VERSION 5.8 ;
BUSBITCHARS "[]" ;
DIVIDERCHAR "/" ;
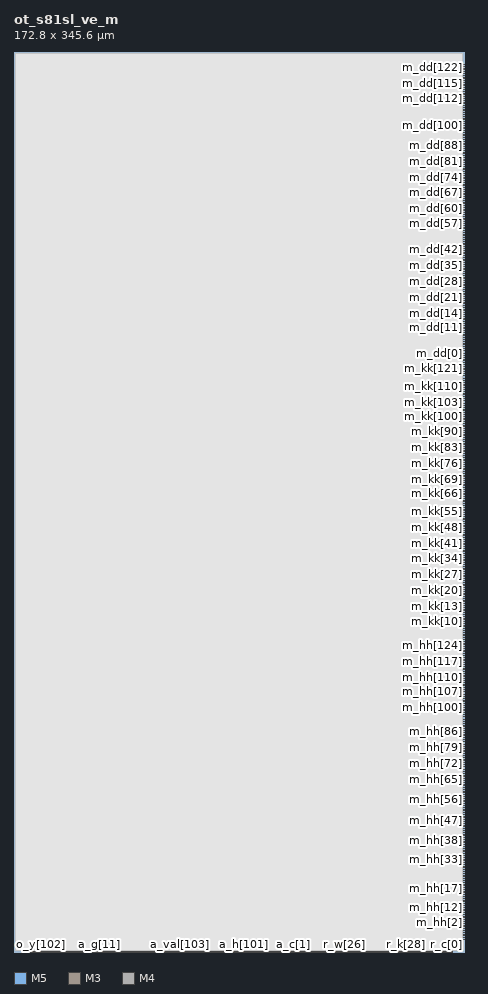
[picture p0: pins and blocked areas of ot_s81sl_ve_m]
MACRO ot_s81sl_ve_m
  CLASS BLOCK ;
  ORIGIN 0 0 ;
  FOREIGN ot_s81sl_ve_m 0 0 ;
  SIZE 172.800 BY 345.600 ;
  SYMMETRY X Y ;
  PIN a_c[0]
    DIRECTION INPUT ;
    USE SIGNAL ;
    PORT
      LAYER M5 ;
        RECT 107.6160 0.0000 107.6400 0.0840 ;
    END
  END a_c[0]
  PIN a_c[1]
    DIRECTION INPUT ;
    USE SIGNAL ;
    PORT
      LAYER M3 ;
        RECT 107.4960 0.0000 107.5140 0.0380 ;
    END
  END a_c[1]
  PIN a_g[0]
    DIRECTION INPUT ;
    USE SIGNAL ;
    PORT
      LAYER M5 ;
        RECT 34.9440 0.0000 34.9680 0.0840 ;
    END
  END a_g[0]
  PIN a_g[10]
    DIRECTION INPUT ;
    USE SIGNAL ;
    PORT
      LAYER M5 ;
        RECT 33.1200 0.0000 33.1440 0.0840 ;
    END
  END a_g[10]
  PIN a_g[11]
    DIRECTION INPUT ;
    USE SIGNAL ;
    PORT
      LAYER M3 ;
        RECT 32.9040 0.0000 32.9220 0.0380 ;
    END
  END a_g[11]
  PIN a_g[12]
    DIRECTION INPUT ;
    USE SIGNAL ;
    PORT
      LAYER M5 ;
        RECT 32.7360 0.0000 32.7600 0.0840 ;
    END
  END a_g[12]
  PIN a_g[13]
    DIRECTION INPUT ;
    USE SIGNAL ;
    PORT
      LAYER M3 ;
        RECT 32.5440 0.0000 32.5620 0.0380 ;
    END
  END a_g[13]
  PIN a_g[14]
    DIRECTION INPUT ;
    USE SIGNAL ;
    PORT
      LAYER M5 ;
        RECT 32.3520 0.0000 32.3760 0.0840 ;
    END
  END a_g[14]
  PIN a_g[15]
    DIRECTION INPUT ;
    USE SIGNAL ;
    PORT
      LAYER M3 ;
        RECT 32.1120 0.0000 32.1300 0.0380 ;
    END
  END a_g[15]
  PIN a_g[16]
    DIRECTION INPUT ;
    USE SIGNAL ;
    PORT
      LAYER M5 ;
        RECT 31.9680 0.0000 31.9920 0.0840 ;
    END
  END a_g[16]
  PIN a_g[17]
    DIRECTION INPUT ;
    USE SIGNAL ;
    PORT
      LAYER M3 ;
        RECT 31.7520 0.0000 31.7700 0.0380 ;
    END
  END a_g[17]
  PIN a_g[18]
    DIRECTION INPUT ;
    USE SIGNAL ;
    PORT
      LAYER M5 ;
        RECT 31.5840 0.0000 31.6080 0.0840 ;
    END
  END a_g[18]
  PIN a_g[19]
    DIRECTION INPUT ;
    USE SIGNAL ;
    PORT
      LAYER M3 ;
        RECT 31.3920 0.0000 31.4100 0.0380 ;
    END
  END a_g[19]
  PIN a_g[1]
    DIRECTION INPUT ;
    USE SIGNAL ;
    PORT
      LAYER M3 ;
        RECT 34.7760 0.0000 34.7940 0.0380 ;
    END
  END a_g[1]
  PIN a_g[20]
    DIRECTION INPUT ;
    USE SIGNAL ;
    PORT
      LAYER M5 ;
        RECT 31.2000 0.0000 31.2240 0.0840 ;
    END
  END a_g[20]
  PIN a_g[21]
    DIRECTION INPUT ;
    USE SIGNAL ;
    PORT
      LAYER M3 ;
        RECT 31.0320 0.0000 31.0500 0.0380 ;
    END
  END a_g[21]
  PIN a_g[22]
    DIRECTION INPUT ;
    USE SIGNAL ;
    PORT
      LAYER M5 ;
        RECT 30.8160 0.0000 30.8400 0.0840 ;
    END
  END a_g[22]
  PIN a_g[23]
    DIRECTION INPUT ;
    USE SIGNAL ;
    PORT
      LAYER M3 ;
        RECT 30.6720 0.0000 30.6900 0.0380 ;
    END
  END a_g[23]
  PIN a_g[24]
    DIRECTION INPUT ;
    USE SIGNAL ;
    PORT
      LAYER M5 ;
        RECT 30.4320 0.0000 30.4560 0.0840 ;
    END
  END a_g[24]
  PIN a_g[25]
    DIRECTION INPUT ;
    USE SIGNAL ;
    PORT
      LAYER M3 ;
        RECT 30.2400 0.0000 30.2580 0.0380 ;
    END
  END a_g[25]
  PIN a_g[26]
    DIRECTION INPUT ;
    USE SIGNAL ;
    PORT
      LAYER M5 ;
        RECT 30.0480 0.0000 30.0720 0.0840 ;
    END
  END a_g[26]
  PIN a_g[27]
    DIRECTION INPUT ;
    USE SIGNAL ;
    PORT
      LAYER M3 ;
        RECT 29.8800 0.0000 29.8980 0.0380 ;
    END
  END a_g[27]
  PIN a_g[28]
    DIRECTION INPUT ;
    USE SIGNAL ;
    PORT
      LAYER M5 ;
        RECT 29.6640 0.0000 29.6880 0.0840 ;
    END
  END a_g[28]
  PIN a_g[29]
    DIRECTION INPUT ;
    USE SIGNAL ;
    PORT
      LAYER M3 ;
        RECT 29.5200 0.0000 29.5380 0.0380 ;
    END
  END a_g[29]
  PIN a_g[2]
    DIRECTION INPUT ;
    USE SIGNAL ;
    PORT
      LAYER M5 ;
        RECT 34.5600 0.0000 34.5840 0.0840 ;
    END
  END a_g[2]
  PIN a_g[30]
    DIRECTION INPUT ;
    USE SIGNAL ;
    PORT
      LAYER M5 ;
        RECT 29.2800 0.0000 29.3040 0.0840 ;
    END
  END a_g[30]
  PIN a_g[31]
    DIRECTION INPUT ;
    USE SIGNAL ;
    PORT
      LAYER M3 ;
        RECT 29.1600 0.0000 29.1780 0.0380 ;
    END
  END a_g[31]
  PIN a_g[3]
    DIRECTION INPUT ;
    USE SIGNAL ;
    PORT
      LAYER M3 ;
        RECT 34.4160 0.0000 34.4340 0.0380 ;
    END
  END a_g[3]
  PIN a_g[4]
    DIRECTION INPUT ;
    USE SIGNAL ;
    PORT
      LAYER M5 ;
        RECT 34.1760 0.0000 34.2000 0.0840 ;
    END
  END a_g[4]
  PIN a_g[5]
    DIRECTION INPUT ;
    USE SIGNAL ;
    PORT
      LAYER M3 ;
        RECT 33.9840 0.0000 34.0020 0.0380 ;
    END
  END a_g[5]
  PIN a_g[6]
    DIRECTION INPUT ;
    USE SIGNAL ;
    PORT
      LAYER M5 ;
        RECT 33.7920 0.0000 33.8160 0.0840 ;
    END
  END a_g[6]
  PIN a_g[7]
    DIRECTION INPUT ;
    USE SIGNAL ;
    PORT
      LAYER M3 ;
        RECT 33.6240 0.0000 33.6420 0.0380 ;
    END
  END a_g[7]
  PIN a_g[8]
    DIRECTION INPUT ;
    USE SIGNAL ;
    PORT
      LAYER M5 ;
        RECT 33.4080 0.0000 33.4320 0.0840 ;
    END
  END a_g[8]
  PIN a_g[9]
    DIRECTION INPUT ;
    USE SIGNAL ;
    PORT
      LAYER M3 ;
        RECT 33.2640 0.0000 33.2820 0.0380 ;
    END
  END a_g[9]
  PIN a_h[0]
    DIRECTION INPUT ;
    USE SIGNAL ;
    PORT
      LAYER M5 ;
        RECT 107.3280 0.0000 107.3520 0.0840 ;
    END
  END a_h[0]
  PIN a_h[100]
    DIRECTION INPUT ;
    USE SIGNAL ;
    PORT
      LAYER M5 ;
        RECT 88.5120 0.0000 88.5360 0.0840 ;
    END
  END a_h[100]
  PIN a_h[101]
    DIRECTION INPUT ;
    USE SIGNAL ;
    PORT
      LAYER M3 ;
        RECT 88.3440 0.0000 88.3620 0.0380 ;
    END
  END a_h[101]
  PIN a_h[102]
    DIRECTION INPUT ;
    USE SIGNAL ;
    PORT
      LAYER M5 ;
        RECT 88.1280 0.0000 88.1520 0.0840 ;
    END
  END a_h[102]
  PIN a_h[103]
    DIRECTION INPUT ;
    USE SIGNAL ;
    PORT
      LAYER M3 ;
        RECT 87.9840 0.0000 88.0020 0.0380 ;
    END
  END a_h[103]
  PIN a_h[104]
    DIRECTION INPUT ;
    USE SIGNAL ;
    PORT
      LAYER M5 ;
        RECT 87.8400 0.0000 87.8640 0.0840 ;
    END
  END a_h[104]
  PIN a_h[105]
    DIRECTION INPUT ;
    USE SIGNAL ;
    PORT
      LAYER M3 ;
        RECT 87.6240 0.0000 87.6420 0.0380 ;
    END
  END a_h[105]
  PIN a_h[106]
    DIRECTION INPUT ;
    USE SIGNAL ;
    PORT
      LAYER M5 ;
        RECT 87.4560 0.0000 87.4800 0.0840 ;
    END
  END a_h[106]
  PIN a_h[107]
    DIRECTION INPUT ;
    USE SIGNAL ;
    PORT
      LAYER M3 ;
        RECT 87.2640 0.0000 87.2820 0.0380 ;
    END
  END a_h[107]
  PIN a_h[108]
    DIRECTION INPUT ;
    USE SIGNAL ;
    PORT
      LAYER M5 ;
        RECT 87.0720 0.0000 87.0960 0.0840 ;
    END
  END a_h[108]
  PIN a_h[109]
    DIRECTION INPUT ;
    USE SIGNAL ;
    PORT
      LAYER M3 ;
        RECT 86.8320 0.0000 86.8500 0.0380 ;
    END
  END a_h[109]
  PIN a_h[10]
    DIRECTION INPUT ;
    USE SIGNAL ;
    PORT
      LAYER M5 ;
        RECT 105.4080 0.0000 105.4320 0.0840 ;
    END
  END a_h[10]
  PIN a_h[110]
    DIRECTION INPUT ;
    USE SIGNAL ;
    PORT
      LAYER M5 ;
        RECT 86.6880 0.0000 86.7120 0.0840 ;
    END
  END a_h[110]
  PIN a_h[111]
    DIRECTION INPUT ;
    USE SIGNAL ;
    PORT
      LAYER M3 ;
        RECT 86.1120 0.0000 86.1300 0.0380 ;
    END
  END a_h[111]
  PIN a_h[112]
    DIRECTION INPUT ;
    USE SIGNAL ;
    PORT
      LAYER M5 ;
        RECT 85.9200 0.0000 85.9440 0.0840 ;
    END
  END a_h[112]
  PIN a_h[113]
    DIRECTION INPUT ;
    USE SIGNAL ;
    PORT
      LAYER M3 ;
        RECT 85.7520 0.0000 85.7700 0.0380 ;
    END
  END a_h[113]
  PIN a_h[114]
    DIRECTION INPUT ;
    USE SIGNAL ;
    PORT
      LAYER M5 ;
        RECT 85.5360 0.0000 85.5600 0.0840 ;
    END
  END a_h[114]
  PIN a_h[115]
    DIRECTION INPUT ;
    USE SIGNAL ;
    PORT
      LAYER M3 ;
        RECT 85.3920 0.0000 85.4100 0.0380 ;
    END
  END a_h[115]
  PIN a_h[116]
    DIRECTION INPUT ;
    USE SIGNAL ;
    PORT
      LAYER M5 ;
        RECT 85.1520 0.0000 85.1760 0.0840 ;
    END
  END a_h[116]
  PIN a_h[117]
    DIRECTION INPUT ;
    USE SIGNAL ;
    PORT
      LAYER M3 ;
        RECT 84.9600 0.0000 84.9780 0.0380 ;
    END
  END a_h[117]
  PIN a_h[118]
    DIRECTION INPUT ;
    USE SIGNAL ;
    PORT
      LAYER M5 ;
        RECT 84.7680 0.0000 84.7920 0.0840 ;
    END
  END a_h[118]
  PIN a_h[119]
    DIRECTION INPUT ;
    USE SIGNAL ;
    PORT
      LAYER M3 ;
        RECT 84.6000 0.0000 84.6180 0.0380 ;
    END
  END a_h[119]
  PIN a_h[11]
    DIRECTION INPUT ;
    USE SIGNAL ;
    PORT
      LAYER M3 ;
        RECT 105.1920 0.0000 105.2100 0.0380 ;
    END
  END a_h[11]
  PIN a_h[120]
    DIRECTION INPUT ;
    USE SIGNAL ;
    PORT
      LAYER M5 ;
        RECT 84.3840 0.0000 84.4080 0.0840 ;
    END
  END a_h[120]
  PIN a_h[121]
    DIRECTION INPUT ;
    USE SIGNAL ;
    PORT
      LAYER M3 ;
        RECT 84.2400 0.0000 84.2580 0.0380 ;
    END
  END a_h[121]
  PIN a_h[122]
    DIRECTION INPUT ;
    USE SIGNAL ;
    PORT
      LAYER M5 ;
        RECT 84.0000 0.0000 84.0240 0.0840 ;
    END
  END a_h[122]
  PIN a_h[123]
    DIRECTION INPUT ;
    USE SIGNAL ;
    PORT
      LAYER M3 ;
        RECT 83.8800 0.0000 83.8980 0.0380 ;
    END
  END a_h[123]
  PIN a_h[124]
    DIRECTION INPUT ;
    USE SIGNAL ;
    PORT
      LAYER M5 ;
        RECT 83.7120 0.0000 83.7360 0.0840 ;
    END
  END a_h[124]
  PIN a_h[125]
    DIRECTION INPUT ;
    USE SIGNAL ;
    PORT
      LAYER M3 ;
        RECT 83.5200 0.0000 83.5380 0.0380 ;
    END
  END a_h[125]
  PIN a_h[126]
    DIRECTION INPUT ;
    USE SIGNAL ;
    PORT
      LAYER M5 ;
        RECT 83.3280 0.0000 83.3520 0.0840 ;
    END
  END a_h[126]
  PIN a_h[127]
    DIRECTION INPUT ;
    USE SIGNAL ;
    PORT
      LAYER M3 ;
        RECT 83.0880 0.0000 83.1060 0.0380 ;
    END
  END a_h[127]
  PIN a_h[12]
    DIRECTION INPUT ;
    USE SIGNAL ;
    PORT
      LAYER M5 ;
        RECT 105.0240 0.0000 105.0480 0.0840 ;
    END
  END a_h[12]
  PIN a_h[13]
    DIRECTION INPUT ;
    USE SIGNAL ;
    PORT
      LAYER M3 ;
        RECT 104.8320 0.0000 104.8500 0.0380 ;
    END
  END a_h[13]
  PIN a_h[14]
    DIRECTION INPUT ;
    USE SIGNAL ;
    PORT
      LAYER M5 ;
        RECT 104.6400 0.0000 104.6640 0.0840 ;
    END
  END a_h[14]
  PIN a_h[15]
    DIRECTION INPUT ;
    USE SIGNAL ;
    PORT
      LAYER M3 ;
        RECT 104.4720 0.0000 104.4900 0.0380 ;
    END
  END a_h[15]
  PIN a_h[16]
    DIRECTION INPUT ;
    USE SIGNAL ;
    PORT
      LAYER M5 ;
        RECT 104.2560 0.0000 104.2800 0.0840 ;
    END
  END a_h[16]
  PIN a_h[17]
    DIRECTION INPUT ;
    USE SIGNAL ;
    PORT
      LAYER M3 ;
        RECT 104.1120 0.0000 104.1300 0.0380 ;
    END
  END a_h[17]
  PIN a_h[18]
    DIRECTION INPUT ;
    USE SIGNAL ;
    PORT
      LAYER M5 ;
        RECT 103.8720 0.0000 103.8960 0.0840 ;
    END
  END a_h[18]
  PIN a_h[19]
    DIRECTION INPUT ;
    USE SIGNAL ;
    PORT
      LAYER M3 ;
        RECT 103.7520 0.0000 103.7700 0.0380 ;
    END
  END a_h[19]
  PIN a_h[1]
    DIRECTION INPUT ;
    USE SIGNAL ;
    PORT
      LAYER M3 ;
        RECT 107.0640 0.0000 107.0820 0.0380 ;
    END
  END a_h[1]
  PIN a_h[20]
    DIRECTION INPUT ;
    USE SIGNAL ;
    PORT
      LAYER M5 ;
        RECT 103.4880 0.0000 103.5120 0.0840 ;
    END
  END a_h[20]
  PIN a_h[21]
    DIRECTION INPUT ;
    USE SIGNAL ;
    PORT
      LAYER M3 ;
        RECT 103.3200 0.0000 103.3380 0.0380 ;
    END
  END a_h[21]
  PIN a_h[22]
    DIRECTION INPUT ;
    USE SIGNAL ;
    PORT
      LAYER M5 ;
        RECT 103.2000 0.0000 103.2240 0.0840 ;
    END
  END a_h[22]
  PIN a_h[23]
    DIRECTION INPUT ;
    USE SIGNAL ;
    PORT
      LAYER M3 ;
        RECT 102.9600 0.0000 102.9780 0.0380 ;
    END
  END a_h[23]
  PIN a_h[24]
    DIRECTION INPUT ;
    USE SIGNAL ;
    PORT
      LAYER M5 ;
        RECT 102.8160 0.0000 102.8400 0.0840 ;
    END
  END a_h[24]
  PIN a_h[25]
    DIRECTION INPUT ;
    USE SIGNAL ;
    PORT
      LAYER M3 ;
        RECT 102.6000 0.0000 102.6180 0.0380 ;
    END
  END a_h[25]
  PIN a_h[26]
    DIRECTION INPUT ;
    USE SIGNAL ;
    PORT
      LAYER M5 ;
        RECT 102.4320 0.0000 102.4560 0.0840 ;
    END
  END a_h[26]
  PIN a_h[27]
    DIRECTION INPUT ;
    USE SIGNAL ;
    PORT
      LAYER M3 ;
        RECT 102.2400 0.0000 102.2580 0.0380 ;
    END
  END a_h[27]
  PIN a_h[28]
    DIRECTION INPUT ;
    USE SIGNAL ;
    PORT
      LAYER M5 ;
        RECT 102.0480 0.0000 102.0720 0.0840 ;
    END
  END a_h[28]
  PIN a_h[29]
    DIRECTION INPUT ;
    USE SIGNAL ;
    PORT
      LAYER M3 ;
        RECT 101.8800 0.0000 101.8980 0.0380 ;
    END
  END a_h[29]
  PIN a_h[2]
    DIRECTION INPUT ;
    USE SIGNAL ;
    PORT
      LAYER M5 ;
        RECT 106.9440 0.0000 106.9680 0.0840 ;
    END
  END a_h[2]
  PIN a_h[30]
    DIRECTION INPUT ;
    USE SIGNAL ;
    PORT
      LAYER M5 ;
        RECT 101.6640 0.0000 101.6880 0.0840 ;
    END
  END a_h[30]
  PIN a_h[31]
    DIRECTION INPUT ;
    USE SIGNAL ;
    PORT
      LAYER M3 ;
        RECT 101.4480 0.0000 101.4660 0.0380 ;
    END
  END a_h[31]
  PIN a_h[32]
    DIRECTION INPUT ;
    USE SIGNAL ;
    PORT
      LAYER M5 ;
        RECT 101.2800 0.0000 101.3040 0.0840 ;
    END
  END a_h[32]
  PIN a_h[33]
    DIRECTION INPUT ;
    USE SIGNAL ;
    PORT
      LAYER M3 ;
        RECT 101.0880 0.0000 101.1060 0.0380 ;
    END
  END a_h[33]
  PIN a_h[34]
    DIRECTION INPUT ;
    USE SIGNAL ;
    PORT
      LAYER M5 ;
        RECT 100.8960 0.0000 100.9200 0.0840 ;
    END
  END a_h[34]
  PIN a_h[35]
    DIRECTION INPUT ;
    USE SIGNAL ;
    PORT
      LAYER M3 ;
        RECT 100.7280 0.0000 100.7460 0.0380 ;
    END
  END a_h[35]
  PIN a_h[36]
    DIRECTION INPUT ;
    USE SIGNAL ;
    PORT
      LAYER M5 ;
        RECT 100.5120 0.0000 100.5360 0.0840 ;
    END
  END a_h[36]
  PIN a_h[37]
    DIRECTION INPUT ;
    USE SIGNAL ;
    PORT
      LAYER M3 ;
        RECT 100.3680 0.0000 100.3860 0.0380 ;
    END
  END a_h[37]
  PIN a_h[38]
    DIRECTION INPUT ;
    USE SIGNAL ;
    PORT
      LAYER M5 ;
        RECT 100.1280 0.0000 100.1520 0.0840 ;
    END
  END a_h[38]
  PIN a_h[39]
    DIRECTION INPUT ;
    USE SIGNAL ;
    PORT
      LAYER M3 ;
        RECT 100.0080 0.0000 100.0260 0.0380 ;
    END
  END a_h[39]
  PIN a_h[3]
    DIRECTION INPUT ;
    USE SIGNAL ;
    PORT
      LAYER M3 ;
        RECT 106.7040 0.0000 106.7220 0.0380 ;
    END
  END a_h[3]
  PIN a_h[40]
    DIRECTION INPUT ;
    USE SIGNAL ;
    PORT
      LAYER M5 ;
        RECT 99.7440 0.0000 99.7680 0.0840 ;
    END
  END a_h[40]
  PIN a_h[41]
    DIRECTION INPUT ;
    USE SIGNAL ;
    PORT
      LAYER M3 ;
        RECT 99.5760 0.0000 99.5940 0.0380 ;
    END
  END a_h[41]
  PIN a_h[42]
    DIRECTION INPUT ;
    USE SIGNAL ;
    PORT
      LAYER M5 ;
        RECT 99.4560 0.0000 99.4800 0.0840 ;
    END
  END a_h[42]
  PIN a_h[43]
    DIRECTION INPUT ;
    USE SIGNAL ;
    PORT
      LAYER M3 ;
        RECT 99.2160 0.0000 99.2340 0.0380 ;
    END
  END a_h[43]
  PIN a_h[44]
    DIRECTION INPUT ;
    USE SIGNAL ;
    PORT
      LAYER M5 ;
        RECT 99.0720 0.0000 99.0960 0.0840 ;
    END
  END a_h[44]
  PIN a_h[45]
    DIRECTION INPUT ;
    USE SIGNAL ;
    PORT
      LAYER M3 ;
        RECT 98.8560 0.0000 98.8740 0.0380 ;
    END
  END a_h[45]
  PIN a_h[46]
    DIRECTION INPUT ;
    USE SIGNAL ;
    PORT
      LAYER M5 ;
        RECT 98.6880 0.0000 98.7120 0.0840 ;
    END
  END a_h[46]
  PIN a_h[47]
    DIRECTION INPUT ;
    USE SIGNAL ;
    PORT
      LAYER M3 ;
        RECT 98.4960 0.0000 98.5140 0.0380 ;
    END
  END a_h[47]
  PIN a_h[48]
    DIRECTION INPUT ;
    USE SIGNAL ;
    PORT
      LAYER M5 ;
        RECT 98.3040 0.0000 98.3280 0.0840 ;
    END
  END a_h[48]
  PIN a_h[49]
    DIRECTION INPUT ;
    USE SIGNAL ;
    PORT
      LAYER M3 ;
        RECT 98.1360 0.0000 98.1540 0.0380 ;
    END
  END a_h[49]
  PIN a_h[4]
    DIRECTION INPUT ;
    USE SIGNAL ;
    PORT
      LAYER M5 ;
        RECT 106.5600 0.0000 106.5840 0.0840 ;
    END
  END a_h[4]
  PIN a_h[50]
    DIRECTION INPUT ;
    USE SIGNAL ;
    PORT
      LAYER M5 ;
        RECT 97.9200 0.0000 97.9440 0.0840 ;
    END
  END a_h[50]
  PIN a_h[51]
    DIRECTION INPUT ;
    USE SIGNAL ;
    PORT
      LAYER M3 ;
        RECT 97.7040 0.0000 97.7220 0.0380 ;
    END
  END a_h[51]
  PIN a_h[52]
    DIRECTION INPUT ;
    USE SIGNAL ;
    PORT
      LAYER M5 ;
        RECT 97.5360 0.0000 97.5600 0.0840 ;
    END
  END a_h[52]
  PIN a_h[53]
    DIRECTION INPUT ;
    USE SIGNAL ;
    PORT
      LAYER M3 ;
        RECT 97.3440 0.0000 97.3620 0.0380 ;
    END
  END a_h[53]
  PIN a_h[54]
    DIRECTION INPUT ;
    USE SIGNAL ;
    PORT
      LAYER M5 ;
        RECT 97.1520 0.0000 97.1760 0.0840 ;
    END
  END a_h[54]
  PIN a_h[55]
    DIRECTION INPUT ;
    USE SIGNAL ;
    PORT
      LAYER M3 ;
        RECT 96.9840 0.0000 97.0020 0.0380 ;
    END
  END a_h[55]
  PIN a_h[56]
    DIRECTION INPUT ;
    USE SIGNAL ;
    PORT
      LAYER M5 ;
        RECT 96.7680 0.0000 96.7920 0.0840 ;
    END
  END a_h[56]
  PIN a_h[57]
    DIRECTION INPUT ;
    USE SIGNAL ;
    PORT
      LAYER M3 ;
        RECT 96.6240 0.0000 96.6420 0.0380 ;
    END
  END a_h[57]
  PIN a_h[58]
    DIRECTION INPUT ;
    USE SIGNAL ;
    PORT
      LAYER M5 ;
        RECT 96.3840 0.0000 96.4080 0.0840 ;
    END
  END a_h[58]
  PIN a_h[59]
    DIRECTION INPUT ;
    USE SIGNAL ;
    PORT
      LAYER M3 ;
        RECT 96.2640 0.0000 96.2820 0.0380 ;
    END
  END a_h[59]
  PIN a_h[5]
    DIRECTION INPUT ;
    USE SIGNAL ;
    PORT
      LAYER M3 ;
        RECT 106.3440 0.0000 106.3620 0.0380 ;
    END
  END a_h[5]
  PIN a_h[60]
    DIRECTION INPUT ;
    USE SIGNAL ;
    PORT
      LAYER M5 ;
        RECT 96.0000 0.0000 96.0240 0.0840 ;
    END
  END a_h[60]
  PIN a_h[61]
    DIRECTION INPUT ;
    USE SIGNAL ;
    PORT
      LAYER M3 ;
        RECT 95.8320 0.0000 95.8500 0.0380 ;
    END
  END a_h[61]
  PIN a_h[62]
    DIRECTION INPUT ;
    USE SIGNAL ;
    PORT
      LAYER M5 ;
        RECT 95.7120 0.0000 95.7360 0.0840 ;
    END
  END a_h[62]
  PIN a_h[63]
    DIRECTION INPUT ;
    USE SIGNAL ;
    PORT
      LAYER M3 ;
        RECT 95.4720 0.0000 95.4900 0.0380 ;
    END
  END a_h[63]
  PIN a_h[64]
    DIRECTION INPUT ;
    USE SIGNAL ;
    PORT
      LAYER M5 ;
        RECT 95.3280 0.0000 95.3520 0.0840 ;
    END
  END a_h[64]
  PIN a_h[65]
    DIRECTION INPUT ;
    USE SIGNAL ;
    PORT
      LAYER M3 ;
        RECT 95.1120 0.0000 95.1300 0.0380 ;
    END
  END a_h[65]
  PIN a_h[66]
    DIRECTION INPUT ;
    USE SIGNAL ;
    PORT
      LAYER M5 ;
        RECT 94.9440 0.0000 94.9680 0.0840 ;
    END
  END a_h[66]
  PIN a_h[67]
    DIRECTION INPUT ;
    USE SIGNAL ;
    PORT
      LAYER M3 ;
        RECT 94.7520 0.0000 94.7700 0.0380 ;
    END
  END a_h[67]
  PIN a_h[68]
    DIRECTION INPUT ;
    USE SIGNAL ;
    PORT
      LAYER M5 ;
        RECT 94.5600 0.0000 94.5840 0.0840 ;
    END
  END a_h[68]
  PIN a_h[69]
    DIRECTION INPUT ;
    USE SIGNAL ;
    PORT
      LAYER M3 ;
        RECT 94.3200 0.0000 94.3380 0.0380 ;
    END
  END a_h[69]
  PIN a_h[6]
    DIRECTION INPUT ;
    USE SIGNAL ;
    PORT
      LAYER M5 ;
        RECT 106.1760 0.0000 106.2000 0.0840 ;
    END
  END a_h[6]
  PIN a_h[70]
    DIRECTION INPUT ;
    USE SIGNAL ;
    PORT
      LAYER M5 ;
        RECT 94.1760 0.0000 94.2000 0.0840 ;
    END
  END a_h[70]
  PIN a_h[71]
    DIRECTION INPUT ;
    USE SIGNAL ;
    PORT
      LAYER M3 ;
        RECT 93.9600 0.0000 93.9780 0.0380 ;
    END
  END a_h[71]
  PIN a_h[72]
    DIRECTION INPUT ;
    USE SIGNAL ;
    PORT
      LAYER M5 ;
        RECT 93.7920 0.0000 93.8160 0.0840 ;
    END
  END a_h[72]
  PIN a_h[73]
    DIRECTION INPUT ;
    USE SIGNAL ;
    PORT
      LAYER M3 ;
        RECT 93.6000 0.0000 93.6180 0.0380 ;
    END
  END a_h[73]
  PIN a_h[74]
    DIRECTION INPUT ;
    USE SIGNAL ;
    PORT
      LAYER M5 ;
        RECT 93.4080 0.0000 93.4320 0.0840 ;
    END
  END a_h[74]
  PIN a_h[75]
    DIRECTION INPUT ;
    USE SIGNAL ;
    PORT
      LAYER M3 ;
        RECT 93.2400 0.0000 93.2580 0.0380 ;
    END
  END a_h[75]
  PIN a_h[76]
    DIRECTION INPUT ;
    USE SIGNAL ;
    PORT
      LAYER M5 ;
        RECT 93.0240 0.0000 93.0480 0.0840 ;
    END
  END a_h[76]
  PIN a_h[77]
    DIRECTION INPUT ;
    USE SIGNAL ;
    PORT
      LAYER M3 ;
        RECT 92.8800 0.0000 92.8980 0.0380 ;
    END
  END a_h[77]
  PIN a_h[78]
    DIRECTION INPUT ;
    USE SIGNAL ;
    PORT
      LAYER M5 ;
        RECT 92.6400 0.0000 92.6640 0.0840 ;
    END
  END a_h[78]
  PIN a_h[79]
    DIRECTION INPUT ;
    USE SIGNAL ;
    PORT
      LAYER M3 ;
        RECT 92.4480 0.0000 92.4660 0.0380 ;
    END
  END a_h[79]
  PIN a_h[7]
    DIRECTION INPUT ;
    USE SIGNAL ;
    PORT
      LAYER M3 ;
        RECT 105.9840 0.0000 106.0020 0.0380 ;
    END
  END a_h[7]
  PIN a_h[80]
    DIRECTION INPUT ;
    USE SIGNAL ;
    PORT
      LAYER M5 ;
        RECT 92.2560 0.0000 92.2800 0.0840 ;
    END
  END a_h[80]
  PIN a_h[81]
    DIRECTION INPUT ;
    USE SIGNAL ;
    PORT
      LAYER M3 ;
        RECT 92.0880 0.0000 92.1060 0.0380 ;
    END
  END a_h[81]
  PIN a_h[82]
    DIRECTION INPUT ;
    USE SIGNAL ;
    PORT
      LAYER M5 ;
        RECT 91.8720 0.0000 91.8960 0.0840 ;
    END
  END a_h[82]
  PIN a_h[83]
    DIRECTION INPUT ;
    USE SIGNAL ;
    PORT
      LAYER M3 ;
        RECT 91.7280 0.0000 91.7460 0.0380 ;
    END
  END a_h[83]
  PIN a_h[84]
    DIRECTION INPUT ;
    USE SIGNAL ;
    PORT
      LAYER M5 ;
        RECT 91.5840 0.0000 91.6080 0.0840 ;
    END
  END a_h[84]
  PIN a_h[85]
    DIRECTION INPUT ;
    USE SIGNAL ;
    PORT
      LAYER M3 ;
        RECT 91.3680 0.0000 91.3860 0.0380 ;
    END
  END a_h[85]
  PIN a_h[86]
    DIRECTION INPUT ;
    USE SIGNAL ;
    PORT
      LAYER M5 ;
        RECT 91.2000 0.0000 91.2240 0.0840 ;
    END
  END a_h[86]
  PIN a_h[87]
    DIRECTION INPUT ;
    USE SIGNAL ;
    PORT
      LAYER M3 ;
        RECT 91.0080 0.0000 91.0260 0.0380 ;
    END
  END a_h[87]
  PIN a_h[88]
    DIRECTION INPUT ;
    USE SIGNAL ;
    PORT
      LAYER M5 ;
        RECT 90.8160 0.0000 90.8400 0.0840 ;
    END
  END a_h[88]
  PIN a_h[89]
    DIRECTION INPUT ;
    USE SIGNAL ;
    PORT
      LAYER M3 ;
        RECT 90.5760 0.0000 90.5940 0.0380 ;
    END
  END a_h[89]
  PIN a_h[8]
    DIRECTION INPUT ;
    USE SIGNAL ;
    PORT
      LAYER M5 ;
        RECT 105.7920 0.0000 105.8160 0.0840 ;
    END
  END a_h[8]
  PIN a_h[90]
    DIRECTION INPUT ;
    USE SIGNAL ;
    PORT
      LAYER M5 ;
        RECT 90.4320 0.0000 90.4560 0.0840 ;
    END
  END a_h[90]
  PIN a_h[91]
    DIRECTION INPUT ;
    USE SIGNAL ;
    PORT
      LAYER M3 ;
        RECT 90.2160 0.0000 90.2340 0.0380 ;
    END
  END a_h[91]
  PIN a_h[92]
    DIRECTION INPUT ;
    USE SIGNAL ;
    PORT
      LAYER M5 ;
        RECT 90.0480 0.0000 90.0720 0.0840 ;
    END
  END a_h[92]
  PIN a_h[93]
    DIRECTION INPUT ;
    USE SIGNAL ;
    PORT
      LAYER M3 ;
        RECT 89.8560 0.0000 89.8740 0.0380 ;
    END
  END a_h[93]
  PIN a_h[94]
    DIRECTION INPUT ;
    USE SIGNAL ;
    PORT
      LAYER M5 ;
        RECT 89.6640 0.0000 89.6880 0.0840 ;
    END
  END a_h[94]
  PIN a_h[95]
    DIRECTION INPUT ;
    USE SIGNAL ;
    PORT
      LAYER M3 ;
        RECT 89.4960 0.0000 89.5140 0.0380 ;
    END
  END a_h[95]
  PIN a_h[96]
    DIRECTION INPUT ;
    USE SIGNAL ;
    PORT
      LAYER M5 ;
        RECT 89.2800 0.0000 89.3040 0.0840 ;
    END
  END a_h[96]
  PIN a_h[97]
    DIRECTION INPUT ;
    USE SIGNAL ;
    PORT
      LAYER M3 ;
        RECT 89.1360 0.0000 89.1540 0.0380 ;
    END
  END a_h[97]
  PIN a_h[98]
    DIRECTION INPUT ;
    USE SIGNAL ;
    PORT
      LAYER M5 ;
        RECT 88.8960 0.0000 88.9200 0.0840 ;
    END
  END a_h[98]
  PIN a_h[99]
    DIRECTION INPUT ;
    USE SIGNAL ;
    PORT
      LAYER M3 ;
        RECT 88.7040 0.0000 88.7220 0.0380 ;
    END
  END a_h[99]
  PIN a_h[9]
    DIRECTION INPUT ;
    USE SIGNAL ;
    PORT
      LAYER M3 ;
        RECT 105.6240 0.0000 105.6420 0.0380 ;
    END
  END a_h[9]
  PIN a_v
    DIRECTION INPUT ;
    USE SIGNAL ;
    PORT
      LAYER M3 ;
        RECT 107.8560 0.0000 107.8740 0.0380 ;
    END
  END a_v
  PIN a_val[0]
    DIRECTION INPUT ;
    USE SIGNAL ;
    PORT
      LAYER M5 ;
        RECT 82.9440 0.0000 82.9680 0.0840 ;
    END
  END a_val[0]
  PIN a_val[100]
    DIRECTION INPUT ;
    USE SIGNAL ;
    PORT
      LAYER M5 ;
        RECT 64.2240 0.0000 64.2480 0.0840 ;
    END
  END a_val[100]
  PIN a_val[101]
    DIRECTION INPUT ;
    USE SIGNAL ;
    PORT
      LAYER M3 ;
        RECT 64.0080 0.0000 64.0260 0.0380 ;
    END
  END a_val[101]
  PIN a_val[102]
    DIRECTION INPUT ;
    USE SIGNAL ;
    PORT
      LAYER M5 ;
        RECT 63.8400 0.0000 63.8640 0.0840 ;
    END
  END a_val[102]
  PIN a_val[103]
    DIRECTION INPUT ;
    USE SIGNAL ;
    PORT
      LAYER M3 ;
        RECT 63.6480 0.0000 63.6660 0.0380 ;
    END
  END a_val[103]
  PIN a_val[104]
    DIRECTION INPUT ;
    USE SIGNAL ;
    PORT
      LAYER M5 ;
        RECT 63.4560 0.0000 63.4800 0.0840 ;
    END
  END a_val[104]
  PIN a_val[105]
    DIRECTION INPUT ;
    USE SIGNAL ;
    PORT
      LAYER M3 ;
        RECT 63.2160 0.0000 63.2340 0.0380 ;
    END
  END a_val[105]
  PIN a_val[106]
    DIRECTION INPUT ;
    USE SIGNAL ;
    PORT
      LAYER M5 ;
        RECT 63.0720 0.0000 63.0960 0.0840 ;
    END
  END a_val[106]
  PIN a_val[107]
    DIRECTION INPUT ;
    USE SIGNAL ;
    PORT
      LAYER M3 ;
        RECT 62.8560 0.0000 62.8740 0.0380 ;
    END
  END a_val[107]
  PIN a_val[108]
    DIRECTION INPUT ;
    USE SIGNAL ;
    PORT
      LAYER M5 ;
        RECT 62.6880 0.0000 62.7120 0.0840 ;
    END
  END a_val[108]
  PIN a_val[109]
    DIRECTION INPUT ;
    USE SIGNAL ;
    PORT
      LAYER M3 ;
        RECT 62.4960 0.0000 62.5140 0.0380 ;
    END
  END a_val[109]
  PIN a_val[10]
    DIRECTION INPUT ;
    USE SIGNAL ;
    PORT
      LAYER M5 ;
        RECT 81.0240 0.0000 81.0480 0.0840 ;
    END
  END a_val[10]
  PIN a_val[110]
    DIRECTION INPUT ;
    USE SIGNAL ;
    PORT
      LAYER M5 ;
        RECT 62.3040 0.0000 62.3280 0.0840 ;
    END
  END a_val[110]
  PIN a_val[111]
    DIRECTION INPUT ;
    USE SIGNAL ;
    PORT
      LAYER M3 ;
        RECT 62.1360 0.0000 62.1540 0.0380 ;
    END
  END a_val[111]
  PIN a_val[112]
    DIRECTION INPUT ;
    USE SIGNAL ;
    PORT
      LAYER M5 ;
        RECT 61.9200 0.0000 61.9440 0.0840 ;
    END
  END a_val[112]
  PIN a_val[113]
    DIRECTION INPUT ;
    USE SIGNAL ;
    PORT
      LAYER M3 ;
        RECT 61.7760 0.0000 61.7940 0.0380 ;
    END
  END a_val[113]
  PIN a_val[114]
    DIRECTION INPUT ;
    USE SIGNAL ;
    PORT
      LAYER M5 ;
        RECT 61.5360 0.0000 61.5600 0.0840 ;
    END
  END a_val[114]
  PIN a_val[115]
    DIRECTION INPUT ;
    USE SIGNAL ;
    PORT
      LAYER M3 ;
        RECT 61.3440 0.0000 61.3620 0.0380 ;
    END
  END a_val[115]
  PIN a_val[116]
    DIRECTION INPUT ;
    USE SIGNAL ;
    PORT
      LAYER M5 ;
        RECT 61.1520 0.0000 61.1760 0.0840 ;
    END
  END a_val[116]
  PIN a_val[117]
    DIRECTION INPUT ;
    USE SIGNAL ;
    PORT
      LAYER M3 ;
        RECT 60.9840 0.0000 61.0020 0.0380 ;
    END
  END a_val[117]
  PIN a_val[118]
    DIRECTION INPUT ;
    USE SIGNAL ;
    PORT
      LAYER M5 ;
        RECT 60.7680 0.0000 60.7920 0.0840 ;
    END
  END a_val[118]
  PIN a_val[119]
    DIRECTION INPUT ;
    USE SIGNAL ;
    PORT
      LAYER M3 ;
        RECT 60.6240 0.0000 60.6420 0.0380 ;
    END
  END a_val[119]
  PIN a_val[11]
    DIRECTION INPUT ;
    USE SIGNAL ;
    PORT
      LAYER M3 ;
        RECT 80.8560 0.0000 80.8740 0.0380 ;
    END
  END a_val[11]
  PIN a_val[120]
    DIRECTION INPUT ;
    USE SIGNAL ;
    PORT
      LAYER M5 ;
        RECT 60.4800 0.0000 60.5040 0.0840 ;
    END
  END a_val[120]
  PIN a_val[121]
    DIRECTION INPUT ;
    USE SIGNAL ;
    PORT
      LAYER M3 ;
        RECT 60.2640 0.0000 60.2820 0.0380 ;
    END
  END a_val[121]
  PIN a_val[122]
    DIRECTION INPUT ;
    USE SIGNAL ;
    PORT
      LAYER M5 ;
        RECT 60.0960 0.0000 60.1200 0.0840 ;
    END
  END a_val[122]
  PIN a_val[123]
    DIRECTION INPUT ;
    USE SIGNAL ;
    PORT
      LAYER M3 ;
        RECT 59.9040 0.0000 59.9220 0.0380 ;
    END
  END a_val[123]
  PIN a_val[124]
    DIRECTION INPUT ;
    USE SIGNAL ;
    PORT
      LAYER M5 ;
        RECT 59.7120 0.0000 59.7360 0.0840 ;
    END
  END a_val[124]
  PIN a_val[125]
    DIRECTION INPUT ;
    USE SIGNAL ;
    PORT
      LAYER M3 ;
        RECT 59.4720 0.0000 59.4900 0.0380 ;
    END
  END a_val[125]
  PIN a_val[126]
    DIRECTION INPUT ;
    USE SIGNAL ;
    PORT
      LAYER M5 ;
        RECT 59.3280 0.0000 59.3520 0.0840 ;
    END
  END a_val[126]
  PIN a_val[127]
    DIRECTION INPUT ;
    USE SIGNAL ;
    PORT
      LAYER M3 ;
        RECT 59.1120 0.0000 59.1300 0.0380 ;
    END
  END a_val[127]
  PIN a_val[128]
    DIRECTION INPUT ;
    USE SIGNAL ;
    PORT
      LAYER M5 ;
        RECT 58.9440 0.0000 58.9680 0.0840 ;
    END
  END a_val[128]
  PIN a_val[129]
    DIRECTION INPUT ;
    USE SIGNAL ;
    PORT
      LAYER M3 ;
        RECT 58.7520 0.0000 58.7700 0.0380 ;
    END
  END a_val[129]
  PIN a_val[12]
    DIRECTION INPUT ;
    USE SIGNAL ;
    PORT
      LAYER M5 ;
        RECT 80.6400 0.0000 80.6640 0.0840 ;
    END
  END a_val[12]
  PIN a_val[130]
    DIRECTION INPUT ;
    USE SIGNAL ;
    PORT
      LAYER M5 ;
        RECT 58.5600 0.0000 58.5840 0.0840 ;
    END
  END a_val[130]
  PIN a_val[131]
    DIRECTION INPUT ;
    USE SIGNAL ;
    PORT
      LAYER M3 ;
        RECT 58.3920 0.0000 58.4100 0.0380 ;
    END
  END a_val[131]
  PIN a_val[132]
    DIRECTION INPUT ;
    USE SIGNAL ;
    PORT
      LAYER M5 ;
        RECT 58.1760 0.0000 58.2000 0.0840 ;
    END
  END a_val[132]
  PIN a_val[133]
    DIRECTION INPUT ;
    USE SIGNAL ;
    PORT
      LAYER M3 ;
        RECT 58.0320 0.0000 58.0500 0.0380 ;
    END
  END a_val[133]
  PIN a_val[134]
    DIRECTION INPUT ;
    USE SIGNAL ;
    PORT
      LAYER M5 ;
        RECT 57.7920 0.0000 57.8160 0.0840 ;
    END
  END a_val[134]
  PIN a_val[135]
    DIRECTION INPUT ;
    USE SIGNAL ;
    PORT
      LAYER M3 ;
        RECT 57.6000 0.0000 57.6180 0.0380 ;
    END
  END a_val[135]
  PIN a_val[136]
    DIRECTION INPUT ;
    USE SIGNAL ;
    PORT
      LAYER M5 ;
        RECT 57.4080 0.0000 57.4320 0.0840 ;
    END
  END a_val[136]
  PIN a_val[137]
    DIRECTION INPUT ;
    USE SIGNAL ;
    PORT
      LAYER M3 ;
        RECT 57.2400 0.0000 57.2580 0.0380 ;
    END
  END a_val[137]
  PIN a_val[138]
    DIRECTION INPUT ;
    USE SIGNAL ;
    PORT
      LAYER M5 ;
        RECT 57.0240 0.0000 57.0480 0.0840 ;
    END
  END a_val[138]
  PIN a_val[139]
    DIRECTION INPUT ;
    USE SIGNAL ;
    PORT
      LAYER M3 ;
        RECT 56.8800 0.0000 56.8980 0.0380 ;
    END
  END a_val[139]
  PIN a_val[13]
    DIRECTION INPUT ;
    USE SIGNAL ;
    PORT
      LAYER M3 ;
        RECT 80.4960 0.0000 80.5140 0.0380 ;
    END
  END a_val[13]
  PIN a_val[140]
    DIRECTION INPUT ;
    USE SIGNAL ;
    PORT
      LAYER M5 ;
        RECT 56.6400 0.0000 56.6640 0.0840 ;
    END
  END a_val[140]
  PIN a_val[141]
    DIRECTION INPUT ;
    USE SIGNAL ;
    PORT
      LAYER M3 ;
        RECT 56.5200 0.0000 56.5380 0.0380 ;
    END
  END a_val[141]
  PIN a_val[142]
    DIRECTION INPUT ;
    USE SIGNAL ;
    PORT
      LAYER M5 ;
        RECT 56.3520 0.0000 56.3760 0.0840 ;
    END
  END a_val[142]
  PIN a_val[143]
    DIRECTION INPUT ;
    USE SIGNAL ;
    PORT
      LAYER M3 ;
        RECT 56.1600 0.0000 56.1780 0.0380 ;
    END
  END a_val[143]
  PIN a_val[144]
    DIRECTION INPUT ;
    USE SIGNAL ;
    PORT
      LAYER M5 ;
        RECT 55.9680 0.0000 55.9920 0.0840 ;
    END
  END a_val[144]
  PIN a_val[145]
    DIRECTION INPUT ;
    USE SIGNAL ;
    PORT
      LAYER M3 ;
        RECT 55.7280 0.0000 55.7460 0.0380 ;
    END
  END a_val[145]
  PIN a_val[146]
    DIRECTION INPUT ;
    USE SIGNAL ;
    PORT
      LAYER M5 ;
        RECT 55.5840 0.0000 55.6080 0.0840 ;
    END
  END a_val[146]
  PIN a_val[147]
    DIRECTION INPUT ;
    USE SIGNAL ;
    PORT
      LAYER M3 ;
        RECT 55.3680 0.0000 55.3860 0.0380 ;
    END
  END a_val[147]
  PIN a_val[148]
    DIRECTION INPUT ;
    USE SIGNAL ;
    PORT
      LAYER M5 ;
        RECT 55.2000 0.0000 55.2240 0.0840 ;
    END
  END a_val[148]
  PIN a_val[149]
    DIRECTION INPUT ;
    USE SIGNAL ;
    PORT
      LAYER M3 ;
        RECT 55.0080 0.0000 55.0260 0.0380 ;
    END
  END a_val[149]
  PIN a_val[14]
    DIRECTION INPUT ;
    USE SIGNAL ;
    PORT
      LAYER M5 ;
        RECT 80.2560 0.0000 80.2800 0.0840 ;
    END
  END a_val[14]
  PIN a_val[150]
    DIRECTION INPUT ;
    USE SIGNAL ;
    PORT
      LAYER M5 ;
        RECT 54.8160 0.0000 54.8400 0.0840 ;
    END
  END a_val[150]
  PIN a_val[151]
    DIRECTION INPUT ;
    USE SIGNAL ;
    PORT
      LAYER M3 ;
        RECT 54.6480 0.0000 54.6660 0.0380 ;
    END
  END a_val[151]
  PIN a_val[152]
    DIRECTION INPUT ;
    USE SIGNAL ;
    PORT
      LAYER M5 ;
        RECT 54.4320 0.0000 54.4560 0.0840 ;
    END
  END a_val[152]
  PIN a_val[153]
    DIRECTION INPUT ;
    USE SIGNAL ;
    PORT
      LAYER M3 ;
        RECT 54.2880 0.0000 54.3060 0.0380 ;
    END
  END a_val[153]
  PIN a_val[154]
    DIRECTION INPUT ;
    USE SIGNAL ;
    PORT
      LAYER M5 ;
        RECT 54.0480 0.0000 54.0720 0.0840 ;
    END
  END a_val[154]
  PIN a_val[155]
    DIRECTION INPUT ;
    USE SIGNAL ;
    PORT
      LAYER M3 ;
        RECT 53.8560 0.0000 53.8740 0.0380 ;
    END
  END a_val[155]
  PIN a_val[156]
    DIRECTION INPUT ;
    USE SIGNAL ;
    PORT
      LAYER M5 ;
        RECT 53.6640 0.0000 53.6880 0.0840 ;
    END
  END a_val[156]
  PIN a_val[157]
    DIRECTION INPUT ;
    USE SIGNAL ;
    PORT
      LAYER M3 ;
        RECT 53.4960 0.0000 53.5140 0.0380 ;
    END
  END a_val[157]
  PIN a_val[158]
    DIRECTION INPUT ;
    USE SIGNAL ;
    PORT
      LAYER M5 ;
        RECT 53.2800 0.0000 53.3040 0.0840 ;
    END
  END a_val[158]
  PIN a_val[159]
    DIRECTION INPUT ;
    USE SIGNAL ;
    PORT
      LAYER M3 ;
        RECT 53.1360 0.0000 53.1540 0.0380 ;
    END
  END a_val[159]
  PIN a_val[15]
    DIRECTION INPUT ;
    USE SIGNAL ;
    PORT
      LAYER M3 ;
        RECT 80.1360 0.0000 80.1540 0.0380 ;
    END
  END a_val[15]
  PIN a_val[160]
    DIRECTION INPUT ;
    USE SIGNAL ;
    PORT
      LAYER M5 ;
        RECT 52.8960 0.0000 52.9200 0.0840 ;
    END
  END a_val[160]
  PIN a_val[161]
    DIRECTION INPUT ;
    USE SIGNAL ;
    PORT
      LAYER M3 ;
        RECT 52.7760 0.0000 52.7940 0.0380 ;
    END
  END a_val[161]
  PIN a_val[162]
    DIRECTION INPUT ;
    USE SIGNAL ;
    PORT
      LAYER M5 ;
        RECT 52.6080 0.0000 52.6320 0.0840 ;
    END
  END a_val[162]
  PIN a_val[163]
    DIRECTION INPUT ;
    USE SIGNAL ;
    PORT
      LAYER M3 ;
        RECT 52.3440 0.0000 52.3620 0.0380 ;
    END
  END a_val[163]
  PIN a_val[164]
    DIRECTION INPUT ;
    USE SIGNAL ;
    PORT
      LAYER M5 ;
        RECT 52.2240 0.0000 52.2480 0.0840 ;
    END
  END a_val[164]
  PIN a_val[165]
    DIRECTION INPUT ;
    USE SIGNAL ;
    PORT
      LAYER M3 ;
        RECT 51.9840 0.0000 52.0020 0.0380 ;
    END
  END a_val[165]
  PIN a_val[166]
    DIRECTION INPUT ;
    USE SIGNAL ;
    PORT
      LAYER M5 ;
        RECT 51.8400 0.0000 51.8640 0.0840 ;
    END
  END a_val[166]
  PIN a_val[167]
    DIRECTION INPUT ;
    USE SIGNAL ;
    PORT
      LAYER M3 ;
        RECT 51.6240 0.0000 51.6420 0.0380 ;
    END
  END a_val[167]
  PIN a_val[168]
    DIRECTION INPUT ;
    USE SIGNAL ;
    PORT
      LAYER M5 ;
        RECT 51.4560 0.0000 51.4800 0.0840 ;
    END
  END a_val[168]
  PIN a_val[169]
    DIRECTION INPUT ;
    USE SIGNAL ;
    PORT
      LAYER M3 ;
        RECT 51.2640 0.0000 51.2820 0.0380 ;
    END
  END a_val[169]
  PIN a_val[16]
    DIRECTION INPUT ;
    USE SIGNAL ;
    PORT
      LAYER M5 ;
        RECT 79.9680 0.0000 79.9920 0.0840 ;
    END
  END a_val[16]
  PIN a_val[170]
    DIRECTION INPUT ;
    USE SIGNAL ;
    PORT
      LAYER M5 ;
        RECT 51.0720 0.0000 51.0960 0.0840 ;
    END
  END a_val[170]
  PIN a_val[171]
    DIRECTION INPUT ;
    USE SIGNAL ;
    PORT
      LAYER M3 ;
        RECT 50.9040 0.0000 50.9220 0.0380 ;
    END
  END a_val[171]
  PIN a_val[172]
    DIRECTION INPUT ;
    USE SIGNAL ;
    PORT
      LAYER M5 ;
        RECT 50.6880 0.0000 50.7120 0.0840 ;
    END
  END a_val[172]
  PIN a_val[173]
    DIRECTION INPUT ;
    USE SIGNAL ;
    PORT
      LAYER M3 ;
        RECT 50.4720 0.0000 50.4900 0.0380 ;
    END
  END a_val[173]
  PIN a_val[174]
    DIRECTION INPUT ;
    USE SIGNAL ;
    PORT
      LAYER M5 ;
        RECT 50.3040 0.0000 50.3280 0.0840 ;
    END
  END a_val[174]
  PIN a_val[175]
    DIRECTION INPUT ;
    USE SIGNAL ;
    PORT
      LAYER M3 ;
        RECT 50.1120 0.0000 50.1300 0.0380 ;
    END
  END a_val[175]
  PIN a_val[176]
    DIRECTION INPUT ;
    USE SIGNAL ;
    PORT
      LAYER M5 ;
        RECT 49.9200 0.0000 49.9440 0.0840 ;
    END
  END a_val[176]
  PIN a_val[177]
    DIRECTION INPUT ;
    USE SIGNAL ;
    PORT
      LAYER M3 ;
        RECT 49.7520 0.0000 49.7700 0.0380 ;
    END
  END a_val[177]
  PIN a_val[178]
    DIRECTION INPUT ;
    USE SIGNAL ;
    PORT
      LAYER M5 ;
        RECT 49.5360 0.0000 49.5600 0.0840 ;
    END
  END a_val[178]
  PIN a_val[179]
    DIRECTION INPUT ;
    USE SIGNAL ;
    PORT
      LAYER M3 ;
        RECT 49.3920 0.0000 49.4100 0.0380 ;
    END
  END a_val[179]
  PIN a_val[17]
    DIRECTION INPUT ;
    USE SIGNAL ;
    PORT
      LAYER M3 ;
        RECT 79.7040 0.0000 79.7220 0.0380 ;
    END
  END a_val[17]
  PIN a_val[180]
    DIRECTION INPUT ;
    USE SIGNAL ;
    PORT
      LAYER M5 ;
        RECT 49.1520 0.0000 49.1760 0.0840 ;
    END
  END a_val[180]
  PIN a_val[181]
    DIRECTION INPUT ;
    USE SIGNAL ;
    PORT
      LAYER M3 ;
        RECT 49.0320 0.0000 49.0500 0.0380 ;
    END
  END a_val[181]
  PIN a_val[182]
    DIRECTION INPUT ;
    USE SIGNAL ;
    PORT
      LAYER M5 ;
        RECT 48.7680 0.0000 48.7920 0.0840 ;
    END
  END a_val[182]
  PIN a_val[183]
    DIRECTION INPUT ;
    USE SIGNAL ;
    PORT
      LAYER M3 ;
        RECT 48.6000 0.0000 48.6180 0.0380 ;
    END
  END a_val[183]
  PIN a_val[184]
    DIRECTION INPUT ;
    USE SIGNAL ;
    PORT
      LAYER M5 ;
        RECT 48.4800 0.0000 48.5040 0.0840 ;
    END
  END a_val[184]
  PIN a_val[185]
    DIRECTION INPUT ;
    USE SIGNAL ;
    PORT
      LAYER M3 ;
        RECT 48.2400 0.0000 48.2580 0.0380 ;
    END
  END a_val[185]
  PIN a_val[186]
    DIRECTION INPUT ;
    USE SIGNAL ;
    PORT
      LAYER M5 ;
        RECT 48.0960 0.0000 48.1200 0.0840 ;
    END
  END a_val[186]
  PIN a_val[187]
    DIRECTION INPUT ;
    USE SIGNAL ;
    PORT
      LAYER M3 ;
        RECT 47.8800 0.0000 47.8980 0.0380 ;
    END
  END a_val[187]
  PIN a_val[188]
    DIRECTION INPUT ;
    USE SIGNAL ;
    PORT
      LAYER M5 ;
        RECT 47.7120 0.0000 47.7360 0.0840 ;
    END
  END a_val[188]
  PIN a_val[189]
    DIRECTION INPUT ;
    USE SIGNAL ;
    PORT
      LAYER M3 ;
        RECT 47.5200 0.0000 47.5380 0.0380 ;
    END
  END a_val[189]
  PIN a_val[18]
    DIRECTION INPUT ;
    USE SIGNAL ;
    PORT
      LAYER M5 ;
        RECT 79.5840 0.0000 79.6080 0.0840 ;
    END
  END a_val[18]
  PIN a_val[190]
    DIRECTION INPUT ;
    USE SIGNAL ;
    PORT
      LAYER M5 ;
        RECT 47.3280 0.0000 47.3520 0.0840 ;
    END
  END a_val[190]
  PIN a_val[191]
    DIRECTION INPUT ;
    USE SIGNAL ;
    PORT
      LAYER M3 ;
        RECT 47.1600 0.0000 47.1780 0.0380 ;
    END
  END a_val[191]
  PIN a_val[192]
    DIRECTION INPUT ;
    USE SIGNAL ;
    PORT
      LAYER M5 ;
        RECT 46.9440 0.0000 46.9680 0.0840 ;
    END
  END a_val[192]
  PIN a_val[193]
    DIRECTION INPUT ;
    USE SIGNAL ;
    PORT
      LAYER M3 ;
        RECT 46.7280 0.0000 46.7460 0.0380 ;
    END
  END a_val[193]
  PIN a_val[194]
    DIRECTION INPUT ;
    USE SIGNAL ;
    PORT
      LAYER M5 ;
        RECT 46.5600 0.0000 46.5840 0.0840 ;
    END
  END a_val[194]
  PIN a_val[195]
    DIRECTION INPUT ;
    USE SIGNAL ;
    PORT
      LAYER M3 ;
        RECT 46.3680 0.0000 46.3860 0.0380 ;
    END
  END a_val[195]
  PIN a_val[196]
    DIRECTION INPUT ;
    USE SIGNAL ;
    PORT
      LAYER M5 ;
        RECT 46.1760 0.0000 46.2000 0.0840 ;
    END
  END a_val[196]
  PIN a_val[197]
    DIRECTION INPUT ;
    USE SIGNAL ;
    PORT
      LAYER M3 ;
        RECT 46.0080 0.0000 46.0260 0.0380 ;
    END
  END a_val[197]
  PIN a_val[198]
    DIRECTION INPUT ;
    USE SIGNAL ;
    PORT
      LAYER M5 ;
        RECT 45.7920 0.0000 45.8160 0.0840 ;
    END
  END a_val[198]
  PIN a_val[199]
    DIRECTION INPUT ;
    USE SIGNAL ;
    PORT
      LAYER M3 ;
        RECT 45.6480 0.0000 45.6660 0.0380 ;
    END
  END a_val[199]
  PIN a_val[19]
    DIRECTION INPUT ;
    USE SIGNAL ;
    PORT
      LAYER M3 ;
        RECT 79.3440 0.0000 79.3620 0.0380 ;
    END
  END a_val[19]
  PIN a_val[1]
    DIRECTION INPUT ;
    USE SIGNAL ;
    PORT
      LAYER M3 ;
        RECT 82.7280 0.0000 82.7460 0.0380 ;
    END
  END a_val[1]
  PIN a_val[200]
    DIRECTION INPUT ;
    USE SIGNAL ;
    PORT
      LAYER M5 ;
        RECT 45.4080 0.0000 45.4320 0.0840 ;
    END
  END a_val[200]
  PIN a_val[201]
    DIRECTION INPUT ;
    USE SIGNAL ;
    PORT
      LAYER M3 ;
        RECT 45.2880 0.0000 45.3060 0.0380 ;
    END
  END a_val[201]
  PIN a_val[202]
    DIRECTION INPUT ;
    USE SIGNAL ;
    PORT
      LAYER M5 ;
        RECT 45.0240 0.0000 45.0480 0.0840 ;
    END
  END a_val[202]
  PIN a_val[203]
    DIRECTION INPUT ;
    USE SIGNAL ;
    PORT
      LAYER M3 ;
        RECT 44.8560 0.0000 44.8740 0.0380 ;
    END
  END a_val[203]
  PIN a_val[204]
    DIRECTION INPUT ;
    USE SIGNAL ;
    PORT
      LAYER M5 ;
        RECT 44.7360 0.0000 44.7600 0.0840 ;
    END
  END a_val[204]
  PIN a_val[205]
    DIRECTION INPUT ;
    USE SIGNAL ;
    PORT
      LAYER M3 ;
        RECT 44.4960 0.0000 44.5140 0.0380 ;
    END
  END a_val[205]
  PIN a_val[206]
    DIRECTION INPUT ;
    USE SIGNAL ;
    PORT
      LAYER M5 ;
        RECT 44.3520 0.0000 44.3760 0.0840 ;
    END
  END a_val[206]
  PIN a_val[207]
    DIRECTION INPUT ;
    USE SIGNAL ;
    PORT
      LAYER M3 ;
        RECT 44.1360 0.0000 44.1540 0.0380 ;
    END
  END a_val[207]
  PIN a_val[208]
    DIRECTION INPUT ;
    USE SIGNAL ;
    PORT
      LAYER M5 ;
        RECT 43.9680 0.0000 43.9920 0.0840 ;
    END
  END a_val[208]
  PIN a_val[209]
    DIRECTION INPUT ;
    USE SIGNAL ;
    PORT
      LAYER M3 ;
        RECT 43.7760 0.0000 43.7940 0.0380 ;
    END
  END a_val[209]
  PIN a_val[20]
    DIRECTION INPUT ;
    USE SIGNAL ;
    PORT
      LAYER M5 ;
        RECT 79.2000 0.0000 79.2240 0.0840 ;
    END
  END a_val[20]
  PIN a_val[210]
    DIRECTION INPUT ;
    USE SIGNAL ;
    PORT
      LAYER M5 ;
        RECT 43.5840 0.0000 43.6080 0.0840 ;
    END
  END a_val[210]
  PIN a_val[211]
    DIRECTION INPUT ;
    USE SIGNAL ;
    PORT
      LAYER M3 ;
        RECT 43.4160 0.0000 43.4340 0.0380 ;
    END
  END a_val[211]
  PIN a_val[212]
    DIRECTION INPUT ;
    USE SIGNAL ;
    PORT
      LAYER M5 ;
        RECT 43.2000 0.0000 43.2240 0.0840 ;
    END
  END a_val[212]
  PIN a_val[213]
    DIRECTION INPUT ;
    USE SIGNAL ;
    PORT
      LAYER M3 ;
        RECT 42.9840 0.0000 43.0020 0.0380 ;
    END
  END a_val[213]
  PIN a_val[214]
    DIRECTION INPUT ;
    USE SIGNAL ;
    PORT
      LAYER M5 ;
        RECT 42.8160 0.0000 42.8400 0.0840 ;
    END
  END a_val[214]
  PIN a_val[215]
    DIRECTION INPUT ;
    USE SIGNAL ;
    PORT
      LAYER M3 ;
        RECT 42.6240 0.0000 42.6420 0.0380 ;
    END
  END a_val[215]
  PIN a_val[216]
    DIRECTION INPUT ;
    USE SIGNAL ;
    PORT
      LAYER M5 ;
        RECT 42.4320 0.0000 42.4560 0.0840 ;
    END
  END a_val[216]
  PIN a_val[217]
    DIRECTION INPUT ;
    USE SIGNAL ;
    PORT
      LAYER M3 ;
        RECT 42.2640 0.0000 42.2820 0.0380 ;
    END
  END a_val[217]
  PIN a_val[218]
    DIRECTION INPUT ;
    USE SIGNAL ;
    PORT
      LAYER M5 ;
        RECT 42.0480 0.0000 42.0720 0.0840 ;
    END
  END a_val[218]
  PIN a_val[219]
    DIRECTION INPUT ;
    USE SIGNAL ;
    PORT
      LAYER M3 ;
        RECT 41.9040 0.0000 41.9220 0.0380 ;
    END
  END a_val[219]
  PIN a_val[21]
    DIRECTION INPUT ;
    USE SIGNAL ;
    PORT
      LAYER M3 ;
        RECT 78.9840 0.0000 79.0020 0.0380 ;
    END
  END a_val[21]
  PIN a_val[220]
    DIRECTION INPUT ;
    USE SIGNAL ;
    PORT
      LAYER M5 ;
        RECT 41.6640 0.0000 41.6880 0.0840 ;
    END
  END a_val[220]
  PIN a_val[221]
    DIRECTION INPUT ;
    USE SIGNAL ;
    PORT
      LAYER M3 ;
        RECT 41.5440 0.0000 41.5620 0.0380 ;
    END
  END a_val[221]
  PIN a_val[222]
    DIRECTION INPUT ;
    USE SIGNAL ;
    PORT
      LAYER M5 ;
        RECT 41.2800 0.0000 41.3040 0.0840 ;
    END
  END a_val[222]
  PIN a_val[223]
    DIRECTION INPUT ;
    USE SIGNAL ;
    PORT
      LAYER M3 ;
        RECT 41.1120 0.0000 41.1300 0.0380 ;
    END
  END a_val[223]
  PIN a_val[224]
    DIRECTION INPUT ;
    USE SIGNAL ;
    PORT
      LAYER M5 ;
        RECT 40.9920 0.0000 41.0160 0.0840 ;
    END
  END a_val[224]
  PIN a_val[225]
    DIRECTION INPUT ;
    USE SIGNAL ;
    PORT
      LAYER M3 ;
        RECT 40.7520 0.0000 40.7700 0.0380 ;
    END
  END a_val[225]
  PIN a_val[226]
    DIRECTION INPUT ;
    USE SIGNAL ;
    PORT
      LAYER M5 ;
        RECT 40.6080 0.0000 40.6320 0.0840 ;
    END
  END a_val[226]
  PIN a_val[227]
    DIRECTION INPUT ;
    USE SIGNAL ;
    PORT
      LAYER M3 ;
        RECT 40.3920 0.0000 40.4100 0.0380 ;
    END
  END a_val[227]
  PIN a_val[228]
    DIRECTION INPUT ;
    USE SIGNAL ;
    PORT
      LAYER M5 ;
        RECT 40.2240 0.0000 40.2480 0.0840 ;
    END
  END a_val[228]
  PIN a_val[229]
    DIRECTION INPUT ;
    USE SIGNAL ;
    PORT
      LAYER M3 ;
        RECT 40.0320 0.0000 40.0500 0.0380 ;
    END
  END a_val[229]
  PIN a_val[22]
    DIRECTION INPUT ;
    USE SIGNAL ;
    PORT
      LAYER M5 ;
        RECT 78.8160 0.0000 78.8400 0.0840 ;
    END
  END a_val[22]
  PIN a_val[230]
    DIRECTION INPUT ;
    USE SIGNAL ;
    PORT
      LAYER M5 ;
        RECT 39.8400 0.0000 39.8640 0.0840 ;
    END
  END a_val[230]
  PIN a_val[231]
    DIRECTION INPUT ;
    USE SIGNAL ;
    PORT
      LAYER M3 ;
        RECT 39.6000 0.0000 39.6180 0.0380 ;
    END
  END a_val[231]
  PIN a_val[232]
    DIRECTION INPUT ;
    USE SIGNAL ;
    PORT
      LAYER M5 ;
        RECT 39.4560 0.0000 39.4800 0.0840 ;
    END
  END a_val[232]
  PIN a_val[233]
    DIRECTION INPUT ;
    USE SIGNAL ;
    PORT
      LAYER M3 ;
        RECT 39.2400 0.0000 39.2580 0.0380 ;
    END
  END a_val[233]
  PIN a_val[234]
    DIRECTION INPUT ;
    USE SIGNAL ;
    PORT
      LAYER M5 ;
        RECT 39.0720 0.0000 39.0960 0.0840 ;
    END
  END a_val[234]
  PIN a_val[235]
    DIRECTION INPUT ;
    USE SIGNAL ;
    PORT
      LAYER M3 ;
        RECT 38.8800 0.0000 38.8980 0.0380 ;
    END
  END a_val[235]
  PIN a_val[236]
    DIRECTION INPUT ;
    USE SIGNAL ;
    PORT
      LAYER M5 ;
        RECT 38.6880 0.0000 38.7120 0.0840 ;
    END
  END a_val[236]
  PIN a_val[237]
    DIRECTION INPUT ;
    USE SIGNAL ;
    PORT
      LAYER M3 ;
        RECT 38.5200 0.0000 38.5380 0.0380 ;
    END
  END a_val[237]
  PIN a_val[238]
    DIRECTION INPUT ;
    USE SIGNAL ;
    PORT
      LAYER M5 ;
        RECT 38.3040 0.0000 38.3280 0.0840 ;
    END
  END a_val[238]
  PIN a_val[239]
    DIRECTION INPUT ;
    USE SIGNAL ;
    PORT
      LAYER M3 ;
        RECT 38.1600 0.0000 38.1780 0.0380 ;
    END
  END a_val[239]
  PIN a_val[23]
    DIRECTION INPUT ;
    USE SIGNAL ;
    PORT
      LAYER M3 ;
        RECT 78.6240 0.0000 78.6420 0.0380 ;
    END
  END a_val[23]
  PIN a_val[240]
    DIRECTION INPUT ;
    USE SIGNAL ;
    PORT
      LAYER M5 ;
        RECT 37.9200 0.0000 37.9440 0.0840 ;
    END
  END a_val[240]
  PIN a_val[241]
    DIRECTION INPUT ;
    USE SIGNAL ;
    PORT
      LAYER M3 ;
        RECT 37.7280 0.0000 37.7460 0.0380 ;
    END
  END a_val[241]
  PIN a_val[242]
    DIRECTION INPUT ;
    USE SIGNAL ;
    PORT
      LAYER M5 ;
        RECT 37.5360 0.0000 37.5600 0.0840 ;
    END
  END a_val[242]
  PIN a_val[243]
    DIRECTION INPUT ;
    USE SIGNAL ;
    PORT
      LAYER M3 ;
        RECT 37.3680 0.0000 37.3860 0.0380 ;
    END
  END a_val[243]
  PIN a_val[244]
    DIRECTION INPUT ;
    USE SIGNAL ;
    PORT
      LAYER M5 ;
        RECT 37.1520 0.0000 37.1760 0.0840 ;
    END
  END a_val[244]
  PIN a_val[245]
    DIRECTION INPUT ;
    USE SIGNAL ;
    PORT
      LAYER M3 ;
        RECT 37.0080 0.0000 37.0260 0.0380 ;
    END
  END a_val[245]
  PIN a_val[246]
    DIRECTION INPUT ;
    USE SIGNAL ;
    PORT
      LAYER M5 ;
        RECT 36.8640 0.0000 36.8880 0.0840 ;
    END
  END a_val[246]
  PIN a_val[247]
    DIRECTION INPUT ;
    USE SIGNAL ;
    PORT
      LAYER M3 ;
        RECT 36.6480 0.0000 36.6660 0.0380 ;
    END
  END a_val[247]
  PIN a_val[248]
    DIRECTION INPUT ;
    USE SIGNAL ;
    PORT
      LAYER M5 ;
        RECT 36.4800 0.0000 36.5040 0.0840 ;
    END
  END a_val[248]
  PIN a_val[249]
    DIRECTION INPUT ;
    USE SIGNAL ;
    PORT
      LAYER M3 ;
        RECT 36.2880 0.0000 36.3060 0.0380 ;
    END
  END a_val[249]
  PIN a_val[24]
    DIRECTION INPUT ;
    USE SIGNAL ;
    PORT
      LAYER M5 ;
        RECT 78.4320 0.0000 78.4560 0.0840 ;
    END
  END a_val[24]
  PIN a_val[250]
    DIRECTION INPUT ;
    USE SIGNAL ;
    PORT
      LAYER M5 ;
        RECT 36.0960 0.0000 36.1200 0.0840 ;
    END
  END a_val[250]
  PIN a_val[251]
    DIRECTION INPUT ;
    USE SIGNAL ;
    PORT
      LAYER M3 ;
        RECT 35.8560 0.0000 35.8740 0.0380 ;
    END
  END a_val[251]
  PIN a_val[252]
    DIRECTION INPUT ;
    USE SIGNAL ;
    PORT
      LAYER M5 ;
        RECT 35.7120 0.0000 35.7360 0.0840 ;
    END
  END a_val[252]
  PIN a_val[253]
    DIRECTION INPUT ;
    USE SIGNAL ;
    PORT
      LAYER M3 ;
        RECT 35.4960 0.0000 35.5140 0.0380 ;
    END
  END a_val[253]
  PIN a_val[254]
    DIRECTION INPUT ;
    USE SIGNAL ;
    PORT
      LAYER M5 ;
        RECT 35.3280 0.0000 35.3520 0.0840 ;
    END
  END a_val[254]
  PIN a_val[255]
    DIRECTION INPUT ;
    USE SIGNAL ;
    PORT
      LAYER M3 ;
        RECT 35.1360 0.0000 35.1540 0.0380 ;
    END
  END a_val[255]
  PIN a_val[25]
    DIRECTION INPUT ;
    USE SIGNAL ;
    PORT
      LAYER M3 ;
        RECT 78.2640 0.0000 78.2820 0.0380 ;
    END
  END a_val[25]
  PIN a_val[26]
    DIRECTION INPUT ;
    USE SIGNAL ;
    PORT
      LAYER M5 ;
        RECT 78.0480 0.0000 78.0720 0.0840 ;
    END
  END a_val[26]
  PIN a_val[27]
    DIRECTION INPUT ;
    USE SIGNAL ;
    PORT
      LAYER M3 ;
        RECT 77.8320 0.0000 77.8500 0.0380 ;
    END
  END a_val[27]
  PIN a_val[28]
    DIRECTION INPUT ;
    USE SIGNAL ;
    PORT
      LAYER M5 ;
        RECT 77.6640 0.0000 77.6880 0.0840 ;
    END
  END a_val[28]
  PIN a_val[29]
    DIRECTION INPUT ;
    USE SIGNAL ;
    PORT
      LAYER M3 ;
        RECT 77.4720 0.0000 77.4900 0.0380 ;
    END
  END a_val[29]
  PIN a_val[2]
    DIRECTION INPUT ;
    USE SIGNAL ;
    PORT
      LAYER M5 ;
        RECT 82.5600 0.0000 82.5840 0.0840 ;
    END
  END a_val[2]
  PIN a_val[30]
    DIRECTION INPUT ;
    USE SIGNAL ;
    PORT
      LAYER M5 ;
        RECT 77.2800 0.0000 77.3040 0.0840 ;
    END
  END a_val[30]
  PIN a_val[31]
    DIRECTION INPUT ;
    USE SIGNAL ;
    PORT
      LAYER M3 ;
        RECT 77.1120 0.0000 77.1300 0.0380 ;
    END
  END a_val[31]
  PIN a_val[32]
    DIRECTION INPUT ;
    USE SIGNAL ;
    PORT
      LAYER M5 ;
        RECT 76.8960 0.0000 76.9200 0.0840 ;
    END
  END a_val[32]
  PIN a_val[33]
    DIRECTION INPUT ;
    USE SIGNAL ;
    PORT
      LAYER M3 ;
        RECT 76.7520 0.0000 76.7700 0.0380 ;
    END
  END a_val[33]
  PIN a_val[34]
    DIRECTION INPUT ;
    USE SIGNAL ;
    PORT
      LAYER M5 ;
        RECT 76.5120 0.0000 76.5360 0.0840 ;
    END
  END a_val[34]
  PIN a_val[35]
    DIRECTION INPUT ;
    USE SIGNAL ;
    PORT
      LAYER M3 ;
        RECT 76.3920 0.0000 76.4100 0.0380 ;
    END
  END a_val[35]
  PIN a_val[36]
    DIRECTION INPUT ;
    USE SIGNAL ;
    PORT
      LAYER M5 ;
        RECT 76.1280 0.0000 76.1520 0.0840 ;
    END
  END a_val[36]
  PIN a_val[37]
    DIRECTION INPUT ;
    USE SIGNAL ;
    PORT
      LAYER M3 ;
        RECT 75.9600 0.0000 75.9780 0.0380 ;
    END
  END a_val[37]
  PIN a_val[38]
    DIRECTION INPUT ;
    USE SIGNAL ;
    PORT
      LAYER M5 ;
        RECT 75.8400 0.0000 75.8640 0.0840 ;
    END
  END a_val[38]
  PIN a_val[39]
    DIRECTION INPUT ;
    USE SIGNAL ;
    PORT
      LAYER M3 ;
        RECT 75.6000 0.0000 75.6180 0.0380 ;
    END
  END a_val[39]
  PIN a_val[3]
    DIRECTION INPUT ;
    USE SIGNAL ;
    PORT
      LAYER M3 ;
        RECT 82.3680 0.0000 82.3860 0.0380 ;
    END
  END a_val[3]
  PIN a_val[40]
    DIRECTION INPUT ;
    USE SIGNAL ;
    PORT
      LAYER M5 ;
        RECT 75.4560 0.0000 75.4800 0.0840 ;
    END
  END a_val[40]
  PIN a_val[41]
    DIRECTION INPUT ;
    USE SIGNAL ;
    PORT
      LAYER M3 ;
        RECT 75.2400 0.0000 75.2580 0.0380 ;
    END
  END a_val[41]
  PIN a_val[42]
    DIRECTION INPUT ;
    USE SIGNAL ;
    PORT
      LAYER M5 ;
        RECT 75.0720 0.0000 75.0960 0.0840 ;
    END
  END a_val[42]
  PIN a_val[43]
    DIRECTION INPUT ;
    USE SIGNAL ;
    PORT
      LAYER M3 ;
        RECT 74.8800 0.0000 74.8980 0.0380 ;
    END
  END a_val[43]
  PIN a_val[44]
    DIRECTION INPUT ;
    USE SIGNAL ;
    PORT
      LAYER M5 ;
        RECT 74.6880 0.0000 74.7120 0.0840 ;
    END
  END a_val[44]
  PIN a_val[45]
    DIRECTION INPUT ;
    USE SIGNAL ;
    PORT
      LAYER M3 ;
        RECT 74.5200 0.0000 74.5380 0.0380 ;
    END
  END a_val[45]
  PIN a_val[46]
    DIRECTION INPUT ;
    USE SIGNAL ;
    PORT
      LAYER M5 ;
        RECT 74.3040 0.0000 74.3280 0.0840 ;
    END
  END a_val[46]
  PIN a_val[47]
    DIRECTION INPUT ;
    USE SIGNAL ;
    PORT
      LAYER M3 ;
        RECT 74.0880 0.0000 74.1060 0.0380 ;
    END
  END a_val[47]
  PIN a_val[48]
    DIRECTION INPUT ;
    USE SIGNAL ;
    PORT
      LAYER M5 ;
        RECT 73.9200 0.0000 73.9440 0.0840 ;
    END
  END a_val[48]
  PIN a_val[49]
    DIRECTION INPUT ;
    USE SIGNAL ;
    PORT
      LAYER M3 ;
        RECT 73.7280 0.0000 73.7460 0.0380 ;
    END
  END a_val[49]
  PIN a_val[4]
    DIRECTION INPUT ;
    USE SIGNAL ;
    PORT
      LAYER M5 ;
        RECT 82.1760 0.0000 82.2000 0.0840 ;
    END
  END a_val[4]
  PIN a_val[50]
    DIRECTION INPUT ;
    USE SIGNAL ;
    PORT
      LAYER M5 ;
        RECT 73.5360 0.0000 73.5600 0.0840 ;
    END
  END a_val[50]
  PIN a_val[51]
    DIRECTION INPUT ;
    USE SIGNAL ;
    PORT
      LAYER M3 ;
        RECT 73.3680 0.0000 73.3860 0.0380 ;
    END
  END a_val[51]
  PIN a_val[52]
    DIRECTION INPUT ;
    USE SIGNAL ;
    PORT
      LAYER M5 ;
        RECT 73.1520 0.0000 73.1760 0.0840 ;
    END
  END a_val[52]
  PIN a_val[53]
    DIRECTION INPUT ;
    USE SIGNAL ;
    PORT
      LAYER M3 ;
        RECT 73.0080 0.0000 73.0260 0.0380 ;
    END
  END a_val[53]
  PIN a_val[54]
    DIRECTION INPUT ;
    USE SIGNAL ;
    PORT
      LAYER M5 ;
        RECT 72.7680 0.0000 72.7920 0.0840 ;
    END
  END a_val[54]
  PIN a_val[55]
    DIRECTION INPUT ;
    USE SIGNAL ;
    PORT
      LAYER M3 ;
        RECT 72.6480 0.0000 72.6660 0.0380 ;
    END
  END a_val[55]
  PIN a_val[56]
    DIRECTION INPUT ;
    USE SIGNAL ;
    PORT
      LAYER M5 ;
        RECT 72.3840 0.0000 72.4080 0.0840 ;
    END
  END a_val[56]
  PIN a_val[57]
    DIRECTION INPUT ;
    USE SIGNAL ;
    PORT
      LAYER M3 ;
        RECT 72.2160 0.0000 72.2340 0.0380 ;
    END
  END a_val[57]
  PIN a_val[58]
    DIRECTION INPUT ;
    USE SIGNAL ;
    PORT
      LAYER M5 ;
        RECT 72.0960 0.0000 72.1200 0.0840 ;
    END
  END a_val[58]
  PIN a_val[59]
    DIRECTION INPUT ;
    USE SIGNAL ;
    PORT
      LAYER M3 ;
        RECT 71.8560 0.0000 71.8740 0.0380 ;
    END
  END a_val[59]
  PIN a_val[5]
    DIRECTION INPUT ;
    USE SIGNAL ;
    PORT
      LAYER M3 ;
        RECT 82.0080 0.0000 82.0260 0.0380 ;
    END
  END a_val[5]
  PIN a_val[60]
    DIRECTION INPUT ;
    USE SIGNAL ;
    PORT
      LAYER M5 ;
        RECT 71.7120 0.0000 71.7360 0.0840 ;
    END
  END a_val[60]
  PIN a_val[61]
    DIRECTION INPUT ;
    USE SIGNAL ;
    PORT
      LAYER M3 ;
        RECT 71.4960 0.0000 71.5140 0.0380 ;
    END
  END a_val[61]
  PIN a_val[62]
    DIRECTION INPUT ;
    USE SIGNAL ;
    PORT
      LAYER M5 ;
        RECT 71.3280 0.0000 71.3520 0.0840 ;
    END
  END a_val[62]
  PIN a_val[63]
    DIRECTION INPUT ;
    USE SIGNAL ;
    PORT
      LAYER M3 ;
        RECT 71.1360 0.0000 71.1540 0.0380 ;
    END
  END a_val[63]
  PIN a_val[64]
    DIRECTION INPUT ;
    USE SIGNAL ;
    PORT
      LAYER M5 ;
        RECT 70.9440 0.0000 70.9680 0.0840 ;
    END
  END a_val[64]
  PIN a_val[65]
    DIRECTION INPUT ;
    USE SIGNAL ;
    PORT
      LAYER M3 ;
        RECT 70.7760 0.0000 70.7940 0.0380 ;
    END
  END a_val[65]
  PIN a_val[66]
    DIRECTION INPUT ;
    USE SIGNAL ;
    PORT
      LAYER M5 ;
        RECT 70.5600 0.0000 70.5840 0.0840 ;
    END
  END a_val[66]
  PIN a_val[67]
    DIRECTION INPUT ;
    USE SIGNAL ;
    PORT
      LAYER M3 ;
        RECT 70.3440 0.0000 70.3620 0.0380 ;
    END
  END a_val[67]
  PIN a_val[68]
    DIRECTION INPUT ;
    USE SIGNAL ;
    PORT
      LAYER M5 ;
        RECT 70.1760 0.0000 70.2000 0.0840 ;
    END
  END a_val[68]
  PIN a_val[69]
    DIRECTION INPUT ;
    USE SIGNAL ;
    PORT
      LAYER M3 ;
        RECT 69.9840 0.0000 70.0020 0.0380 ;
    END
  END a_val[69]
  PIN a_val[6]
    DIRECTION INPUT ;
    USE SIGNAL ;
    PORT
      LAYER M5 ;
        RECT 81.7920 0.0000 81.8160 0.0840 ;
    END
  END a_val[6]
  PIN a_val[70]
    DIRECTION INPUT ;
    USE SIGNAL ;
    PORT
      LAYER M5 ;
        RECT 69.7920 0.0000 69.8160 0.0840 ;
    END
  END a_val[70]
  PIN a_val[71]
    DIRECTION INPUT ;
    USE SIGNAL ;
    PORT
      LAYER M3 ;
        RECT 69.6240 0.0000 69.6420 0.0380 ;
    END
  END a_val[71]
  PIN a_val[72]
    DIRECTION INPUT ;
    USE SIGNAL ;
    PORT
      LAYER M5 ;
        RECT 69.4080 0.0000 69.4320 0.0840 ;
    END
  END a_val[72]
  PIN a_val[73]
    DIRECTION INPUT ;
    USE SIGNAL ;
    PORT
      LAYER M3 ;
        RECT 69.2640 0.0000 69.2820 0.0380 ;
    END
  END a_val[73]
  PIN a_val[74]
    DIRECTION INPUT ;
    USE SIGNAL ;
    PORT
      LAYER M5 ;
        RECT 69.0240 0.0000 69.0480 0.0840 ;
    END
  END a_val[74]
  PIN a_val[75]
    DIRECTION INPUT ;
    USE SIGNAL ;
    PORT
      LAYER M3 ;
        RECT 68.9040 0.0000 68.9220 0.0380 ;
    END
  END a_val[75]
  PIN a_val[76]
    DIRECTION INPUT ;
    USE SIGNAL ;
    PORT
      LAYER M5 ;
        RECT 68.6400 0.0000 68.6640 0.0840 ;
    END
  END a_val[76]
  PIN a_val[77]
    DIRECTION INPUT ;
    USE SIGNAL ;
    PORT
      LAYER M3 ;
        RECT 68.4720 0.0000 68.4900 0.0380 ;
    END
  END a_val[77]
  PIN a_val[78]
    DIRECTION INPUT ;
    USE SIGNAL ;
    PORT
      LAYER M5 ;
        RECT 68.3520 0.0000 68.3760 0.0840 ;
    END
  END a_val[78]
  PIN a_val[79]
    DIRECTION INPUT ;
    USE SIGNAL ;
    PORT
      LAYER M3 ;
        RECT 68.1120 0.0000 68.1300 0.0380 ;
    END
  END a_val[79]
  PIN a_val[7]
    DIRECTION INPUT ;
    USE SIGNAL ;
    PORT
      LAYER M3 ;
        RECT 81.6480 0.0000 81.6660 0.0380 ;
    END
  END a_val[7]
  PIN a_val[80]
    DIRECTION INPUT ;
    USE SIGNAL ;
    PORT
      LAYER M5 ;
        RECT 67.9680 0.0000 67.9920 0.0840 ;
    END
  END a_val[80]
  PIN a_val[81]
    DIRECTION INPUT ;
    USE SIGNAL ;
    PORT
      LAYER M3 ;
        RECT 67.7520 0.0000 67.7700 0.0380 ;
    END
  END a_val[81]
  PIN a_val[82]
    DIRECTION INPUT ;
    USE SIGNAL ;
    PORT
      LAYER M5 ;
        RECT 67.5840 0.0000 67.6080 0.0840 ;
    END
  END a_val[82]
  PIN a_val[83]
    DIRECTION INPUT ;
    USE SIGNAL ;
    PORT
      LAYER M3 ;
        RECT 67.3920 0.0000 67.4100 0.0380 ;
    END
  END a_val[83]
  PIN a_val[84]
    DIRECTION INPUT ;
    USE SIGNAL ;
    PORT
      LAYER M5 ;
        RECT 67.2000 0.0000 67.2240 0.0840 ;
    END
  END a_val[84]
  PIN a_val[85]
    DIRECTION INPUT ;
    USE SIGNAL ;
    PORT
      LAYER M3 ;
        RECT 66.9600 0.0000 66.9780 0.0380 ;
    END
  END a_val[85]
  PIN a_val[86]
    DIRECTION INPUT ;
    USE SIGNAL ;
    PORT
      LAYER M5 ;
        RECT 66.8160 0.0000 66.8400 0.0840 ;
    END
  END a_val[86]
  PIN a_val[87]
    DIRECTION INPUT ;
    USE SIGNAL ;
    PORT
      LAYER M3 ;
        RECT 66.6000 0.0000 66.6180 0.0380 ;
    END
  END a_val[87]
  PIN a_val[88]
    DIRECTION INPUT ;
    USE SIGNAL ;
    PORT
      LAYER M5 ;
        RECT 66.4320 0.0000 66.4560 0.0840 ;
    END
  END a_val[88]
  PIN a_val[89]
    DIRECTION INPUT ;
    USE SIGNAL ;
    PORT
      LAYER M3 ;
        RECT 66.2400 0.0000 66.2580 0.0380 ;
    END
  END a_val[89]
  PIN a_val[8]
    DIRECTION INPUT ;
    USE SIGNAL ;
    PORT
      LAYER M5 ;
        RECT 81.4080 0.0000 81.4320 0.0840 ;
    END
  END a_val[8]
  PIN a_val[90]
    DIRECTION INPUT ;
    USE SIGNAL ;
    PORT
      LAYER M5 ;
        RECT 66.0480 0.0000 66.0720 0.0840 ;
    END
  END a_val[90]
  PIN a_val[91]
    DIRECTION INPUT ;
    USE SIGNAL ;
    PORT
      LAYER M3 ;
        RECT 65.8800 0.0000 65.8980 0.0380 ;
    END
  END a_val[91]
  PIN a_val[92]
    DIRECTION INPUT ;
    USE SIGNAL ;
    PORT
      LAYER M5 ;
        RECT 65.6640 0.0000 65.6880 0.0840 ;
    END
  END a_val[92]
  PIN a_val[93]
    DIRECTION INPUT ;
    USE SIGNAL ;
    PORT
      LAYER M3 ;
        RECT 65.5200 0.0000 65.5380 0.0380 ;
    END
  END a_val[93]
  PIN a_val[94]
    DIRECTION INPUT ;
    USE SIGNAL ;
    PORT
      LAYER M5 ;
        RECT 65.2800 0.0000 65.3040 0.0840 ;
    END
  END a_val[94]
  PIN a_val[95]
    DIRECTION INPUT ;
    USE SIGNAL ;
    PORT
      LAYER M3 ;
        RECT 65.0880 0.0000 65.1060 0.0380 ;
    END
  END a_val[95]
  PIN a_val[96]
    DIRECTION INPUT ;
    USE SIGNAL ;
    PORT
      LAYER M5 ;
        RECT 64.8960 0.0000 64.9200 0.0840 ;
    END
  END a_val[96]
  PIN a_val[97]
    DIRECTION INPUT ;
    USE SIGNAL ;
    PORT
      LAYER M3 ;
        RECT 64.7280 0.0000 64.7460 0.0380 ;
    END
  END a_val[97]
  PIN a_val[98]
    DIRECTION INPUT ;
    USE SIGNAL ;
    PORT
      LAYER M5 ;
        RECT 64.5120 0.0000 64.5360 0.0840 ;
    END
  END a_val[98]
  PIN a_val[99]
    DIRECTION INPUT ;
    USE SIGNAL ;
    PORT
      LAYER M3 ;
        RECT 64.3680 0.0000 64.3860 0.0380 ;
    END
  END a_val[99]
  PIN a_val[9]
    DIRECTION INPUT ;
    USE SIGNAL ;
    PORT
      LAYER M3 ;
        RECT 81.2160 0.0000 81.2340 0.0380 ;
    END
  END a_val[9]
  PIN clk
    DIRECTION INPUT ;
    USE SIGNAL ;
    PORT
      LAYER M5 ;
        RECT 86.3040 0.0000 86.3280 0.0840 ;
    END
  END clk
  PIN fault
    DIRECTION OUTPUT ;
    USE SIGNAL ;
    PORT
      LAYER M3 ;
        RECT 4.3920 0.0000 4.4100 0.0380 ;
    END
  END fault
  PIN m_dd[0]
    DIRECTION OUTPUT ;
    USE SIGNAL ;
    PORT
      LAYER M4 ;
        RECT 172.7160 229.9200 172.8000 229.9440 ;
    END
  END m_dd[0]
  PIN m_dd[100]
    DIRECTION OUTPUT ;
    USE SIGNAL ;
    PORT
      LAYER M4 ;
        RECT 172.7160 317.2800 172.8000 317.3040 ;
    END
  END m_dd[100]
  PIN m_dd[101]
    DIRECTION OUTPUT ;
    USE SIGNAL ;
    PORT
      LAYER M4 ;
        RECT 172.7160 318.1440 172.8000 318.1680 ;
    END
  END m_dd[101]
  PIN m_dd[102]
    DIRECTION OUTPUT ;
    USE SIGNAL ;
    PORT
      LAYER M4 ;
        RECT 172.7160 319.0080 172.8000 319.0320 ;
    END
  END m_dd[102]
  PIN m_dd[103]
    DIRECTION OUTPUT ;
    USE SIGNAL ;
    PORT
      LAYER M4 ;
        RECT 172.7160 319.8720 172.8000 319.8960 ;
    END
  END m_dd[103]
  PIN m_dd[104]
    DIRECTION OUTPUT ;
    USE SIGNAL ;
    PORT
      LAYER M4 ;
        RECT 172.7160 320.7360 172.8000 320.7600 ;
    END
  END m_dd[104]
  PIN m_dd[105]
    DIRECTION OUTPUT ;
    USE SIGNAL ;
    PORT
      LAYER M4 ;
        RECT 172.7160 321.6000 172.8000 321.6240 ;
    END
  END m_dd[105]
  PIN m_dd[106]
    DIRECTION OUTPUT ;
    USE SIGNAL ;
    PORT
      LAYER M4 ;
        RECT 172.7160 322.4640 172.8000 322.4880 ;
    END
  END m_dd[106]
  PIN m_dd[107]
    DIRECTION OUTPUT ;
    USE SIGNAL ;
    PORT
      LAYER M4 ;
        RECT 172.7160 323.3280 172.8000 323.3520 ;
    END
  END m_dd[107]
  PIN m_dd[108]
    DIRECTION OUTPUT ;
    USE SIGNAL ;
    PORT
      LAYER M4 ;
        RECT 172.7160 324.2880 172.8000 324.3120 ;
    END
  END m_dd[108]
  PIN m_dd[109]
    DIRECTION OUTPUT ;
    USE SIGNAL ;
    PORT
      LAYER M4 ;
        RECT 172.7160 325.1520 172.8000 325.1760 ;
    END
  END m_dd[109]
  PIN m_dd[10]
    DIRECTION OUTPUT ;
    USE SIGNAL ;
    PORT
      LAYER M4 ;
        RECT 172.7160 238.6560 172.8000 238.6800 ;
    END
  END m_dd[10]
  PIN m_dd[110]
    DIRECTION OUTPUT ;
    USE SIGNAL ;
    PORT
      LAYER M4 ;
        RECT 172.7160 326.0160 172.8000 326.0400 ;
    END
  END m_dd[110]
  PIN m_dd[111]
    DIRECTION OUTPUT ;
    USE SIGNAL ;
    PORT
      LAYER M4 ;
        RECT 172.7160 326.8800 172.8000 326.9040 ;
    END
  END m_dd[111]
  PIN m_dd[112]
    DIRECTION OUTPUT ;
    USE SIGNAL ;
    PORT
      LAYER M4 ;
        RECT 172.7160 327.7440 172.8000 327.7680 ;
    END
  END m_dd[112]
  PIN m_dd[113]
    DIRECTION OUTPUT ;
    USE SIGNAL ;
    PORT
      LAYER M4 ;
        RECT 172.7160 328.6080 172.8000 328.6320 ;
    END
  END m_dd[113]
  PIN m_dd[114]
    DIRECTION OUTPUT ;
    USE SIGNAL ;
    PORT
      LAYER M4 ;
        RECT 172.7160 329.4720 172.8000 329.4960 ;
    END
  END m_dd[114]
  PIN m_dd[115]
    DIRECTION OUTPUT ;
    USE SIGNAL ;
    PORT
      LAYER M4 ;
        RECT 172.7160 330.3360 172.8000 330.3600 ;
    END
  END m_dd[115]
  PIN m_dd[116]
    DIRECTION OUTPUT ;
    USE SIGNAL ;
    PORT
      LAYER M4 ;
        RECT 172.7160 331.2000 172.8000 331.2240 ;
    END
  END m_dd[116]
  PIN m_dd[117]
    DIRECTION OUTPUT ;
    USE SIGNAL ;
    PORT
      LAYER M4 ;
        RECT 172.7160 332.0640 172.8000 332.0880 ;
    END
  END m_dd[117]
  PIN m_dd[118]
    DIRECTION OUTPUT ;
    USE SIGNAL ;
    PORT
      LAYER M4 ;
        RECT 172.7160 332.9280 172.8000 332.9520 ;
    END
  END m_dd[118]
  PIN m_dd[119]
    DIRECTION OUTPUT ;
    USE SIGNAL ;
    PORT
      LAYER M4 ;
        RECT 172.7160 333.8880 172.8000 333.9120 ;
    END
  END m_dd[119]
  PIN m_dd[11]
    DIRECTION OUTPUT ;
    USE SIGNAL ;
    PORT
      LAYER M4 ;
        RECT 172.7160 239.6160 172.8000 239.6400 ;
    END
  END m_dd[11]
  PIN m_dd[120]
    DIRECTION OUTPUT ;
    USE SIGNAL ;
    PORT
      LAYER M4 ;
        RECT 172.7160 334.7520 172.8000 334.7760 ;
    END
  END m_dd[120]
  PIN m_dd[121]
    DIRECTION OUTPUT ;
    USE SIGNAL ;
    PORT
      LAYER M4 ;
        RECT 172.7160 335.6160 172.8000 335.6400 ;
    END
  END m_dd[121]
  PIN m_dd[122]
    DIRECTION OUTPUT ;
    USE SIGNAL ;
    PORT
      LAYER M4 ;
        RECT 172.7160 336.4800 172.8000 336.5040 ;
    END
  END m_dd[122]
  PIN m_dd[123]
    DIRECTION OUTPUT ;
    USE SIGNAL ;
    PORT
      LAYER M4 ;
        RECT 172.7160 337.3440 172.8000 337.3680 ;
    END
  END m_dd[123]
  PIN m_dd[124]
    DIRECTION OUTPUT ;
    USE SIGNAL ;
    PORT
      LAYER M4 ;
        RECT 172.7160 338.2080 172.8000 338.2320 ;
    END
  END m_dd[124]
  PIN m_dd[125]
    DIRECTION OUTPUT ;
    USE SIGNAL ;
    PORT
      LAYER M4 ;
        RECT 172.7160 339.0720 172.8000 339.0960 ;
    END
  END m_dd[125]
  PIN m_dd[126]
    DIRECTION OUTPUT ;
    USE SIGNAL ;
    PORT
      LAYER M4 ;
        RECT 172.7160 339.9360 172.8000 339.9600 ;
    END
  END m_dd[126]
  PIN m_dd[127]
    DIRECTION OUTPUT ;
    USE SIGNAL ;
    PORT
      LAYER M4 ;
        RECT 172.7160 340.8000 172.8000 340.8240 ;
    END
  END m_dd[127]
  PIN m_dd[12]
    DIRECTION OUTPUT ;
    USE SIGNAL ;
    PORT
      LAYER M4 ;
        RECT 172.7160 240.4800 172.8000 240.5040 ;
    END
  END m_dd[12]
  PIN m_dd[13]
    DIRECTION OUTPUT ;
    USE SIGNAL ;
    PORT
      LAYER M4 ;
        RECT 172.7160 241.3440 172.8000 241.3680 ;
    END
  END m_dd[13]
  PIN m_dd[14]
    DIRECTION OUTPUT ;
    USE SIGNAL ;
    PORT
      LAYER M4 ;
        RECT 172.7160 242.2080 172.8000 242.2320 ;
    END
  END m_dd[14]
  PIN m_dd[15]
    DIRECTION OUTPUT ;
    USE SIGNAL ;
    PORT
      LAYER M4 ;
        RECT 172.7160 243.0720 172.8000 243.0960 ;
    END
  END m_dd[15]
  PIN m_dd[16]
    DIRECTION OUTPUT ;
    USE SIGNAL ;
    PORT
      LAYER M4 ;
        RECT 172.7160 243.9360 172.8000 243.9600 ;
    END
  END m_dd[16]
  PIN m_dd[17]
    DIRECTION OUTPUT ;
    USE SIGNAL ;
    PORT
      LAYER M4 ;
        RECT 172.7160 244.8000 172.8000 244.8240 ;
    END
  END m_dd[17]
  PIN m_dd[18]
    DIRECTION OUTPUT ;
    USE SIGNAL ;
    PORT
      LAYER M4 ;
        RECT 172.7160 245.6640 172.8000 245.6880 ;
    END
  END m_dd[18]
  PIN m_dd[19]
    DIRECTION OUTPUT ;
    USE SIGNAL ;
    PORT
      LAYER M4 ;
        RECT 172.7160 246.5280 172.8000 246.5520 ;
    END
  END m_dd[19]
  PIN m_dd[1]
    DIRECTION OUTPUT ;
    USE SIGNAL ;
    PORT
      LAYER M4 ;
        RECT 172.7160 230.8800 172.8000 230.9040 ;
    END
  END m_dd[1]
  PIN m_dd[20]
    DIRECTION OUTPUT ;
    USE SIGNAL ;
    PORT
      LAYER M4 ;
        RECT 172.7160 247.3920 172.8000 247.4160 ;
    END
  END m_dd[20]
  PIN m_dd[21]
    DIRECTION OUTPUT ;
    USE SIGNAL ;
    PORT
      LAYER M4 ;
        RECT 172.7160 248.2560 172.8000 248.2800 ;
    END
  END m_dd[21]
  PIN m_dd[22]
    DIRECTION OUTPUT ;
    USE SIGNAL ;
    PORT
      LAYER M4 ;
        RECT 172.7160 249.2160 172.8000 249.2400 ;
    END
  END m_dd[22]
  PIN m_dd[23]
    DIRECTION OUTPUT ;
    USE SIGNAL ;
    PORT
      LAYER M4 ;
        RECT 172.7160 250.0800 172.8000 250.1040 ;
    END
  END m_dd[23]
  PIN m_dd[24]
    DIRECTION OUTPUT ;
    USE SIGNAL ;
    PORT
      LAYER M4 ;
        RECT 172.7160 250.9440 172.8000 250.9680 ;
    END
  END m_dd[24]
  PIN m_dd[25]
    DIRECTION OUTPUT ;
    USE SIGNAL ;
    PORT
      LAYER M4 ;
        RECT 172.7160 251.8080 172.8000 251.8320 ;
    END
  END m_dd[25]
  PIN m_dd[26]
    DIRECTION OUTPUT ;
    USE SIGNAL ;
    PORT
      LAYER M4 ;
        RECT 172.7160 252.6720 172.8000 252.6960 ;
    END
  END m_dd[26]
  PIN m_dd[27]
    DIRECTION OUTPUT ;
    USE SIGNAL ;
    PORT
      LAYER M4 ;
        RECT 172.7160 253.5360 172.8000 253.5600 ;
    END
  END m_dd[27]
  PIN m_dd[28]
    DIRECTION OUTPUT ;
    USE SIGNAL ;
    PORT
      LAYER M4 ;
        RECT 172.7160 254.4000 172.8000 254.4240 ;
    END
  END m_dd[28]
  PIN m_dd[29]
    DIRECTION OUTPUT ;
    USE SIGNAL ;
    PORT
      LAYER M4 ;
        RECT 172.7160 255.2640 172.8000 255.2880 ;
    END
  END m_dd[29]
  PIN m_dd[2]
    DIRECTION OUTPUT ;
    USE SIGNAL ;
    PORT
      LAYER M4 ;
        RECT 172.7160 231.7440 172.8000 231.7680 ;
    END
  END m_dd[2]
  PIN m_dd[30]
    DIRECTION OUTPUT ;
    USE SIGNAL ;
    PORT
      LAYER M4 ;
        RECT 172.7160 256.1280 172.8000 256.1520 ;
    END
  END m_dd[30]
  PIN m_dd[31]
    DIRECTION OUTPUT ;
    USE SIGNAL ;
    PORT
      LAYER M4 ;
        RECT 172.7160 256.9920 172.8000 257.0160 ;
    END
  END m_dd[31]
  PIN m_dd[32]
    DIRECTION OUTPUT ;
    USE SIGNAL ;
    PORT
      LAYER M4 ;
        RECT 172.7160 257.8560 172.8000 257.8800 ;
    END
  END m_dd[32]
  PIN m_dd[33]
    DIRECTION OUTPUT ;
    USE SIGNAL ;
    PORT
      LAYER M4 ;
        RECT 172.7160 258.8160 172.8000 258.8400 ;
    END
  END m_dd[33]
  PIN m_dd[34]
    DIRECTION OUTPUT ;
    USE SIGNAL ;
    PORT
      LAYER M4 ;
        RECT 172.7160 259.6800 172.8000 259.7040 ;
    END
  END m_dd[34]
  PIN m_dd[35]
    DIRECTION OUTPUT ;
    USE SIGNAL ;
    PORT
      LAYER M4 ;
        RECT 172.7160 260.5440 172.8000 260.5680 ;
    END
  END m_dd[35]
  PIN m_dd[36]
    DIRECTION OUTPUT ;
    USE SIGNAL ;
    PORT
      LAYER M4 ;
        RECT 172.7160 261.4080 172.8000 261.4320 ;
    END
  END m_dd[36]
  PIN m_dd[37]
    DIRECTION OUTPUT ;
    USE SIGNAL ;
    PORT
      LAYER M4 ;
        RECT 172.7160 262.2720 172.8000 262.2960 ;
    END
  END m_dd[37]
  PIN m_dd[38]
    DIRECTION OUTPUT ;
    USE SIGNAL ;
    PORT
      LAYER M4 ;
        RECT 172.7160 263.1360 172.8000 263.1600 ;
    END
  END m_dd[38]
  PIN m_dd[39]
    DIRECTION OUTPUT ;
    USE SIGNAL ;
    PORT
      LAYER M4 ;
        RECT 172.7160 264.0000 172.8000 264.0240 ;
    END
  END m_dd[39]
  PIN m_dd[3]
    DIRECTION OUTPUT ;
    USE SIGNAL ;
    PORT
      LAYER M4 ;
        RECT 172.7160 232.6080 172.8000 232.6320 ;
    END
  END m_dd[3]
  PIN m_dd[40]
    DIRECTION OUTPUT ;
    USE SIGNAL ;
    PORT
      LAYER M4 ;
        RECT 172.7160 264.8640 172.8000 264.8880 ;
    END
  END m_dd[40]
  PIN m_dd[41]
    DIRECTION OUTPUT ;
    USE SIGNAL ;
    PORT
      LAYER M4 ;
        RECT 172.7160 265.7280 172.8000 265.7520 ;
    END
  END m_dd[41]
  PIN m_dd[42]
    DIRECTION OUTPUT ;
    USE SIGNAL ;
    PORT
      LAYER M4 ;
        RECT 172.7160 266.5920 172.8000 266.6160 ;
    END
  END m_dd[42]
  PIN m_dd[43]
    DIRECTION OUTPUT ;
    USE SIGNAL ;
    PORT
      LAYER M4 ;
        RECT 172.7160 267.4560 172.8000 267.4800 ;
    END
  END m_dd[43]
  PIN m_dd[44]
    DIRECTION OUTPUT ;
    USE SIGNAL ;
    PORT
      LAYER M4 ;
        RECT 172.7160 268.4160 172.8000 268.4400 ;
    END
  END m_dd[44]
  PIN m_dd[45]
    DIRECTION OUTPUT ;
    USE SIGNAL ;
    PORT
      LAYER M4 ;
        RECT 172.7160 269.2800 172.8000 269.3040 ;
    END
  END m_dd[45]
  PIN m_dd[46]
    DIRECTION OUTPUT ;
    USE SIGNAL ;
    PORT
      LAYER M4 ;
        RECT 172.7160 270.1440 172.8000 270.1680 ;
    END
  END m_dd[46]
  PIN m_dd[47]
    DIRECTION OUTPUT ;
    USE SIGNAL ;
    PORT
      LAYER M4 ;
        RECT 172.7160 271.0080 172.8000 271.0320 ;
    END
  END m_dd[47]
  PIN m_dd[48]
    DIRECTION OUTPUT ;
    USE SIGNAL ;
    PORT
      LAYER M4 ;
        RECT 172.7160 271.8720 172.8000 271.8960 ;
    END
  END m_dd[48]
  PIN m_dd[49]
    DIRECTION OUTPUT ;
    USE SIGNAL ;
    PORT
      LAYER M4 ;
        RECT 172.7160 272.7360 172.8000 272.7600 ;
    END
  END m_dd[49]
  PIN m_dd[4]
    DIRECTION OUTPUT ;
    USE SIGNAL ;
    PORT
      LAYER M4 ;
        RECT 172.7160 233.4720 172.8000 233.4960 ;
    END
  END m_dd[4]
  PIN m_dd[50]
    DIRECTION OUTPUT ;
    USE SIGNAL ;
    PORT
      LAYER M4 ;
        RECT 172.7160 273.6000 172.8000 273.6240 ;
    END
  END m_dd[50]
  PIN m_dd[51]
    DIRECTION OUTPUT ;
    USE SIGNAL ;
    PORT
      LAYER M4 ;
        RECT 172.7160 274.4640 172.8000 274.4880 ;
    END
  END m_dd[51]
  PIN m_dd[52]
    DIRECTION OUTPUT ;
    USE SIGNAL ;
    PORT
      LAYER M4 ;
        RECT 172.7160 275.3280 172.8000 275.3520 ;
    END
  END m_dd[52]
  PIN m_dd[53]
    DIRECTION OUTPUT ;
    USE SIGNAL ;
    PORT
      LAYER M4 ;
        RECT 172.7160 276.1920 172.8000 276.2160 ;
    END
  END m_dd[53]
  PIN m_dd[54]
    DIRECTION OUTPUT ;
    USE SIGNAL ;
    PORT
      LAYER M4 ;
        RECT 172.7160 277.1520 172.8000 277.1760 ;
    END
  END m_dd[54]
  PIN m_dd[55]
    DIRECTION OUTPUT ;
    USE SIGNAL ;
    PORT
      LAYER M4 ;
        RECT 172.7160 278.0160 172.8000 278.0400 ;
    END
  END m_dd[55]
  PIN m_dd[56]
    DIRECTION OUTPUT ;
    USE SIGNAL ;
    PORT
      LAYER M4 ;
        RECT 172.7160 278.8800 172.8000 278.9040 ;
    END
  END m_dd[56]
  PIN m_dd[57]
    DIRECTION OUTPUT ;
    USE SIGNAL ;
    PORT
      LAYER M4 ;
        RECT 172.7160 279.7440 172.8000 279.7680 ;
    END
  END m_dd[57]
  PIN m_dd[58]
    DIRECTION OUTPUT ;
    USE SIGNAL ;
    PORT
      LAYER M4 ;
        RECT 172.7160 280.6080 172.8000 280.6320 ;
    END
  END m_dd[58]
  PIN m_dd[59]
    DIRECTION OUTPUT ;
    USE SIGNAL ;
    PORT
      LAYER M4 ;
        RECT 172.7160 281.4720 172.8000 281.4960 ;
    END
  END m_dd[59]
  PIN m_dd[5]
    DIRECTION OUTPUT ;
    USE SIGNAL ;
    PORT
      LAYER M4 ;
        RECT 172.7160 234.3360 172.8000 234.3600 ;
    END
  END m_dd[5]
  PIN m_dd[60]
    DIRECTION OUTPUT ;
    USE SIGNAL ;
    PORT
      LAYER M4 ;
        RECT 172.7160 282.3360 172.8000 282.3600 ;
    END
  END m_dd[60]
  PIN m_dd[61]
    DIRECTION OUTPUT ;
    USE SIGNAL ;
    PORT
      LAYER M4 ;
        RECT 172.7160 283.2000 172.8000 283.2240 ;
    END
  END m_dd[61]
  PIN m_dd[62]
    DIRECTION OUTPUT ;
    USE SIGNAL ;
    PORT
      LAYER M4 ;
        RECT 172.7160 284.0640 172.8000 284.0880 ;
    END
  END m_dd[62]
  PIN m_dd[63]
    DIRECTION OUTPUT ;
    USE SIGNAL ;
    PORT
      LAYER M4 ;
        RECT 172.7160 284.9280 172.8000 284.9520 ;
    END
  END m_dd[63]
  PIN m_dd[64]
    DIRECTION OUTPUT ;
    USE SIGNAL ;
    PORT
      LAYER M4 ;
        RECT 172.7160 285.7920 172.8000 285.8160 ;
    END
  END m_dd[64]
  PIN m_dd[65]
    DIRECTION OUTPUT ;
    USE SIGNAL ;
    PORT
      LAYER M4 ;
        RECT 172.7160 286.7520 172.8000 286.7760 ;
    END
  END m_dd[65]
  PIN m_dd[66]
    DIRECTION OUTPUT ;
    USE SIGNAL ;
    PORT
      LAYER M4 ;
        RECT 172.7160 287.6160 172.8000 287.6400 ;
    END
  END m_dd[66]
  PIN m_dd[67]
    DIRECTION OUTPUT ;
    USE SIGNAL ;
    PORT
      LAYER M4 ;
        RECT 172.7160 288.4800 172.8000 288.5040 ;
    END
  END m_dd[67]
  PIN m_dd[68]
    DIRECTION OUTPUT ;
    USE SIGNAL ;
    PORT
      LAYER M4 ;
        RECT 172.7160 289.3440 172.8000 289.3680 ;
    END
  END m_dd[68]
  PIN m_dd[69]
    DIRECTION OUTPUT ;
    USE SIGNAL ;
    PORT
      LAYER M4 ;
        RECT 172.7160 290.2080 172.8000 290.2320 ;
    END
  END m_dd[69]
  PIN m_dd[6]
    DIRECTION OUTPUT ;
    USE SIGNAL ;
    PORT
      LAYER M4 ;
        RECT 172.7160 235.2000 172.8000 235.2240 ;
    END
  END m_dd[6]
  PIN m_dd[70]
    DIRECTION OUTPUT ;
    USE SIGNAL ;
    PORT
      LAYER M4 ;
        RECT 172.7160 291.0720 172.8000 291.0960 ;
    END
  END m_dd[70]
  PIN m_dd[71]
    DIRECTION OUTPUT ;
    USE SIGNAL ;
    PORT
      LAYER M4 ;
        RECT 172.7160 291.9360 172.8000 291.9600 ;
    END
  END m_dd[71]
  PIN m_dd[72]
    DIRECTION OUTPUT ;
    USE SIGNAL ;
    PORT
      LAYER M4 ;
        RECT 172.7160 292.8000 172.8000 292.8240 ;
    END
  END m_dd[72]
  PIN m_dd[73]
    DIRECTION OUTPUT ;
    USE SIGNAL ;
    PORT
      LAYER M4 ;
        RECT 172.7160 293.6640 172.8000 293.6880 ;
    END
  END m_dd[73]
  PIN m_dd[74]
    DIRECTION OUTPUT ;
    USE SIGNAL ;
    PORT
      LAYER M4 ;
        RECT 172.7160 294.5280 172.8000 294.5520 ;
    END
  END m_dd[74]
  PIN m_dd[75]
    DIRECTION OUTPUT ;
    USE SIGNAL ;
    PORT
      LAYER M4 ;
        RECT 172.7160 295.3920 172.8000 295.4160 ;
    END
  END m_dd[75]
  PIN m_dd[76]
    DIRECTION OUTPUT ;
    USE SIGNAL ;
    PORT
      LAYER M4 ;
        RECT 172.7160 296.3520 172.8000 296.3760 ;
    END
  END m_dd[76]
  PIN m_dd[77]
    DIRECTION OUTPUT ;
    USE SIGNAL ;
    PORT
      LAYER M4 ;
        RECT 172.7160 297.2160 172.8000 297.2400 ;
    END
  END m_dd[77]
  PIN m_dd[78]
    DIRECTION OUTPUT ;
    USE SIGNAL ;
    PORT
      LAYER M4 ;
        RECT 172.7160 298.0800 172.8000 298.1040 ;
    END
  END m_dd[78]
  PIN m_dd[79]
    DIRECTION OUTPUT ;
    USE SIGNAL ;
    PORT
      LAYER M4 ;
        RECT 172.7160 298.9440 172.8000 298.9680 ;
    END
  END m_dd[79]
  PIN m_dd[7]
    DIRECTION OUTPUT ;
    USE SIGNAL ;
    PORT
      LAYER M4 ;
        RECT 172.7160 236.0640 172.8000 236.0880 ;
    END
  END m_dd[7]
  PIN m_dd[80]
    DIRECTION OUTPUT ;
    USE SIGNAL ;
    PORT
      LAYER M4 ;
        RECT 172.7160 299.8080 172.8000 299.8320 ;
    END
  END m_dd[80]
  PIN m_dd[81]
    DIRECTION OUTPUT ;
    USE SIGNAL ;
    PORT
      LAYER M4 ;
        RECT 172.7160 300.6720 172.8000 300.6960 ;
    END
  END m_dd[81]
  PIN m_dd[82]
    DIRECTION OUTPUT ;
    USE SIGNAL ;
    PORT
      LAYER M4 ;
        RECT 172.7160 301.5360 172.8000 301.5600 ;
    END
  END m_dd[82]
  PIN m_dd[83]
    DIRECTION OUTPUT ;
    USE SIGNAL ;
    PORT
      LAYER M4 ;
        RECT 172.7160 302.4000 172.8000 302.4240 ;
    END
  END m_dd[83]
  PIN m_dd[84]
    DIRECTION OUTPUT ;
    USE SIGNAL ;
    PORT
      LAYER M4 ;
        RECT 172.7160 303.2640 172.8000 303.2880 ;
    END
  END m_dd[84]
  PIN m_dd[85]
    DIRECTION OUTPUT ;
    USE SIGNAL ;
    PORT
      LAYER M4 ;
        RECT 172.7160 304.1280 172.8000 304.1520 ;
    END
  END m_dd[85]
  PIN m_dd[86]
    DIRECTION OUTPUT ;
    USE SIGNAL ;
    PORT
      LAYER M4 ;
        RECT 172.7160 305.0880 172.8000 305.1120 ;
    END
  END m_dd[86]
  PIN m_dd[87]
    DIRECTION OUTPUT ;
    USE SIGNAL ;
    PORT
      LAYER M4 ;
        RECT 172.7160 305.9520 172.8000 305.9760 ;
    END
  END m_dd[87]
  PIN m_dd[88]
    DIRECTION OUTPUT ;
    USE SIGNAL ;
    PORT
      LAYER M4 ;
        RECT 172.7160 306.8160 172.8000 306.8400 ;
    END
  END m_dd[88]
  PIN m_dd[89]
    DIRECTION OUTPUT ;
    USE SIGNAL ;
    PORT
      LAYER M4 ;
        RECT 172.7160 307.6800 172.8000 307.7040 ;
    END
  END m_dd[89]
  PIN m_dd[8]
    DIRECTION OUTPUT ;
    USE SIGNAL ;
    PORT
      LAYER M4 ;
        RECT 172.7160 236.9280 172.8000 236.9520 ;
    END
  END m_dd[8]
  PIN m_dd[90]
    DIRECTION OUTPUT ;
    USE SIGNAL ;
    PORT
      LAYER M4 ;
        RECT 172.7160 308.5440 172.8000 308.5680 ;
    END
  END m_dd[90]
  PIN m_dd[91]
    DIRECTION OUTPUT ;
    USE SIGNAL ;
    PORT
      LAYER M4 ;
        RECT 172.7160 309.4080 172.8000 309.4320 ;
    END
  END m_dd[91]
  PIN m_dd[92]
    DIRECTION OUTPUT ;
    USE SIGNAL ;
    PORT
      LAYER M4 ;
        RECT 172.7160 310.2720 172.8000 310.2960 ;
    END
  END m_dd[92]
  PIN m_dd[93]
    DIRECTION OUTPUT ;
    USE SIGNAL ;
    PORT
      LAYER M4 ;
        RECT 172.7160 311.1360 172.8000 311.1600 ;
    END
  END m_dd[93]
  PIN m_dd[94]
    DIRECTION OUTPUT ;
    USE SIGNAL ;
    PORT
      LAYER M4 ;
        RECT 172.7160 312.0000 172.8000 312.0240 ;
    END
  END m_dd[94]
  PIN m_dd[95]
    DIRECTION OUTPUT ;
    USE SIGNAL ;
    PORT
      LAYER M4 ;
        RECT 172.7160 312.8640 172.8000 312.8880 ;
    END
  END m_dd[95]
  PIN m_dd[96]
    DIRECTION OUTPUT ;
    USE SIGNAL ;
    PORT
      LAYER M4 ;
        RECT 172.7160 313.7280 172.8000 313.7520 ;
    END
  END m_dd[96]
  PIN m_dd[97]
    DIRECTION OUTPUT ;
    USE SIGNAL ;
    PORT
      LAYER M4 ;
        RECT 172.7160 314.6880 172.8000 314.7120 ;
    END
  END m_dd[97]
  PIN m_dd[98]
    DIRECTION OUTPUT ;
    USE SIGNAL ;
    PORT
      LAYER M4 ;
        RECT 172.7160 315.5520 172.8000 315.5760 ;
    END
  END m_dd[98]
  PIN m_dd[99]
    DIRECTION OUTPUT ;
    USE SIGNAL ;
    PORT
      LAYER M4 ;
        RECT 172.7160 316.4160 172.8000 316.4400 ;
    END
  END m_dd[99]
  PIN m_dd[9]
    DIRECTION OUTPUT ;
    USE SIGNAL ;
    PORT
      LAYER M4 ;
        RECT 172.7160 237.7920 172.8000 237.8160 ;
    END
  END m_dd[9]
  PIN m_hh[0]
    DIRECTION OUTPUT ;
    USE SIGNAL ;
    PORT
      LAYER M4 ;
        RECT 172.7160 6.5280 172.8000 6.5520 ;
    END
  END m_hh[0]
  PIN m_hh[100]
    DIRECTION OUTPUT ;
    USE SIGNAL ;
    PORT
      LAYER M4 ;
        RECT 172.7160 93.7920 172.8000 93.8160 ;
    END
  END m_hh[100]
  PIN m_hh[101]
    DIRECTION OUTPUT ;
    USE SIGNAL ;
    PORT
      LAYER M4 ;
        RECT 172.7160 94.6560 172.8000 94.6800 ;
    END
  END m_hh[101]
  PIN m_hh[102]
    DIRECTION OUTPUT ;
    USE SIGNAL ;
    PORT
      LAYER M4 ;
        RECT 172.7160 95.5200 172.8000 95.5440 ;
    END
  END m_hh[102]
  PIN m_hh[103]
    DIRECTION OUTPUT ;
    USE SIGNAL ;
    PORT
      LAYER M4 ;
        RECT 172.7160 96.3840 172.8000 96.4080 ;
    END
  END m_hh[103]
  PIN m_hh[104]
    DIRECTION OUTPUT ;
    USE SIGNAL ;
    PORT
      LAYER M4 ;
        RECT 172.7160 97.2480 172.8000 97.2720 ;
    END
  END m_hh[104]
  PIN m_hh[105]
    DIRECTION OUTPUT ;
    USE SIGNAL ;
    PORT
      LAYER M4 ;
        RECT 172.7160 98.1120 172.8000 98.1360 ;
    END
  END m_hh[105]
  PIN m_hh[106]
    DIRECTION OUTPUT ;
    USE SIGNAL ;
    PORT
      LAYER M4 ;
        RECT 172.7160 98.9760 172.8000 99.0000 ;
    END
  END m_hh[106]
  PIN m_hh[107]
    DIRECTION OUTPUT ;
    USE SIGNAL ;
    PORT
      LAYER M4 ;
        RECT 172.7160 99.9360 172.8000 99.9600 ;
    END
  END m_hh[107]
  PIN m_hh[108]
    DIRECTION OUTPUT ;
    USE SIGNAL ;
    PORT
      LAYER M4 ;
        RECT 172.7160 100.8000 172.8000 100.8240 ;
    END
  END m_hh[108]
  PIN m_hh[109]
    DIRECTION OUTPUT ;
    USE SIGNAL ;
    PORT
      LAYER M4 ;
        RECT 172.7160 101.6640 172.8000 101.6880 ;
    END
  END m_hh[109]
  PIN m_hh[10]
    DIRECTION OUTPUT ;
    USE SIGNAL ;
    PORT
      LAYER M4 ;
        RECT 172.7160 15.2640 172.8000 15.2880 ;
    END
  END m_hh[10]
  PIN m_hh[110]
    DIRECTION OUTPUT ;
    USE SIGNAL ;
    PORT
      LAYER M4 ;
        RECT 172.7160 102.5280 172.8000 102.5520 ;
    END
  END m_hh[110]
  PIN m_hh[111]
    DIRECTION OUTPUT ;
    USE SIGNAL ;
    PORT
      LAYER M4 ;
        RECT 172.7160 103.3920 172.8000 103.4160 ;
    END
  END m_hh[111]
  PIN m_hh[112]
    DIRECTION OUTPUT ;
    USE SIGNAL ;
    PORT
      LAYER M4 ;
        RECT 172.7160 104.2560 172.8000 104.2800 ;
    END
  END m_hh[112]
  PIN m_hh[113]
    DIRECTION OUTPUT ;
    USE SIGNAL ;
    PORT
      LAYER M4 ;
        RECT 172.7160 105.1200 172.8000 105.1440 ;
    END
  END m_hh[113]
  PIN m_hh[114]
    DIRECTION OUTPUT ;
    USE SIGNAL ;
    PORT
      LAYER M4 ;
        RECT 172.7160 105.9840 172.8000 106.0080 ;
    END
  END m_hh[114]
  PIN m_hh[115]
    DIRECTION OUTPUT ;
    USE SIGNAL ;
    PORT
      LAYER M4 ;
        RECT 172.7160 106.8480 172.8000 106.8720 ;
    END
  END m_hh[115]
  PIN m_hh[116]
    DIRECTION OUTPUT ;
    USE SIGNAL ;
    PORT
      LAYER M4 ;
        RECT 172.7160 107.7120 172.8000 107.7360 ;
    END
  END m_hh[116]
  PIN m_hh[117]
    DIRECTION OUTPUT ;
    USE SIGNAL ;
    PORT
      LAYER M4 ;
        RECT 172.7160 108.6720 172.8000 108.6960 ;
    END
  END m_hh[117]
  PIN m_hh[118]
    DIRECTION OUTPUT ;
    USE SIGNAL ;
    PORT
      LAYER M4 ;
        RECT 172.7160 109.5360 172.8000 109.5600 ;
    END
  END m_hh[118]
  PIN m_hh[119]
    DIRECTION OUTPUT ;
    USE SIGNAL ;
    PORT
      LAYER M4 ;
        RECT 172.7160 110.4000 172.8000 110.4240 ;
    END
  END m_hh[119]
  PIN m_hh[11]
    DIRECTION OUTPUT ;
    USE SIGNAL ;
    PORT
      LAYER M4 ;
        RECT 172.7160 16.1280 172.8000 16.1520 ;
    END
  END m_hh[11]
  PIN m_hh[120]
    DIRECTION OUTPUT ;
    USE SIGNAL ;
    PORT
      LAYER M4 ;
        RECT 172.7160 111.2640 172.8000 111.2880 ;
    END
  END m_hh[120]
  PIN m_hh[121]
    DIRECTION OUTPUT ;
    USE SIGNAL ;
    PORT
      LAYER M4 ;
        RECT 172.7160 112.1280 172.8000 112.1520 ;
    END
  END m_hh[121]
  PIN m_hh[122]
    DIRECTION OUTPUT ;
    USE SIGNAL ;
    PORT
      LAYER M4 ;
        RECT 172.7160 112.9920 172.8000 113.0160 ;
    END
  END m_hh[122]
  PIN m_hh[123]
    DIRECTION OUTPUT ;
    USE SIGNAL ;
    PORT
      LAYER M4 ;
        RECT 172.7160 113.8560 172.8000 113.8800 ;
    END
  END m_hh[123]
  PIN m_hh[124]
    DIRECTION OUTPUT ;
    USE SIGNAL ;
    PORT
      LAYER M4 ;
        RECT 172.7160 114.7200 172.8000 114.7440 ;
    END
  END m_hh[124]
  PIN m_hh[125]
    DIRECTION OUTPUT ;
    USE SIGNAL ;
    PORT
      LAYER M4 ;
        RECT 172.7160 115.5840 172.8000 115.6080 ;
    END
  END m_hh[125]
  PIN m_hh[126]
    DIRECTION OUTPUT ;
    USE SIGNAL ;
    PORT
      LAYER M4 ;
        RECT 172.7160 116.4480 172.8000 116.4720 ;
    END
  END m_hh[126]
  PIN m_hh[127]
    DIRECTION OUTPUT ;
    USE SIGNAL ;
    PORT
      LAYER M4 ;
        RECT 172.7160 117.3120 172.8000 117.3360 ;
    END
  END m_hh[127]
  PIN m_hh[12]
    DIRECTION OUTPUT ;
    USE SIGNAL ;
    PORT
      LAYER M4 ;
        RECT 172.7160 16.9920 172.8000 17.0160 ;
    END
  END m_hh[12]
  PIN m_hh[13]
    DIRECTION OUTPUT ;
    USE SIGNAL ;
    PORT
      LAYER M4 ;
        RECT 172.7160 17.8560 172.8000 17.8800 ;
    END
  END m_hh[13]
  PIN m_hh[14]
    DIRECTION OUTPUT ;
    USE SIGNAL ;
    PORT
      LAYER M4 ;
        RECT 172.7160 18.7200 172.8000 18.7440 ;
    END
  END m_hh[14]
  PIN m_hh[15]
    DIRECTION OUTPUT ;
    USE SIGNAL ;
    PORT
      LAYER M4 ;
        RECT 172.7160 19.5840 172.8000 19.6080 ;
    END
  END m_hh[15]
  PIN m_hh[16]
    DIRECTION OUTPUT ;
    USE SIGNAL ;
    PORT
      LAYER M4 ;
        RECT 172.7160 20.4480 172.8000 20.4720 ;
    END
  END m_hh[16]
  PIN m_hh[17]
    DIRECTION OUTPUT ;
    USE SIGNAL ;
    PORT
      LAYER M4 ;
        RECT 172.7160 21.3120 172.8000 21.3360 ;
    END
  END m_hh[17]
  PIN m_hh[18]
    DIRECTION OUTPUT ;
    USE SIGNAL ;
    PORT
      LAYER M4 ;
        RECT 172.7160 22.1760 172.8000 22.2000 ;
    END
  END m_hh[18]
  PIN m_hh[19]
    DIRECTION OUTPUT ;
    USE SIGNAL ;
    PORT
      LAYER M4 ;
        RECT 172.7160 23.0400 172.8000 23.0640 ;
    END
  END m_hh[19]
  PIN m_hh[1]
    DIRECTION OUTPUT ;
    USE SIGNAL ;
    PORT
      LAYER M4 ;
        RECT 172.7160 7.3920 172.8000 7.4160 ;
    END
  END m_hh[1]
  PIN m_hh[20]
    DIRECTION OUTPUT ;
    USE SIGNAL ;
    PORT
      LAYER M4 ;
        RECT 172.7160 23.9040 172.8000 23.9280 ;
    END
  END m_hh[20]
  PIN m_hh[21]
    DIRECTION OUTPUT ;
    USE SIGNAL ;
    PORT
      LAYER M4 ;
        RECT 172.7160 24.8640 172.8000 24.8880 ;
    END
  END m_hh[21]
  PIN m_hh[22]
    DIRECTION OUTPUT ;
    USE SIGNAL ;
    PORT
      LAYER M4 ;
        RECT 172.7160 25.7280 172.8000 25.7520 ;
    END
  END m_hh[22]
  PIN m_hh[23]
    DIRECTION OUTPUT ;
    USE SIGNAL ;
    PORT
      LAYER M4 ;
        RECT 172.7160 26.5920 172.8000 26.6160 ;
    END
  END m_hh[23]
  PIN m_hh[24]
    DIRECTION OUTPUT ;
    USE SIGNAL ;
    PORT
      LAYER M4 ;
        RECT 172.7160 27.4560 172.8000 27.4800 ;
    END
  END m_hh[24]
  PIN m_hh[25]
    DIRECTION OUTPUT ;
    USE SIGNAL ;
    PORT
      LAYER M4 ;
        RECT 172.7160 28.3200 172.8000 28.3440 ;
    END
  END m_hh[25]
  PIN m_hh[26]
    DIRECTION OUTPUT ;
    USE SIGNAL ;
    PORT
      LAYER M4 ;
        RECT 172.7160 29.1840 172.8000 29.2080 ;
    END
  END m_hh[26]
  PIN m_hh[27]
    DIRECTION OUTPUT ;
    USE SIGNAL ;
    PORT
      LAYER M4 ;
        RECT 172.7160 30.0480 172.8000 30.0720 ;
    END
  END m_hh[27]
  PIN m_hh[28]
    DIRECTION OUTPUT ;
    USE SIGNAL ;
    PORT
      LAYER M4 ;
        RECT 172.7160 30.9120 172.8000 30.9360 ;
    END
  END m_hh[28]
  PIN m_hh[29]
    DIRECTION OUTPUT ;
    USE SIGNAL ;
    PORT
      LAYER M4 ;
        RECT 172.7160 31.7760 172.8000 31.8000 ;
    END
  END m_hh[29]
  PIN m_hh[2]
    DIRECTION OUTPUT ;
    USE SIGNAL ;
    PORT
      LAYER M4 ;
        RECT 172.7160 8.2560 172.8000 8.2800 ;
    END
  END m_hh[2]
  PIN m_hh[30]
    DIRECTION OUTPUT ;
    USE SIGNAL ;
    PORT
      LAYER M4 ;
        RECT 172.7160 32.6400 172.8000 32.6640 ;
    END
  END m_hh[30]
  PIN m_hh[31]
    DIRECTION OUTPUT ;
    USE SIGNAL ;
    PORT
      LAYER M4 ;
        RECT 172.7160 33.5040 172.8000 33.5280 ;
    END
  END m_hh[31]
  PIN m_hh[32]
    DIRECTION OUTPUT ;
    USE SIGNAL ;
    PORT
      LAYER M4 ;
        RECT 172.7160 34.4640 172.8000 34.4880 ;
    END
  END m_hh[32]
  PIN m_hh[33]
    DIRECTION OUTPUT ;
    USE SIGNAL ;
    PORT
      LAYER M4 ;
        RECT 172.7160 35.3280 172.8000 35.3520 ;
    END
  END m_hh[33]
  PIN m_hh[34]
    DIRECTION OUTPUT ;
    USE SIGNAL ;
    PORT
      LAYER M4 ;
        RECT 172.7160 36.1920 172.8000 36.2160 ;
    END
  END m_hh[34]
  PIN m_hh[35]
    DIRECTION OUTPUT ;
    USE SIGNAL ;
    PORT
      LAYER M4 ;
        RECT 172.7160 37.0560 172.8000 37.0800 ;
    END
  END m_hh[35]
  PIN m_hh[36]
    DIRECTION OUTPUT ;
    USE SIGNAL ;
    PORT
      LAYER M4 ;
        RECT 172.7160 37.9200 172.8000 37.9440 ;
    END
  END m_hh[36]
  PIN m_hh[37]
    DIRECTION OUTPUT ;
    USE SIGNAL ;
    PORT
      LAYER M4 ;
        RECT 172.7160 38.7840 172.8000 38.8080 ;
    END
  END m_hh[37]
  PIN m_hh[38]
    DIRECTION OUTPUT ;
    USE SIGNAL ;
    PORT
      LAYER M4 ;
        RECT 172.7160 39.6480 172.8000 39.6720 ;
    END
  END m_hh[38]
  PIN m_hh[39]
    DIRECTION OUTPUT ;
    USE SIGNAL ;
    PORT
      LAYER M4 ;
        RECT 172.7160 40.5120 172.8000 40.5360 ;
    END
  END m_hh[39]
  PIN m_hh[3]
    DIRECTION OUTPUT ;
    USE SIGNAL ;
    PORT
      LAYER M4 ;
        RECT 172.7160 9.1200 172.8000 9.1440 ;
    END
  END m_hh[3]
  PIN m_hh[40]
    DIRECTION OUTPUT ;
    USE SIGNAL ;
    PORT
      LAYER M4 ;
        RECT 172.7160 41.3760 172.8000 41.4000 ;
    END
  END m_hh[40]
  PIN m_hh[41]
    DIRECTION OUTPUT ;
    USE SIGNAL ;
    PORT
      LAYER M4 ;
        RECT 172.7160 42.2400 172.8000 42.2640 ;
    END
  END m_hh[41]
  PIN m_hh[42]
    DIRECTION OUTPUT ;
    USE SIGNAL ;
    PORT
      LAYER M4 ;
        RECT 172.7160 43.2000 172.8000 43.2240 ;
    END
  END m_hh[42]
  PIN m_hh[43]
    DIRECTION OUTPUT ;
    USE SIGNAL ;
    PORT
      LAYER M4 ;
        RECT 172.7160 44.0640 172.8000 44.0880 ;
    END
  END m_hh[43]
  PIN m_hh[44]
    DIRECTION OUTPUT ;
    USE SIGNAL ;
    PORT
      LAYER M4 ;
        RECT 172.7160 44.9280 172.8000 44.9520 ;
    END
  END m_hh[44]
  PIN m_hh[45]
    DIRECTION OUTPUT ;
    USE SIGNAL ;
    PORT
      LAYER M4 ;
        RECT 172.7160 45.7920 172.8000 45.8160 ;
    END
  END m_hh[45]
  PIN m_hh[46]
    DIRECTION OUTPUT ;
    USE SIGNAL ;
    PORT
      LAYER M4 ;
        RECT 172.7160 46.6560 172.8000 46.6800 ;
    END
  END m_hh[46]
  PIN m_hh[47]
    DIRECTION OUTPUT ;
    USE SIGNAL ;
    PORT
      LAYER M4 ;
        RECT 172.7160 47.5200 172.8000 47.5440 ;
    END
  END m_hh[47]
  PIN m_hh[48]
    DIRECTION OUTPUT ;
    USE SIGNAL ;
    PORT
      LAYER M4 ;
        RECT 172.7160 48.3840 172.8000 48.4080 ;
    END
  END m_hh[48]
  PIN m_hh[49]
    DIRECTION OUTPUT ;
    USE SIGNAL ;
    PORT
      LAYER M4 ;
        RECT 172.7160 49.2480 172.8000 49.2720 ;
    END
  END m_hh[49]
  PIN m_hh[4]
    DIRECTION OUTPUT ;
    USE SIGNAL ;
    PORT
      LAYER M4 ;
        RECT 172.7160 9.9840 172.8000 10.0080 ;
    END
  END m_hh[4]
  PIN m_hh[50]
    DIRECTION OUTPUT ;
    USE SIGNAL ;
    PORT
      LAYER M4 ;
        RECT 172.7160 50.1120 172.8000 50.1360 ;
    END
  END m_hh[50]
  PIN m_hh[51]
    DIRECTION OUTPUT ;
    USE SIGNAL ;
    PORT
      LAYER M4 ;
        RECT 172.7160 50.9760 172.8000 51.0000 ;
    END
  END m_hh[51]
  PIN m_hh[52]
    DIRECTION OUTPUT ;
    USE SIGNAL ;
    PORT
      LAYER M4 ;
        RECT 172.7160 51.8400 172.8000 51.8640 ;
    END
  END m_hh[52]
  PIN m_hh[53]
    DIRECTION OUTPUT ;
    USE SIGNAL ;
    PORT
      LAYER M4 ;
        RECT 172.7160 52.8000 172.8000 52.8240 ;
    END
  END m_hh[53]
  PIN m_hh[54]
    DIRECTION OUTPUT ;
    USE SIGNAL ;
    PORT
      LAYER M4 ;
        RECT 172.7160 53.6640 172.8000 53.6880 ;
    END
  END m_hh[54]
  PIN m_hh[55]
    DIRECTION OUTPUT ;
    USE SIGNAL ;
    PORT
      LAYER M4 ;
        RECT 172.7160 54.5280 172.8000 54.5520 ;
    END
  END m_hh[55]
  PIN m_hh[56]
    DIRECTION OUTPUT ;
    USE SIGNAL ;
    PORT
      LAYER M4 ;
        RECT 172.7160 55.3920 172.8000 55.4160 ;
    END
  END m_hh[56]
  PIN m_hh[57]
    DIRECTION OUTPUT ;
    USE SIGNAL ;
    PORT
      LAYER M4 ;
        RECT 172.7160 56.2560 172.8000 56.2800 ;
    END
  END m_hh[57]
  PIN m_hh[58]
    DIRECTION OUTPUT ;
    USE SIGNAL ;
    PORT
      LAYER M4 ;
        RECT 172.7160 57.1200 172.8000 57.1440 ;
    END
  END m_hh[58]
  PIN m_hh[59]
    DIRECTION OUTPUT ;
    USE SIGNAL ;
    PORT
      LAYER M4 ;
        RECT 172.7160 57.9840 172.8000 58.0080 ;
    END
  END m_hh[59]
  PIN m_hh[5]
    DIRECTION OUTPUT ;
    USE SIGNAL ;
    PORT
      LAYER M4 ;
        RECT 172.7160 10.8480 172.8000 10.8720 ;
    END
  END m_hh[5]
  PIN m_hh[60]
    DIRECTION OUTPUT ;
    USE SIGNAL ;
    PORT
      LAYER M4 ;
        RECT 172.7160 58.8480 172.8000 58.8720 ;
    END
  END m_hh[60]
  PIN m_hh[61]
    DIRECTION OUTPUT ;
    USE SIGNAL ;
    PORT
      LAYER M4 ;
        RECT 172.7160 59.7120 172.8000 59.7360 ;
    END
  END m_hh[61]
  PIN m_hh[62]
    DIRECTION OUTPUT ;
    USE SIGNAL ;
    PORT
      LAYER M4 ;
        RECT 172.7160 60.5760 172.8000 60.6000 ;
    END
  END m_hh[62]
  PIN m_hh[63]
    DIRECTION OUTPUT ;
    USE SIGNAL ;
    PORT
      LAYER M4 ;
        RECT 172.7160 61.4400 172.8000 61.4640 ;
    END
  END m_hh[63]
  PIN m_hh[64]
    DIRECTION OUTPUT ;
    USE SIGNAL ;
    PORT
      LAYER M4 ;
        RECT 172.7160 62.4000 172.8000 62.4240 ;
    END
  END m_hh[64]
  PIN m_hh[65]
    DIRECTION OUTPUT ;
    USE SIGNAL ;
    PORT
      LAYER M4 ;
        RECT 172.7160 63.2640 172.8000 63.2880 ;
    END
  END m_hh[65]
  PIN m_hh[66]
    DIRECTION OUTPUT ;
    USE SIGNAL ;
    PORT
      LAYER M4 ;
        RECT 172.7160 64.1280 172.8000 64.1520 ;
    END
  END m_hh[66]
  PIN m_hh[67]
    DIRECTION OUTPUT ;
    USE SIGNAL ;
    PORT
      LAYER M4 ;
        RECT 172.7160 64.9920 172.8000 65.0160 ;
    END
  END m_hh[67]
  PIN m_hh[68]
    DIRECTION OUTPUT ;
    USE SIGNAL ;
    PORT
      LAYER M4 ;
        RECT 172.7160 65.8560 172.8000 65.8800 ;
    END
  END m_hh[68]
  PIN m_hh[69]
    DIRECTION OUTPUT ;
    USE SIGNAL ;
    PORT
      LAYER M4 ;
        RECT 172.7160 66.7200 172.8000 66.7440 ;
    END
  END m_hh[69]
  PIN m_hh[6]
    DIRECTION OUTPUT ;
    USE SIGNAL ;
    PORT
      LAYER M4 ;
        RECT 172.7160 11.7120 172.8000 11.7360 ;
    END
  END m_hh[6]
  PIN m_hh[70]
    DIRECTION OUTPUT ;
    USE SIGNAL ;
    PORT
      LAYER M4 ;
        RECT 172.7160 67.5840 172.8000 67.6080 ;
    END
  END m_hh[70]
  PIN m_hh[71]
    DIRECTION OUTPUT ;
    USE SIGNAL ;
    PORT
      LAYER M4 ;
        RECT 172.7160 68.4480 172.8000 68.4720 ;
    END
  END m_hh[71]
  PIN m_hh[72]
    DIRECTION OUTPUT ;
    USE SIGNAL ;
    PORT
      LAYER M4 ;
        RECT 172.7160 69.3120 172.8000 69.3360 ;
    END
  END m_hh[72]
  PIN m_hh[73]
    DIRECTION OUTPUT ;
    USE SIGNAL ;
    PORT
      LAYER M4 ;
        RECT 172.7160 70.1760 172.8000 70.2000 ;
    END
  END m_hh[73]
  PIN m_hh[74]
    DIRECTION OUTPUT ;
    USE SIGNAL ;
    PORT
      LAYER M4 ;
        RECT 172.7160 71.1360 172.8000 71.1600 ;
    END
  END m_hh[74]
  PIN m_hh[75]
    DIRECTION OUTPUT ;
    USE SIGNAL ;
    PORT
      LAYER M4 ;
        RECT 172.7160 72.0000 172.8000 72.0240 ;
    END
  END m_hh[75]
  PIN m_hh[76]
    DIRECTION OUTPUT ;
    USE SIGNAL ;
    PORT
      LAYER M4 ;
        RECT 172.7160 72.8640 172.8000 72.8880 ;
    END
  END m_hh[76]
  PIN m_hh[77]
    DIRECTION OUTPUT ;
    USE SIGNAL ;
    PORT
      LAYER M4 ;
        RECT 172.7160 73.7280 172.8000 73.7520 ;
    END
  END m_hh[77]
  PIN m_hh[78]
    DIRECTION OUTPUT ;
    USE SIGNAL ;
    PORT
      LAYER M4 ;
        RECT 172.7160 74.5920 172.8000 74.6160 ;
    END
  END m_hh[78]
  PIN m_hh[79]
    DIRECTION OUTPUT ;
    USE SIGNAL ;
    PORT
      LAYER M4 ;
        RECT 172.7160 75.4560 172.8000 75.4800 ;
    END
  END m_hh[79]
  PIN m_hh[7]
    DIRECTION OUTPUT ;
    USE SIGNAL ;
    PORT
      LAYER M4 ;
        RECT 172.7160 12.5760 172.8000 12.6000 ;
    END
  END m_hh[7]
  PIN m_hh[80]
    DIRECTION OUTPUT ;
    USE SIGNAL ;
    PORT
      LAYER M4 ;
        RECT 172.7160 76.3200 172.8000 76.3440 ;
    END
  END m_hh[80]
  PIN m_hh[81]
    DIRECTION OUTPUT ;
    USE SIGNAL ;
    PORT
      LAYER M4 ;
        RECT 172.7160 77.1840 172.8000 77.2080 ;
    END
  END m_hh[81]
  PIN m_hh[82]
    DIRECTION OUTPUT ;
    USE SIGNAL ;
    PORT
      LAYER M4 ;
        RECT 172.7160 78.0480 172.8000 78.0720 ;
    END
  END m_hh[82]
  PIN m_hh[83]
    DIRECTION OUTPUT ;
    USE SIGNAL ;
    PORT
      LAYER M4 ;
        RECT 172.7160 78.9120 172.8000 78.9360 ;
    END
  END m_hh[83]
  PIN m_hh[84]
    DIRECTION OUTPUT ;
    USE SIGNAL ;
    PORT
      LAYER M4 ;
        RECT 172.7160 79.7760 172.8000 79.8000 ;
    END
  END m_hh[84]
  PIN m_hh[85]
    DIRECTION OUTPUT ;
    USE SIGNAL ;
    PORT
      LAYER M4 ;
        RECT 172.7160 80.7360 172.8000 80.7600 ;
    END
  END m_hh[85]
  PIN m_hh[86]
    DIRECTION OUTPUT ;
    USE SIGNAL ;
    PORT
      LAYER M4 ;
        RECT 172.7160 81.6000 172.8000 81.6240 ;
    END
  END m_hh[86]
  PIN m_hh[87]
    DIRECTION OUTPUT ;
    USE SIGNAL ;
    PORT
      LAYER M4 ;
        RECT 172.7160 82.4640 172.8000 82.4880 ;
    END
  END m_hh[87]
  PIN m_hh[88]
    DIRECTION OUTPUT ;
    USE SIGNAL ;
    PORT
      LAYER M4 ;
        RECT 172.7160 83.3280 172.8000 83.3520 ;
    END
  END m_hh[88]
  PIN m_hh[89]
    DIRECTION OUTPUT ;
    USE SIGNAL ;
    PORT
      LAYER M4 ;
        RECT 172.7160 84.1920 172.8000 84.2160 ;
    END
  END m_hh[89]
  PIN m_hh[8]
    DIRECTION OUTPUT ;
    USE SIGNAL ;
    PORT
      LAYER M4 ;
        RECT 172.7160 13.4400 172.8000 13.4640 ;
    END
  END m_hh[8]
  PIN m_hh[90]
    DIRECTION OUTPUT ;
    USE SIGNAL ;
    PORT
      LAYER M4 ;
        RECT 172.7160 85.0560 172.8000 85.0800 ;
    END
  END m_hh[90]
  PIN m_hh[91]
    DIRECTION OUTPUT ;
    USE SIGNAL ;
    PORT
      LAYER M4 ;
        RECT 172.7160 85.9200 172.8000 85.9440 ;
    END
  END m_hh[91]
  PIN m_hh[92]
    DIRECTION OUTPUT ;
    USE SIGNAL ;
    PORT
      LAYER M4 ;
        RECT 172.7160 86.7840 172.8000 86.8080 ;
    END
  END m_hh[92]
  PIN m_hh[93]
    DIRECTION OUTPUT ;
    USE SIGNAL ;
    PORT
      LAYER M4 ;
        RECT 172.7160 87.6480 172.8000 87.6720 ;
    END
  END m_hh[93]
  PIN m_hh[94]
    DIRECTION OUTPUT ;
    USE SIGNAL ;
    PORT
      LAYER M4 ;
        RECT 172.7160 88.5120 172.8000 88.5360 ;
    END
  END m_hh[94]
  PIN m_hh[95]
    DIRECTION OUTPUT ;
    USE SIGNAL ;
    PORT
      LAYER M4 ;
        RECT 172.7160 89.3760 172.8000 89.4000 ;
    END
  END m_hh[95]
  PIN m_hh[96]
    DIRECTION OUTPUT ;
    USE SIGNAL ;
    PORT
      LAYER M4 ;
        RECT 172.7160 90.3360 172.8000 90.3600 ;
    END
  END m_hh[96]
  PIN m_hh[97]
    DIRECTION OUTPUT ;
    USE SIGNAL ;
    PORT
      LAYER M4 ;
        RECT 172.7160 91.2000 172.8000 91.2240 ;
    END
  END m_hh[97]
  PIN m_hh[98]
    DIRECTION OUTPUT ;
    USE SIGNAL ;
    PORT
      LAYER M4 ;
        RECT 172.7160 92.0640 172.8000 92.0880 ;
    END
  END m_hh[98]
  PIN m_hh[99]
    DIRECTION OUTPUT ;
    USE SIGNAL ;
    PORT
      LAYER M4 ;
        RECT 172.7160 92.9280 172.8000 92.9520 ;
    END
  END m_hh[99]
  PIN m_hh[9]
    DIRECTION OUTPUT ;
    USE SIGNAL ;
    PORT
      LAYER M4 ;
        RECT 172.7160 14.3040 172.8000 14.3280 ;
    END
  END m_hh[9]
  PIN m_kk[0]
    DIRECTION OUTPUT ;
    USE SIGNAL ;
    PORT
      LAYER M4 ;
        RECT 172.7160 118.2720 172.8000 118.2960 ;
    END
  END m_kk[0]
  PIN m_kk[100]
    DIRECTION OUTPUT ;
    USE SIGNAL ;
    PORT
      LAYER M4 ;
        RECT 172.7160 205.5360 172.8000 205.5600 ;
    END
  END m_kk[100]
  PIN m_kk[101]
    DIRECTION OUTPUT ;
    USE SIGNAL ;
    PORT
      LAYER M4 ;
        RECT 172.7160 206.4000 172.8000 206.4240 ;
    END
  END m_kk[101]
  PIN m_kk[102]
    DIRECTION OUTPUT ;
    USE SIGNAL ;
    PORT
      LAYER M4 ;
        RECT 172.7160 207.2640 172.8000 207.2880 ;
    END
  END m_kk[102]
  PIN m_kk[103]
    DIRECTION OUTPUT ;
    USE SIGNAL ;
    PORT
      LAYER M4 ;
        RECT 172.7160 208.1280 172.8000 208.1520 ;
    END
  END m_kk[103]
  PIN m_kk[104]
    DIRECTION OUTPUT ;
    USE SIGNAL ;
    PORT
      LAYER M4 ;
        RECT 172.7160 208.9920 172.8000 209.0160 ;
    END
  END m_kk[104]
  PIN m_kk[105]
    DIRECTION OUTPUT ;
    USE SIGNAL ;
    PORT
      LAYER M4 ;
        RECT 172.7160 209.8560 172.8000 209.8800 ;
    END
  END m_kk[105]
  PIN m_kk[106]
    DIRECTION OUTPUT ;
    USE SIGNAL ;
    PORT
      LAYER M4 ;
        RECT 172.7160 210.7200 172.8000 210.7440 ;
    END
  END m_kk[106]
  PIN m_kk[107]
    DIRECTION OUTPUT ;
    USE SIGNAL ;
    PORT
      LAYER M4 ;
        RECT 172.7160 211.6800 172.8000 211.7040 ;
    END
  END m_kk[107]
  PIN m_kk[108]
    DIRECTION OUTPUT ;
    USE SIGNAL ;
    PORT
      LAYER M4 ;
        RECT 172.7160 212.5440 172.8000 212.5680 ;
    END
  END m_kk[108]
  PIN m_kk[109]
    DIRECTION OUTPUT ;
    USE SIGNAL ;
    PORT
      LAYER M4 ;
        RECT 172.7160 213.4080 172.8000 213.4320 ;
    END
  END m_kk[109]
  PIN m_kk[10]
    DIRECTION OUTPUT ;
    USE SIGNAL ;
    PORT
      LAYER M4 ;
        RECT 172.7160 126.9120 172.8000 126.9360 ;
    END
  END m_kk[10]
  PIN m_kk[110]
    DIRECTION OUTPUT ;
    USE SIGNAL ;
    PORT
      LAYER M4 ;
        RECT 172.7160 214.2720 172.8000 214.2960 ;
    END
  END m_kk[110]
  PIN m_kk[111]
    DIRECTION OUTPUT ;
    USE SIGNAL ;
    PORT
      LAYER M4 ;
        RECT 172.7160 215.1360 172.8000 215.1600 ;
    END
  END m_kk[111]
  PIN m_kk[112]
    DIRECTION OUTPUT ;
    USE SIGNAL ;
    PORT
      LAYER M4 ;
        RECT 172.7160 216.0000 172.8000 216.0240 ;
    END
  END m_kk[112]
  PIN m_kk[113]
    DIRECTION OUTPUT ;
    USE SIGNAL ;
    PORT
      LAYER M4 ;
        RECT 172.7160 216.8640 172.8000 216.8880 ;
    END
  END m_kk[113]
  PIN m_kk[114]
    DIRECTION OUTPUT ;
    USE SIGNAL ;
    PORT
      LAYER M4 ;
        RECT 172.7160 217.7280 172.8000 217.7520 ;
    END
  END m_kk[114]
  PIN m_kk[115]
    DIRECTION OUTPUT ;
    USE SIGNAL ;
    PORT
      LAYER M4 ;
        RECT 172.7160 218.5920 172.8000 218.6160 ;
    END
  END m_kk[115]
  PIN m_kk[116]
    DIRECTION OUTPUT ;
    USE SIGNAL ;
    PORT
      LAYER M4 ;
        RECT 172.7160 219.4560 172.8000 219.4800 ;
    END
  END m_kk[116]
  PIN m_kk[117]
    DIRECTION OUTPUT ;
    USE SIGNAL ;
    PORT
      LAYER M4 ;
        RECT 172.7160 220.3200 172.8000 220.3440 ;
    END
  END m_kk[117]
  PIN m_kk[118]
    DIRECTION OUTPUT ;
    USE SIGNAL ;
    PORT
      LAYER M4 ;
        RECT 172.7160 221.2800 172.8000 221.3040 ;
    END
  END m_kk[118]
  PIN m_kk[119]
    DIRECTION OUTPUT ;
    USE SIGNAL ;
    PORT
      LAYER M4 ;
        RECT 172.7160 222.1440 172.8000 222.1680 ;
    END
  END m_kk[119]
  PIN m_kk[11]
    DIRECTION OUTPUT ;
    USE SIGNAL ;
    PORT
      LAYER M4 ;
        RECT 172.7160 127.8720 172.8000 127.8960 ;
    END
  END m_kk[11]
  PIN m_kk[120]
    DIRECTION OUTPUT ;
    USE SIGNAL ;
    PORT
      LAYER M4 ;
        RECT 172.7160 223.0080 172.8000 223.0320 ;
    END
  END m_kk[120]
  PIN m_kk[121]
    DIRECTION OUTPUT ;
    USE SIGNAL ;
    PORT
      LAYER M4 ;
        RECT 172.7160 223.8720 172.8000 223.8960 ;
    END
  END m_kk[121]
  PIN m_kk[122]
    DIRECTION OUTPUT ;
    USE SIGNAL ;
    PORT
      LAYER M4 ;
        RECT 172.7160 224.7360 172.8000 224.7600 ;
    END
  END m_kk[122]
  PIN m_kk[123]
    DIRECTION OUTPUT ;
    USE SIGNAL ;
    PORT
      LAYER M4 ;
        RECT 172.7160 225.6000 172.8000 225.6240 ;
    END
  END m_kk[123]
  PIN m_kk[124]
    DIRECTION OUTPUT ;
    USE SIGNAL ;
    PORT
      LAYER M4 ;
        RECT 172.7160 226.4640 172.8000 226.4880 ;
    END
  END m_kk[124]
  PIN m_kk[125]
    DIRECTION OUTPUT ;
    USE SIGNAL ;
    PORT
      LAYER M4 ;
        RECT 172.7160 227.3280 172.8000 227.3520 ;
    END
  END m_kk[125]
  PIN m_kk[126]
    DIRECTION OUTPUT ;
    USE SIGNAL ;
    PORT
      LAYER M4 ;
        RECT 172.7160 228.1920 172.8000 228.2160 ;
    END
  END m_kk[126]
  PIN m_kk[127]
    DIRECTION OUTPUT ;
    USE SIGNAL ;
    PORT
      LAYER M4 ;
        RECT 172.7160 229.0560 172.8000 229.0800 ;
    END
  END m_kk[127]
  PIN m_kk[12]
    DIRECTION OUTPUT ;
    USE SIGNAL ;
    PORT
      LAYER M4 ;
        RECT 172.7160 128.7360 172.8000 128.7600 ;
    END
  END m_kk[12]
  PIN m_kk[13]
    DIRECTION OUTPUT ;
    USE SIGNAL ;
    PORT
      LAYER M4 ;
        RECT 172.7160 129.6000 172.8000 129.6240 ;
    END
  END m_kk[13]
  PIN m_kk[14]
    DIRECTION OUTPUT ;
    USE SIGNAL ;
    PORT
      LAYER M4 ;
        RECT 172.7160 130.4640 172.8000 130.4880 ;
    END
  END m_kk[14]
  PIN m_kk[15]
    DIRECTION OUTPUT ;
    USE SIGNAL ;
    PORT
      LAYER M4 ;
        RECT 172.7160 131.3280 172.8000 131.3520 ;
    END
  END m_kk[15]
  PIN m_kk[16]
    DIRECTION OUTPUT ;
    USE SIGNAL ;
    PORT
      LAYER M4 ;
        RECT 172.7160 132.1920 172.8000 132.2160 ;
    END
  END m_kk[16]
  PIN m_kk[17]
    DIRECTION OUTPUT ;
    USE SIGNAL ;
    PORT
      LAYER M4 ;
        RECT 172.7160 133.0560 172.8000 133.0800 ;
    END
  END m_kk[17]
  PIN m_kk[18]
    DIRECTION OUTPUT ;
    USE SIGNAL ;
    PORT
      LAYER M4 ;
        RECT 172.7160 133.9200 172.8000 133.9440 ;
    END
  END m_kk[18]
  PIN m_kk[19]
    DIRECTION OUTPUT ;
    USE SIGNAL ;
    PORT
      LAYER M4 ;
        RECT 172.7160 134.7840 172.8000 134.8080 ;
    END
  END m_kk[19]
  PIN m_kk[1]
    DIRECTION OUTPUT ;
    USE SIGNAL ;
    PORT
      LAYER M4 ;
        RECT 172.7160 119.1360 172.8000 119.1600 ;
    END
  END m_kk[1]
  PIN m_kk[20]
    DIRECTION OUTPUT ;
    USE SIGNAL ;
    PORT
      LAYER M4 ;
        RECT 172.7160 135.6480 172.8000 135.6720 ;
    END
  END m_kk[20]
  PIN m_kk[21]
    DIRECTION OUTPUT ;
    USE SIGNAL ;
    PORT
      LAYER M4 ;
        RECT 172.7160 136.6080 172.8000 136.6320 ;
    END
  END m_kk[21]
  PIN m_kk[22]
    DIRECTION OUTPUT ;
    USE SIGNAL ;
    PORT
      LAYER M4 ;
        RECT 172.7160 137.4720 172.8000 137.4960 ;
    END
  END m_kk[22]
  PIN m_kk[23]
    DIRECTION OUTPUT ;
    USE SIGNAL ;
    PORT
      LAYER M4 ;
        RECT 172.7160 138.3360 172.8000 138.3600 ;
    END
  END m_kk[23]
  PIN m_kk[24]
    DIRECTION OUTPUT ;
    USE SIGNAL ;
    PORT
      LAYER M4 ;
        RECT 172.7160 139.2000 172.8000 139.2240 ;
    END
  END m_kk[24]
  PIN m_kk[25]
    DIRECTION OUTPUT ;
    USE SIGNAL ;
    PORT
      LAYER M4 ;
        RECT 172.7160 140.0640 172.8000 140.0880 ;
    END
  END m_kk[25]
  PIN m_kk[26]
    DIRECTION OUTPUT ;
    USE SIGNAL ;
    PORT
      LAYER M4 ;
        RECT 172.7160 140.9280 172.8000 140.9520 ;
    END
  END m_kk[26]
  PIN m_kk[27]
    DIRECTION OUTPUT ;
    USE SIGNAL ;
    PORT
      LAYER M4 ;
        RECT 172.7160 141.7920 172.8000 141.8160 ;
    END
  END m_kk[27]
  PIN m_kk[28]
    DIRECTION OUTPUT ;
    USE SIGNAL ;
    PORT
      LAYER M4 ;
        RECT 172.7160 142.6560 172.8000 142.6800 ;
    END
  END m_kk[28]
  PIN m_kk[29]
    DIRECTION OUTPUT ;
    USE SIGNAL ;
    PORT
      LAYER M4 ;
        RECT 172.7160 143.5200 172.8000 143.5440 ;
    END
  END m_kk[29]
  PIN m_kk[2]
    DIRECTION OUTPUT ;
    USE SIGNAL ;
    PORT
      LAYER M4 ;
        RECT 172.7160 120.0000 172.8000 120.0240 ;
    END
  END m_kk[2]
  PIN m_kk[30]
    DIRECTION OUTPUT ;
    USE SIGNAL ;
    PORT
      LAYER M4 ;
        RECT 172.7160 144.3840 172.8000 144.4080 ;
    END
  END m_kk[30]
  PIN m_kk[31]
    DIRECTION OUTPUT ;
    USE SIGNAL ;
    PORT
      LAYER M4 ;
        RECT 172.7160 145.2480 172.8000 145.2720 ;
    END
  END m_kk[31]
  PIN m_kk[32]
    DIRECTION OUTPUT ;
    USE SIGNAL ;
    PORT
      LAYER M4 ;
        RECT 172.7160 146.2080 172.8000 146.2320 ;
    END
  END m_kk[32]
  PIN m_kk[33]
    DIRECTION OUTPUT ;
    USE SIGNAL ;
    PORT
      LAYER M4 ;
        RECT 172.7160 147.0720 172.8000 147.0960 ;
    END
  END m_kk[33]
  PIN m_kk[34]
    DIRECTION OUTPUT ;
    USE SIGNAL ;
    PORT
      LAYER M4 ;
        RECT 172.7160 147.9360 172.8000 147.9600 ;
    END
  END m_kk[34]
  PIN m_kk[35]
    DIRECTION OUTPUT ;
    USE SIGNAL ;
    PORT
      LAYER M4 ;
        RECT 172.7160 148.8000 172.8000 148.8240 ;
    END
  END m_kk[35]
  PIN m_kk[36]
    DIRECTION OUTPUT ;
    USE SIGNAL ;
    PORT
      LAYER M4 ;
        RECT 172.7160 149.6640 172.8000 149.6880 ;
    END
  END m_kk[36]
  PIN m_kk[37]
    DIRECTION OUTPUT ;
    USE SIGNAL ;
    PORT
      LAYER M4 ;
        RECT 172.7160 150.5280 172.8000 150.5520 ;
    END
  END m_kk[37]
  PIN m_kk[38]
    DIRECTION OUTPUT ;
    USE SIGNAL ;
    PORT
      LAYER M4 ;
        RECT 172.7160 151.3920 172.8000 151.4160 ;
    END
  END m_kk[38]
  PIN m_kk[39]
    DIRECTION OUTPUT ;
    USE SIGNAL ;
    PORT
      LAYER M4 ;
        RECT 172.7160 152.2560 172.8000 152.2800 ;
    END
  END m_kk[39]
  PIN m_kk[3]
    DIRECTION OUTPUT ;
    USE SIGNAL ;
    PORT
      LAYER M4 ;
        RECT 172.7160 120.8640 172.8000 120.8880 ;
    END
  END m_kk[3]
  PIN m_kk[40]
    DIRECTION OUTPUT ;
    USE SIGNAL ;
    PORT
      LAYER M4 ;
        RECT 172.7160 153.1200 172.8000 153.1440 ;
    END
  END m_kk[40]
  PIN m_kk[41]
    DIRECTION OUTPUT ;
    USE SIGNAL ;
    PORT
      LAYER M4 ;
        RECT 172.7160 153.9840 172.8000 154.0080 ;
    END
  END m_kk[41]
  PIN m_kk[42]
    DIRECTION OUTPUT ;
    USE SIGNAL ;
    PORT
      LAYER M4 ;
        RECT 172.7160 154.8480 172.8000 154.8720 ;
    END
  END m_kk[42]
  PIN m_kk[43]
    DIRECTION OUTPUT ;
    USE SIGNAL ;
    PORT
      LAYER M4 ;
        RECT 172.7160 155.8080 172.8000 155.8320 ;
    END
  END m_kk[43]
  PIN m_kk[44]
    DIRECTION OUTPUT ;
    USE SIGNAL ;
    PORT
      LAYER M4 ;
        RECT 172.7160 156.6720 172.8000 156.6960 ;
    END
  END m_kk[44]
  PIN m_kk[45]
    DIRECTION OUTPUT ;
    USE SIGNAL ;
    PORT
      LAYER M4 ;
        RECT 172.7160 157.5360 172.8000 157.5600 ;
    END
  END m_kk[45]
  PIN m_kk[46]
    DIRECTION OUTPUT ;
    USE SIGNAL ;
    PORT
      LAYER M4 ;
        RECT 172.7160 158.4000 172.8000 158.4240 ;
    END
  END m_kk[46]
  PIN m_kk[47]
    DIRECTION OUTPUT ;
    USE SIGNAL ;
    PORT
      LAYER M4 ;
        RECT 172.7160 159.2640 172.8000 159.2880 ;
    END
  END m_kk[47]
  PIN m_kk[48]
    DIRECTION OUTPUT ;
    USE SIGNAL ;
    PORT
      LAYER M4 ;
        RECT 172.7160 160.1280 172.8000 160.1520 ;
    END
  END m_kk[48]
  PIN m_kk[49]
    DIRECTION OUTPUT ;
    USE SIGNAL ;
    PORT
      LAYER M4 ;
        RECT 172.7160 160.9920 172.8000 161.0160 ;
    END
  END m_kk[49]
  PIN m_kk[4]
    DIRECTION OUTPUT ;
    USE SIGNAL ;
    PORT
      LAYER M4 ;
        RECT 172.7160 121.7280 172.8000 121.7520 ;
    END
  END m_kk[4]
  PIN m_kk[50]
    DIRECTION OUTPUT ;
    USE SIGNAL ;
    PORT
      LAYER M4 ;
        RECT 172.7160 161.8560 172.8000 161.8800 ;
    END
  END m_kk[50]
  PIN m_kk[51]
    DIRECTION OUTPUT ;
    USE SIGNAL ;
    PORT
      LAYER M4 ;
        RECT 172.7160 162.7200 172.8000 162.7440 ;
    END
  END m_kk[51]
  PIN m_kk[52]
    DIRECTION OUTPUT ;
    USE SIGNAL ;
    PORT
      LAYER M4 ;
        RECT 172.7160 163.5840 172.8000 163.6080 ;
    END
  END m_kk[52]
  PIN m_kk[53]
    DIRECTION OUTPUT ;
    USE SIGNAL ;
    PORT
      LAYER M4 ;
        RECT 172.7160 164.4480 172.8000 164.4720 ;
    END
  END m_kk[53]
  PIN m_kk[54]
    DIRECTION OUTPUT ;
    USE SIGNAL ;
    PORT
      LAYER M4 ;
        RECT 172.7160 165.4080 172.8000 165.4320 ;
    END
  END m_kk[54]
  PIN m_kk[55]
    DIRECTION OUTPUT ;
    USE SIGNAL ;
    PORT
      LAYER M4 ;
        RECT 172.7160 166.2720 172.8000 166.2960 ;
    END
  END m_kk[55]
  PIN m_kk[56]
    DIRECTION OUTPUT ;
    USE SIGNAL ;
    PORT
      LAYER M4 ;
        RECT 172.7160 167.1360 172.8000 167.1600 ;
    END
  END m_kk[56]
  PIN m_kk[57]
    DIRECTION OUTPUT ;
    USE SIGNAL ;
    PORT
      LAYER M4 ;
        RECT 172.7160 168.0000 172.8000 168.0240 ;
    END
  END m_kk[57]
  PIN m_kk[58]
    DIRECTION OUTPUT ;
    USE SIGNAL ;
    PORT
      LAYER M4 ;
        RECT 172.7160 168.8640 172.8000 168.8880 ;
    END
  END m_kk[58]
  PIN m_kk[59]
    DIRECTION OUTPUT ;
    USE SIGNAL ;
    PORT
      LAYER M4 ;
        RECT 172.7160 169.7280 172.8000 169.7520 ;
    END
  END m_kk[59]
  PIN m_kk[5]
    DIRECTION OUTPUT ;
    USE SIGNAL ;
    PORT
      LAYER M4 ;
        RECT 172.7160 122.5920 172.8000 122.6160 ;
    END
  END m_kk[5]
  PIN m_kk[60]
    DIRECTION OUTPUT ;
    USE SIGNAL ;
    PORT
      LAYER M4 ;
        RECT 172.7160 170.5920 172.8000 170.6160 ;
    END
  END m_kk[60]
  PIN m_kk[61]
    DIRECTION OUTPUT ;
    USE SIGNAL ;
    PORT
      LAYER M4 ;
        RECT 172.7160 171.4560 172.8000 171.4800 ;
    END
  END m_kk[61]
  PIN m_kk[62]
    DIRECTION OUTPUT ;
    USE SIGNAL ;
    PORT
      LAYER M4 ;
        RECT 172.7160 172.3200 172.8000 172.3440 ;
    END
  END m_kk[62]
  PIN m_kk[63]
    DIRECTION OUTPUT ;
    USE SIGNAL ;
    PORT
      LAYER M4 ;
        RECT 172.7160 173.1840 172.8000 173.2080 ;
    END
  END m_kk[63]
  PIN m_kk[64]
    DIRECTION OUTPUT ;
    USE SIGNAL ;
    PORT
      LAYER M4 ;
        RECT 172.7160 174.1440 172.8000 174.1680 ;
    END
  END m_kk[64]
  PIN m_kk[65]
    DIRECTION OUTPUT ;
    USE SIGNAL ;
    PORT
      LAYER M4 ;
        RECT 172.7160 175.0080 172.8000 175.0320 ;
    END
  END m_kk[65]
  PIN m_kk[66]
    DIRECTION OUTPUT ;
    USE SIGNAL ;
    PORT
      LAYER M4 ;
        RECT 172.7160 175.8720 172.8000 175.8960 ;
    END
  END m_kk[66]
  PIN m_kk[67]
    DIRECTION OUTPUT ;
    USE SIGNAL ;
    PORT
      LAYER M4 ;
        RECT 172.7160 176.7360 172.8000 176.7600 ;
    END
  END m_kk[67]
  PIN m_kk[68]
    DIRECTION OUTPUT ;
    USE SIGNAL ;
    PORT
      LAYER M4 ;
        RECT 172.7160 177.6000 172.8000 177.6240 ;
    END
  END m_kk[68]
  PIN m_kk[69]
    DIRECTION OUTPUT ;
    USE SIGNAL ;
    PORT
      LAYER M4 ;
        RECT 172.7160 178.4640 172.8000 178.4880 ;
    END
  END m_kk[69]
  PIN m_kk[6]
    DIRECTION OUTPUT ;
    USE SIGNAL ;
    PORT
      LAYER M4 ;
        RECT 172.7160 123.4560 172.8000 123.4800 ;
    END
  END m_kk[6]
  PIN m_kk[70]
    DIRECTION OUTPUT ;
    USE SIGNAL ;
    PORT
      LAYER M4 ;
        RECT 172.7160 179.3280 172.8000 179.3520 ;
    END
  END m_kk[70]
  PIN m_kk[71]
    DIRECTION OUTPUT ;
    USE SIGNAL ;
    PORT
      LAYER M4 ;
        RECT 172.7160 180.1920 172.8000 180.2160 ;
    END
  END m_kk[71]
  PIN m_kk[72]
    DIRECTION OUTPUT ;
    USE SIGNAL ;
    PORT
      LAYER M4 ;
        RECT 172.7160 181.0560 172.8000 181.0800 ;
    END
  END m_kk[72]
  PIN m_kk[73]
    DIRECTION OUTPUT ;
    USE SIGNAL ;
    PORT
      LAYER M4 ;
        RECT 172.7160 181.9200 172.8000 181.9440 ;
    END
  END m_kk[73]
  PIN m_kk[74]
    DIRECTION OUTPUT ;
    USE SIGNAL ;
    PORT
      LAYER M4 ;
        RECT 172.7160 182.7840 172.8000 182.8080 ;
    END
  END m_kk[74]
  PIN m_kk[75]
    DIRECTION OUTPUT ;
    USE SIGNAL ;
    PORT
      LAYER M4 ;
        RECT 172.7160 183.7440 172.8000 183.7680 ;
    END
  END m_kk[75]
  PIN m_kk[76]
    DIRECTION OUTPUT ;
    USE SIGNAL ;
    PORT
      LAYER M4 ;
        RECT 172.7160 184.6080 172.8000 184.6320 ;
    END
  END m_kk[76]
  PIN m_kk[77]
    DIRECTION OUTPUT ;
    USE SIGNAL ;
    PORT
      LAYER M4 ;
        RECT 172.7160 185.4720 172.8000 185.4960 ;
    END
  END m_kk[77]
  PIN m_kk[78]
    DIRECTION OUTPUT ;
    USE SIGNAL ;
    PORT
      LAYER M4 ;
        RECT 172.7160 186.3360 172.8000 186.3600 ;
    END
  END m_kk[78]
  PIN m_kk[79]
    DIRECTION OUTPUT ;
    USE SIGNAL ;
    PORT
      LAYER M4 ;
        RECT 172.7160 187.2000 172.8000 187.2240 ;
    END
  END m_kk[79]
  PIN m_kk[7]
    DIRECTION OUTPUT ;
    USE SIGNAL ;
    PORT
      LAYER M4 ;
        RECT 172.7160 124.3200 172.8000 124.3440 ;
    END
  END m_kk[7]
  PIN m_kk[80]
    DIRECTION OUTPUT ;
    USE SIGNAL ;
    PORT
      LAYER M4 ;
        RECT 172.7160 188.0640 172.8000 188.0880 ;
    END
  END m_kk[80]
  PIN m_kk[81]
    DIRECTION OUTPUT ;
    USE SIGNAL ;
    PORT
      LAYER M4 ;
        RECT 172.7160 188.9280 172.8000 188.9520 ;
    END
  END m_kk[81]
  PIN m_kk[82]
    DIRECTION OUTPUT ;
    USE SIGNAL ;
    PORT
      LAYER M4 ;
        RECT 172.7160 189.7920 172.8000 189.8160 ;
    END
  END m_kk[82]
  PIN m_kk[83]
    DIRECTION OUTPUT ;
    USE SIGNAL ;
    PORT
      LAYER M4 ;
        RECT 172.7160 190.6560 172.8000 190.6800 ;
    END
  END m_kk[83]
  PIN m_kk[84]
    DIRECTION OUTPUT ;
    USE SIGNAL ;
    PORT
      LAYER M4 ;
        RECT 172.7160 191.5200 172.8000 191.5440 ;
    END
  END m_kk[84]
  PIN m_kk[85]
    DIRECTION OUTPUT ;
    USE SIGNAL ;
    PORT
      LAYER M4 ;
        RECT 172.7160 192.3840 172.8000 192.4080 ;
    END
  END m_kk[85]
  PIN m_kk[86]
    DIRECTION OUTPUT ;
    USE SIGNAL ;
    PORT
      LAYER M4 ;
        RECT 172.7160 193.3440 172.8000 193.3680 ;
    END
  END m_kk[86]
  PIN m_kk[87]
    DIRECTION OUTPUT ;
    USE SIGNAL ;
    PORT
      LAYER M4 ;
        RECT 172.7160 194.2080 172.8000 194.2320 ;
    END
  END m_kk[87]
  PIN m_kk[88]
    DIRECTION OUTPUT ;
    USE SIGNAL ;
    PORT
      LAYER M4 ;
        RECT 172.7160 195.0720 172.8000 195.0960 ;
    END
  END m_kk[88]
  PIN m_kk[89]
    DIRECTION OUTPUT ;
    USE SIGNAL ;
    PORT
      LAYER M4 ;
        RECT 172.7160 195.9360 172.8000 195.9600 ;
    END
  END m_kk[89]
  PIN m_kk[8]
    DIRECTION OUTPUT ;
    USE SIGNAL ;
    PORT
      LAYER M4 ;
        RECT 172.7160 125.1840 172.8000 125.2080 ;
    END
  END m_kk[8]
  PIN m_kk[90]
    DIRECTION OUTPUT ;
    USE SIGNAL ;
    PORT
      LAYER M4 ;
        RECT 172.7160 196.8000 172.8000 196.8240 ;
    END
  END m_kk[90]
  PIN m_kk[91]
    DIRECTION OUTPUT ;
    USE SIGNAL ;
    PORT
      LAYER M4 ;
        RECT 172.7160 197.6640 172.8000 197.6880 ;
    END
  END m_kk[91]
  PIN m_kk[92]
    DIRECTION OUTPUT ;
    USE SIGNAL ;
    PORT
      LAYER M4 ;
        RECT 172.7160 198.5280 172.8000 198.5520 ;
    END
  END m_kk[92]
  PIN m_kk[93]
    DIRECTION OUTPUT ;
    USE SIGNAL ;
    PORT
      LAYER M4 ;
        RECT 172.7160 199.3920 172.8000 199.4160 ;
    END
  END m_kk[93]
  PIN m_kk[94]
    DIRECTION OUTPUT ;
    USE SIGNAL ;
    PORT
      LAYER M4 ;
        RECT 172.7160 200.2560 172.8000 200.2800 ;
    END
  END m_kk[94]
  PIN m_kk[95]
    DIRECTION OUTPUT ;
    USE SIGNAL ;
    PORT
      LAYER M4 ;
        RECT 172.7160 201.1200 172.8000 201.1440 ;
    END
  END m_kk[95]
  PIN m_kk[96]
    DIRECTION OUTPUT ;
    USE SIGNAL ;
    PORT
      LAYER M4 ;
        RECT 172.7160 201.9840 172.8000 202.0080 ;
    END
  END m_kk[96]
  PIN m_kk[97]
    DIRECTION OUTPUT ;
    USE SIGNAL ;
    PORT
      LAYER M4 ;
        RECT 172.7160 202.9440 172.8000 202.9680 ;
    END
  END m_kk[97]
  PIN m_kk[98]
    DIRECTION OUTPUT ;
    USE SIGNAL ;
    PORT
      LAYER M4 ;
        RECT 172.7160 203.8080 172.8000 203.8320 ;
    END
  END m_kk[98]
  PIN m_kk[99]
    DIRECTION OUTPUT ;
    USE SIGNAL ;
    PORT
      LAYER M4 ;
        RECT 172.7160 204.6720 172.8000 204.6960 ;
    END
  END m_kk[99]
  PIN m_kk[9]
    DIRECTION OUTPUT ;
    USE SIGNAL ;
    PORT
      LAYER M4 ;
        RECT 172.7160 126.0480 172.8000 126.0720 ;
    END
  END m_kk[9]
  PIN m_pre
    DIRECTION OUTPUT ;
    USE SIGNAL ;
    PORT
      LAYER M4 ;
        RECT 172.7160 5.6640 172.8000 5.6880 ;
    END
  END m_pre
  PIN m_v
    DIRECTION OUTPUT ;
    USE SIGNAL ;
    PORT
      LAYER M4 ;
        RECT 172.7160 4.7040 172.8000 4.7280 ;
    END
  END m_v
  PIN o_c[0]
    DIRECTION OUTPUT ;
    USE SIGNAL ;
    PORT
      LAYER M3 ;
        RECT 28.8000 0.0000 28.8180 0.0380 ;
    END
  END o_c[0]
  PIN o_c[1]
    DIRECTION OUTPUT ;
    USE SIGNAL ;
    PORT
      LAYER M5 ;
        RECT 28.6080 0.0000 28.6320 0.0840 ;
    END
  END o_c[1]
  PIN o_v
    DIRECTION OUTPUT ;
    USE SIGNAL ;
    PORT
      LAYER M5 ;
        RECT 28.9920 0.0000 29.0160 0.0840 ;
    END
  END o_v
  PIN o_y[0]
    DIRECTION OUTPUT ;
    USE SIGNAL ;
    PORT
      LAYER M3 ;
        RECT 28.3680 0.0000 28.3860 0.0380 ;
    END
  END o_y[0]
  PIN o_y[100]
    DIRECTION OUTPUT ;
    USE SIGNAL ;
    PORT
      LAYER M3 ;
        RECT 9.6480 0.0000 9.6660 0.0380 ;
    END
  END o_y[100]
  PIN o_y[101]
    DIRECTION OUTPUT ;
    USE SIGNAL ;
    PORT
      LAYER M5 ;
        RECT 9.5040 0.0000 9.5280 0.0840 ;
    END
  END o_y[101]
  PIN o_y[102]
    DIRECTION OUTPUT ;
    USE SIGNAL ;
    PORT
      LAYER M3 ;
        RECT 9.2880 0.0000 9.3060 0.0380 ;
    END
  END o_y[102]
  PIN o_y[103]
    DIRECTION OUTPUT ;
    USE SIGNAL ;
    PORT
      LAYER M5 ;
        RECT 9.1200 0.0000 9.1440 0.0840 ;
    END
  END o_y[103]
  PIN o_y[104]
    DIRECTION OUTPUT ;
    USE SIGNAL ;
    PORT
      LAYER M3 ;
        RECT 8.9280 0.0000 8.9460 0.0380 ;
    END
  END o_y[104]
  PIN o_y[105]
    DIRECTION OUTPUT ;
    USE SIGNAL ;
    PORT
      LAYER M5 ;
        RECT 8.7360 0.0000 8.7600 0.0840 ;
    END
  END o_y[105]
  PIN o_y[106]
    DIRECTION OUTPUT ;
    USE SIGNAL ;
    PORT
      LAYER M3 ;
        RECT 8.4960 0.0000 8.5140 0.0380 ;
    END
  END o_y[106]
  PIN o_y[107]
    DIRECTION OUTPUT ;
    USE SIGNAL ;
    PORT
      LAYER M5 ;
        RECT 8.3520 0.0000 8.3760 0.0840 ;
    END
  END o_y[107]
  PIN o_y[108]
    DIRECTION OUTPUT ;
    USE SIGNAL ;
    PORT
      LAYER M3 ;
        RECT 8.1360 0.0000 8.1540 0.0380 ;
    END
  END o_y[108]
  PIN o_y[109]
    DIRECTION OUTPUT ;
    USE SIGNAL ;
    PORT
      LAYER M5 ;
        RECT 7.9680 0.0000 7.9920 0.0840 ;
    END
  END o_y[109]
  PIN o_y[10]
    DIRECTION OUTPUT ;
    USE SIGNAL ;
    PORT
      LAYER M3 ;
        RECT 26.4960 0.0000 26.5140 0.0380 ;
    END
  END o_y[10]
  PIN o_y[110]
    DIRECTION OUTPUT ;
    USE SIGNAL ;
    PORT
      LAYER M3 ;
        RECT 7.7760 0.0000 7.7940 0.0380 ;
    END
  END o_y[110]
  PIN o_y[111]
    DIRECTION OUTPUT ;
    USE SIGNAL ;
    PORT
      LAYER M5 ;
        RECT 7.5840 0.0000 7.6080 0.0840 ;
    END
  END o_y[111]
  PIN o_y[112]
    DIRECTION OUTPUT ;
    USE SIGNAL ;
    PORT
      LAYER M3 ;
        RECT 7.4160 0.0000 7.4340 0.0380 ;
    END
  END o_y[112]
  PIN o_y[113]
    DIRECTION OUTPUT ;
    USE SIGNAL ;
    PORT
      LAYER M5 ;
        RECT 7.2000 0.0000 7.2240 0.0840 ;
    END
  END o_y[113]
  PIN o_y[114]
    DIRECTION OUTPUT ;
    USE SIGNAL ;
    PORT
      LAYER M3 ;
        RECT 7.0560 0.0000 7.0740 0.0380 ;
    END
  END o_y[114]
  PIN o_y[115]
    DIRECTION OUTPUT ;
    USE SIGNAL ;
    PORT
      LAYER M5 ;
        RECT 6.8160 0.0000 6.8400 0.0840 ;
    END
  END o_y[115]
  PIN o_y[116]
    DIRECTION OUTPUT ;
    USE SIGNAL ;
    PORT
      LAYER M3 ;
        RECT 6.6240 0.0000 6.6420 0.0380 ;
    END
  END o_y[116]
  PIN o_y[117]
    DIRECTION OUTPUT ;
    USE SIGNAL ;
    PORT
      LAYER M5 ;
        RECT 6.4320 0.0000 6.4560 0.0840 ;
    END
  END o_y[117]
  PIN o_y[118]
    DIRECTION OUTPUT ;
    USE SIGNAL ;
    PORT
      LAYER M3 ;
        RECT 6.2640 0.0000 6.2820 0.0380 ;
    END
  END o_y[118]
  PIN o_y[119]
    DIRECTION OUTPUT ;
    USE SIGNAL ;
    PORT
      LAYER M5 ;
        RECT 6.0480 0.0000 6.0720 0.0840 ;
    END
  END o_y[119]
  PIN o_y[11]
    DIRECTION OUTPUT ;
    USE SIGNAL ;
    PORT
      LAYER M5 ;
        RECT 26.3040 0.0000 26.3280 0.0840 ;
    END
  END o_y[11]
  PIN o_y[120]
    DIRECTION OUTPUT ;
    USE SIGNAL ;
    PORT
      LAYER M3 ;
        RECT 5.9040 0.0000 5.9220 0.0380 ;
    END
  END o_y[120]
  PIN o_y[121]
    DIRECTION OUTPUT ;
    USE SIGNAL ;
    PORT
      LAYER M5 ;
        RECT 5.7600 0.0000 5.7840 0.0840 ;
    END
  END o_y[121]
  PIN o_y[122]
    DIRECTION OUTPUT ;
    USE SIGNAL ;
    PORT
      LAYER M3 ;
        RECT 5.5440 0.0000 5.5620 0.0380 ;
    END
  END o_y[122]
  PIN o_y[123]
    DIRECTION OUTPUT ;
    USE SIGNAL ;
    PORT
      LAYER M5 ;
        RECT 5.3760 0.0000 5.4000 0.0840 ;
    END
  END o_y[123]
  PIN o_y[124]
    DIRECTION OUTPUT ;
    USE SIGNAL ;
    PORT
      LAYER M3 ;
        RECT 5.1840 0.0000 5.2020 0.0380 ;
    END
  END o_y[124]
  PIN o_y[125]
    DIRECTION OUTPUT ;
    USE SIGNAL ;
    PORT
      LAYER M5 ;
        RECT 4.9920 0.0000 5.0160 0.0840 ;
    END
  END o_y[125]
  PIN o_y[126]
    DIRECTION OUTPUT ;
    USE SIGNAL ;
    PORT
      LAYER M3 ;
        RECT 4.7520 0.0000 4.7700 0.0380 ;
    END
  END o_y[126]
  PIN o_y[127]
    DIRECTION OUTPUT ;
    USE SIGNAL ;
    PORT
      LAYER M5 ;
        RECT 4.6080 0.0000 4.6320 0.0840 ;
    END
  END o_y[127]
  PIN o_y[12]
    DIRECTION OUTPUT ;
    USE SIGNAL ;
    PORT
      LAYER M3 ;
        RECT 26.1360 0.0000 26.1540 0.0380 ;
    END
  END o_y[12]
  PIN o_y[13]
    DIRECTION OUTPUT ;
    USE SIGNAL ;
    PORT
      LAYER M5 ;
        RECT 25.9200 0.0000 25.9440 0.0840 ;
    END
  END o_y[13]
  PIN o_y[14]
    DIRECTION OUTPUT ;
    USE SIGNAL ;
    PORT
      LAYER M3 ;
        RECT 25.7760 0.0000 25.7940 0.0380 ;
    END
  END o_y[14]
  PIN o_y[15]
    DIRECTION OUTPUT ;
    USE SIGNAL ;
    PORT
      LAYER M5 ;
        RECT 25.5360 0.0000 25.5600 0.0840 ;
    END
  END o_y[15]
  PIN o_y[16]
    DIRECTION OUTPUT ;
    USE SIGNAL ;
    PORT
      LAYER M3 ;
        RECT 25.4160 0.0000 25.4340 0.0380 ;
    END
  END o_y[16]
  PIN o_y[17]
    DIRECTION OUTPUT ;
    USE SIGNAL ;
    PORT
      LAYER M5 ;
        RECT 25.2480 0.0000 25.2720 0.0840 ;
    END
  END o_y[17]
  PIN o_y[18]
    DIRECTION OUTPUT ;
    USE SIGNAL ;
    PORT
      LAYER M3 ;
        RECT 24.9840 0.0000 25.0020 0.0380 ;
    END
  END o_y[18]
  PIN o_y[19]
    DIRECTION OUTPUT ;
    USE SIGNAL ;
    PORT
      LAYER M5 ;
        RECT 24.8640 0.0000 24.8880 0.0840 ;
    END
  END o_y[19]
  PIN o_y[1]
    DIRECTION OUTPUT ;
    USE SIGNAL ;
    PORT
      LAYER M5 ;
        RECT 28.2240 0.0000 28.2480 0.0840 ;
    END
  END o_y[1]
  PIN o_y[20]
    DIRECTION OUTPUT ;
    USE SIGNAL ;
    PORT
      LAYER M3 ;
        RECT 24.6240 0.0000 24.6420 0.0380 ;
    END
  END o_y[20]
  PIN o_y[21]
    DIRECTION OUTPUT ;
    USE SIGNAL ;
    PORT
      LAYER M5 ;
        RECT 24.4800 0.0000 24.5040 0.0840 ;
    END
  END o_y[21]
  PIN o_y[22]
    DIRECTION OUTPUT ;
    USE SIGNAL ;
    PORT
      LAYER M3 ;
        RECT 24.2640 0.0000 24.2820 0.0380 ;
    END
  END o_y[22]
  PIN o_y[23]
    DIRECTION OUTPUT ;
    USE SIGNAL ;
    PORT
      LAYER M5 ;
        RECT 24.0960 0.0000 24.1200 0.0840 ;
    END
  END o_y[23]
  PIN o_y[24]
    DIRECTION OUTPUT ;
    USE SIGNAL ;
    PORT
      LAYER M3 ;
        RECT 23.9040 0.0000 23.9220 0.0380 ;
    END
  END o_y[24]
  PIN o_y[25]
    DIRECTION OUTPUT ;
    USE SIGNAL ;
    PORT
      LAYER M5 ;
        RECT 23.7120 0.0000 23.7360 0.0840 ;
    END
  END o_y[25]
  PIN o_y[26]
    DIRECTION OUTPUT ;
    USE SIGNAL ;
    PORT
      LAYER M3 ;
        RECT 23.5440 0.0000 23.5620 0.0380 ;
    END
  END o_y[26]
  PIN o_y[27]
    DIRECTION OUTPUT ;
    USE SIGNAL ;
    PORT
      LAYER M5 ;
        RECT 23.3280 0.0000 23.3520 0.0840 ;
    END
  END o_y[27]
  PIN o_y[28]
    DIRECTION OUTPUT ;
    USE SIGNAL ;
    PORT
      LAYER M3 ;
        RECT 23.1120 0.0000 23.1300 0.0380 ;
    END
  END o_y[28]
  PIN o_y[29]
    DIRECTION OUTPUT ;
    USE SIGNAL ;
    PORT
      LAYER M5 ;
        RECT 22.9440 0.0000 22.9680 0.0840 ;
    END
  END o_y[29]
  PIN o_y[2]
    DIRECTION OUTPUT ;
    USE SIGNAL ;
    PORT
      LAYER M3 ;
        RECT 28.0080 0.0000 28.0260 0.0380 ;
    END
  END o_y[2]
  PIN o_y[30]
    DIRECTION OUTPUT ;
    USE SIGNAL ;
    PORT
      LAYER M3 ;
        RECT 22.7520 0.0000 22.7700 0.0380 ;
    END
  END o_y[30]
  PIN o_y[31]
    DIRECTION OUTPUT ;
    USE SIGNAL ;
    PORT
      LAYER M5 ;
        RECT 22.5600 0.0000 22.5840 0.0840 ;
    END
  END o_y[31]
  PIN o_y[32]
    DIRECTION OUTPUT ;
    USE SIGNAL ;
    PORT
      LAYER M3 ;
        RECT 22.3920 0.0000 22.4100 0.0380 ;
    END
  END o_y[32]
  PIN o_y[33]
    DIRECTION OUTPUT ;
    USE SIGNAL ;
    PORT
      LAYER M5 ;
        RECT 22.1760 0.0000 22.2000 0.0840 ;
    END
  END o_y[33]
  PIN o_y[34]
    DIRECTION OUTPUT ;
    USE SIGNAL ;
    PORT
      LAYER M3 ;
        RECT 22.0320 0.0000 22.0500 0.0380 ;
    END
  END o_y[34]
  PIN o_y[35]
    DIRECTION OUTPUT ;
    USE SIGNAL ;
    PORT
      LAYER M5 ;
        RECT 21.7920 0.0000 21.8160 0.0840 ;
    END
  END o_y[35]
  PIN o_y[36]
    DIRECTION OUTPUT ;
    USE SIGNAL ;
    PORT
      LAYER M3 ;
        RECT 21.6720 0.0000 21.6900 0.0380 ;
    END
  END o_y[36]
  PIN o_y[37]
    DIRECTION OUTPUT ;
    USE SIGNAL ;
    PORT
      LAYER M5 ;
        RECT 21.4080 0.0000 21.4320 0.0840 ;
    END
  END o_y[37]
  PIN o_y[38]
    DIRECTION OUTPUT ;
    USE SIGNAL ;
    PORT
      LAYER M3 ;
        RECT 21.2400 0.0000 21.2580 0.0380 ;
    END
  END o_y[38]
  PIN o_y[39]
    DIRECTION OUTPUT ;
    USE SIGNAL ;
    PORT
      LAYER M5 ;
        RECT 21.1200 0.0000 21.1440 0.0840 ;
    END
  END o_y[39]
  PIN o_y[3]
    DIRECTION OUTPUT ;
    USE SIGNAL ;
    PORT
      LAYER M5 ;
        RECT 27.8400 0.0000 27.8640 0.0840 ;
    END
  END o_y[3]
  PIN o_y[40]
    DIRECTION OUTPUT ;
    USE SIGNAL ;
    PORT
      LAYER M3 ;
        RECT 20.8800 0.0000 20.8980 0.0380 ;
    END
  END o_y[40]
  PIN o_y[41]
    DIRECTION OUTPUT ;
    USE SIGNAL ;
    PORT
      LAYER M5 ;
        RECT 20.7360 0.0000 20.7600 0.0840 ;
    END
  END o_y[41]
  PIN o_y[42]
    DIRECTION OUTPUT ;
    USE SIGNAL ;
    PORT
      LAYER M3 ;
        RECT 20.5200 0.0000 20.5380 0.0380 ;
    END
  END o_y[42]
  PIN o_y[43]
    DIRECTION OUTPUT ;
    USE SIGNAL ;
    PORT
      LAYER M5 ;
        RECT 20.3520 0.0000 20.3760 0.0840 ;
    END
  END o_y[43]
  PIN o_y[44]
    DIRECTION OUTPUT ;
    USE SIGNAL ;
    PORT
      LAYER M3 ;
        RECT 20.1600 0.0000 20.1780 0.0380 ;
    END
  END o_y[44]
  PIN o_y[45]
    DIRECTION OUTPUT ;
    USE SIGNAL ;
    PORT
      LAYER M5 ;
        RECT 19.9680 0.0000 19.9920 0.0840 ;
    END
  END o_y[45]
  PIN o_y[46]
    DIRECTION OUTPUT ;
    USE SIGNAL ;
    PORT
      LAYER M3 ;
        RECT 19.8000 0.0000 19.8180 0.0380 ;
    END
  END o_y[46]
  PIN o_y[47]
    DIRECTION OUTPUT ;
    USE SIGNAL ;
    PORT
      LAYER M5 ;
        RECT 19.5840 0.0000 19.6080 0.0840 ;
    END
  END o_y[47]
  PIN o_y[48]
    DIRECTION OUTPUT ;
    USE SIGNAL ;
    PORT
      LAYER M3 ;
        RECT 19.3680 0.0000 19.3860 0.0380 ;
    END
  END o_y[48]
  PIN o_y[49]
    DIRECTION OUTPUT ;
    USE SIGNAL ;
    PORT
      LAYER M5 ;
        RECT 19.2000 0.0000 19.2240 0.0840 ;
    END
  END o_y[49]
  PIN o_y[4]
    DIRECTION OUTPUT ;
    USE SIGNAL ;
    PORT
      LAYER M3 ;
        RECT 27.6480 0.0000 27.6660 0.0380 ;
    END
  END o_y[4]
  PIN o_y[50]
    DIRECTION OUTPUT ;
    USE SIGNAL ;
    PORT
      LAYER M3 ;
        RECT 19.0080 0.0000 19.0260 0.0380 ;
    END
  END o_y[50]
  PIN o_y[51]
    DIRECTION OUTPUT ;
    USE SIGNAL ;
    PORT
      LAYER M5 ;
        RECT 18.8160 0.0000 18.8400 0.0840 ;
    END
  END o_y[51]
  PIN o_y[52]
    DIRECTION OUTPUT ;
    USE SIGNAL ;
    PORT
      LAYER M3 ;
        RECT 18.6480 0.0000 18.6660 0.0380 ;
    END
  END o_y[52]
  PIN o_y[53]
    DIRECTION OUTPUT ;
    USE SIGNAL ;
    PORT
      LAYER M5 ;
        RECT 18.4320 0.0000 18.4560 0.0840 ;
    END
  END o_y[53]
  PIN o_y[54]
    DIRECTION OUTPUT ;
    USE SIGNAL ;
    PORT
      LAYER M3 ;
        RECT 18.2880 0.0000 18.3060 0.0380 ;
    END
  END o_y[54]
  PIN o_y[55]
    DIRECTION OUTPUT ;
    USE SIGNAL ;
    PORT
      LAYER M5 ;
        RECT 18.0480 0.0000 18.0720 0.0840 ;
    END
  END o_y[55]
  PIN o_y[56]
    DIRECTION OUTPUT ;
    USE SIGNAL ;
    PORT
      LAYER M3 ;
        RECT 17.9280 0.0000 17.9460 0.0380 ;
    END
  END o_y[56]
  PIN o_y[57]
    DIRECTION OUTPUT ;
    USE SIGNAL ;
    PORT
      LAYER M5 ;
        RECT 17.6640 0.0000 17.6880 0.0840 ;
    END
  END o_y[57]
  PIN o_y[58]
    DIRECTION OUTPUT ;
    USE SIGNAL ;
    PORT
      LAYER M3 ;
        RECT 17.4960 0.0000 17.5140 0.0380 ;
    END
  END o_y[58]
  PIN o_y[59]
    DIRECTION OUTPUT ;
    USE SIGNAL ;
    PORT
      LAYER M5 ;
        RECT 17.3760 0.0000 17.4000 0.0840 ;
    END
  END o_y[59]
  PIN o_y[5]
    DIRECTION OUTPUT ;
    USE SIGNAL ;
    PORT
      LAYER M5 ;
        RECT 27.4560 0.0000 27.4800 0.0840 ;
    END
  END o_y[5]
  PIN o_y[60]
    DIRECTION OUTPUT ;
    USE SIGNAL ;
    PORT
      LAYER M3 ;
        RECT 17.1360 0.0000 17.1540 0.0380 ;
    END
  END o_y[60]
  PIN o_y[61]
    DIRECTION OUTPUT ;
    USE SIGNAL ;
    PORT
      LAYER M5 ;
        RECT 16.9920 0.0000 17.0160 0.0840 ;
    END
  END o_y[61]
  PIN o_y[62]
    DIRECTION OUTPUT ;
    USE SIGNAL ;
    PORT
      LAYER M3 ;
        RECT 16.7760 0.0000 16.7940 0.0380 ;
    END
  END o_y[62]
  PIN o_y[63]
    DIRECTION OUTPUT ;
    USE SIGNAL ;
    PORT
      LAYER M5 ;
        RECT 16.6080 0.0000 16.6320 0.0840 ;
    END
  END o_y[63]
  PIN o_y[64]
    DIRECTION OUTPUT ;
    USE SIGNAL ;
    PORT
      LAYER M3 ;
        RECT 16.4160 0.0000 16.4340 0.0380 ;
    END
  END o_y[64]
  PIN o_y[65]
    DIRECTION OUTPUT ;
    USE SIGNAL ;
    PORT
      LAYER M5 ;
        RECT 16.2240 0.0000 16.2480 0.0840 ;
    END
  END o_y[65]
  PIN o_y[66]
    DIRECTION OUTPUT ;
    USE SIGNAL ;
    PORT
      LAYER M3 ;
        RECT 16.0560 0.0000 16.0740 0.0380 ;
    END
  END o_y[66]
  PIN o_y[67]
    DIRECTION OUTPUT ;
    USE SIGNAL ;
    PORT
      LAYER M5 ;
        RECT 15.8400 0.0000 15.8640 0.0840 ;
    END
  END o_y[67]
  PIN o_y[68]
    DIRECTION OUTPUT ;
    USE SIGNAL ;
    PORT
      LAYER M3 ;
        RECT 15.6240 0.0000 15.6420 0.0380 ;
    END
  END o_y[68]
  PIN o_y[69]
    DIRECTION OUTPUT ;
    USE SIGNAL ;
    PORT
      LAYER M5 ;
        RECT 15.4560 0.0000 15.4800 0.0840 ;
    END
  END o_y[69]
  PIN o_y[6]
    DIRECTION OUTPUT ;
    USE SIGNAL ;
    PORT
      LAYER M3 ;
        RECT 27.2880 0.0000 27.3060 0.0380 ;
    END
  END o_y[6]
  PIN o_y[70]
    DIRECTION OUTPUT ;
    USE SIGNAL ;
    PORT
      LAYER M3 ;
        RECT 15.2640 0.0000 15.2820 0.0380 ;
    END
  END o_y[70]
  PIN o_y[71]
    DIRECTION OUTPUT ;
    USE SIGNAL ;
    PORT
      LAYER M5 ;
        RECT 15.0720 0.0000 15.0960 0.0840 ;
    END
  END o_y[71]
  PIN o_y[72]
    DIRECTION OUTPUT ;
    USE SIGNAL ;
    PORT
      LAYER M3 ;
        RECT 14.9040 0.0000 14.9220 0.0380 ;
    END
  END o_y[72]
  PIN o_y[73]
    DIRECTION OUTPUT ;
    USE SIGNAL ;
    PORT
      LAYER M5 ;
        RECT 14.6880 0.0000 14.7120 0.0840 ;
    END
  END o_y[73]
  PIN o_y[74]
    DIRECTION OUTPUT ;
    USE SIGNAL ;
    PORT
      LAYER M3 ;
        RECT 14.5440 0.0000 14.5620 0.0380 ;
    END
  END o_y[74]
  PIN o_y[75]
    DIRECTION OUTPUT ;
    USE SIGNAL ;
    PORT
      LAYER M5 ;
        RECT 14.3040 0.0000 14.3280 0.0840 ;
    END
  END o_y[75]
  PIN o_y[76]
    DIRECTION OUTPUT ;
    USE SIGNAL ;
    PORT
      LAYER M3 ;
        RECT 14.1840 0.0000 14.2020 0.0380 ;
    END
  END o_y[76]
  PIN o_y[77]
    DIRECTION OUTPUT ;
    USE SIGNAL ;
    PORT
      LAYER M5 ;
        RECT 13.9200 0.0000 13.9440 0.0840 ;
    END
  END o_y[77]
  PIN o_y[78]
    DIRECTION OUTPUT ;
    USE SIGNAL ;
    PORT
      LAYER M3 ;
        RECT 13.7520 0.0000 13.7700 0.0380 ;
    END
  END o_y[78]
  PIN o_y[79]
    DIRECTION OUTPUT ;
    USE SIGNAL ;
    PORT
      LAYER M5 ;
        RECT 13.6320 0.0000 13.6560 0.0840 ;
    END
  END o_y[79]
  PIN o_y[7]
    DIRECTION OUTPUT ;
    USE SIGNAL ;
    PORT
      LAYER M5 ;
        RECT 27.0720 0.0000 27.0960 0.0840 ;
    END
  END o_y[7]
  PIN o_y[80]
    DIRECTION OUTPUT ;
    USE SIGNAL ;
    PORT
      LAYER M3 ;
        RECT 13.3920 0.0000 13.4100 0.0380 ;
    END
  END o_y[80]
  PIN o_y[81]
    DIRECTION OUTPUT ;
    USE SIGNAL ;
    PORT
      LAYER M5 ;
        RECT 13.2480 0.0000 13.2720 0.0840 ;
    END
  END o_y[81]
  PIN o_y[82]
    DIRECTION OUTPUT ;
    USE SIGNAL ;
    PORT
      LAYER M3 ;
        RECT 13.0320 0.0000 13.0500 0.0380 ;
    END
  END o_y[82]
  PIN o_y[83]
    DIRECTION OUTPUT ;
    USE SIGNAL ;
    PORT
      LAYER M5 ;
        RECT 12.8640 0.0000 12.8880 0.0840 ;
    END
  END o_y[83]
  PIN o_y[84]
    DIRECTION OUTPUT ;
    USE SIGNAL ;
    PORT
      LAYER M3 ;
        RECT 12.6720 0.0000 12.6900 0.0380 ;
    END
  END o_y[84]
  PIN o_y[85]
    DIRECTION OUTPUT ;
    USE SIGNAL ;
    PORT
      LAYER M5 ;
        RECT 12.4800 0.0000 12.5040 0.0840 ;
    END
  END o_y[85]
  PIN o_y[86]
    DIRECTION OUTPUT ;
    USE SIGNAL ;
    PORT
      LAYER M3 ;
        RECT 12.2400 0.0000 12.2580 0.0380 ;
    END
  END o_y[86]
  PIN o_y[87]
    DIRECTION OUTPUT ;
    USE SIGNAL ;
    PORT
      LAYER M5 ;
        RECT 12.0960 0.0000 12.1200 0.0840 ;
    END
  END o_y[87]
  PIN o_y[88]
    DIRECTION OUTPUT ;
    USE SIGNAL ;
    PORT
      LAYER M3 ;
        RECT 11.8800 0.0000 11.8980 0.0380 ;
    END
  END o_y[88]
  PIN o_y[89]
    DIRECTION OUTPUT ;
    USE SIGNAL ;
    PORT
      LAYER M5 ;
        RECT 11.7120 0.0000 11.7360 0.0840 ;
    END
  END o_y[89]
  PIN o_y[8]
    DIRECTION OUTPUT ;
    USE SIGNAL ;
    PORT
      LAYER M3 ;
        RECT 26.9280 0.0000 26.9460 0.0380 ;
    END
  END o_y[8]
  PIN o_y[90]
    DIRECTION OUTPUT ;
    USE SIGNAL ;
    PORT
      LAYER M3 ;
        RECT 11.5200 0.0000 11.5380 0.0380 ;
    END
  END o_y[90]
  PIN o_y[91]
    DIRECTION OUTPUT ;
    USE SIGNAL ;
    PORT
      LAYER M5 ;
        RECT 11.3280 0.0000 11.3520 0.0840 ;
    END
  END o_y[91]
  PIN o_y[92]
    DIRECTION OUTPUT ;
    USE SIGNAL ;
    PORT
      LAYER M3 ;
        RECT 11.1600 0.0000 11.1780 0.0380 ;
    END
  END o_y[92]
  PIN o_y[93]
    DIRECTION OUTPUT ;
    USE SIGNAL ;
    PORT
      LAYER M5 ;
        RECT 10.9440 0.0000 10.9680 0.0840 ;
    END
  END o_y[93]
  PIN o_y[94]
    DIRECTION OUTPUT ;
    USE SIGNAL ;
    PORT
      LAYER M3 ;
        RECT 10.8000 0.0000 10.8180 0.0380 ;
    END
  END o_y[94]
  PIN o_y[95]
    DIRECTION OUTPUT ;
    USE SIGNAL ;
    PORT
      LAYER M5 ;
        RECT 10.5600 0.0000 10.5840 0.0840 ;
    END
  END o_y[95]
  PIN o_y[96]
    DIRECTION OUTPUT ;
    USE SIGNAL ;
    PORT
      LAYER M3 ;
        RECT 10.3680 0.0000 10.3860 0.0380 ;
    END
  END o_y[96]
  PIN o_y[97]
    DIRECTION OUTPUT ;
    USE SIGNAL ;
    PORT
      LAYER M5 ;
        RECT 10.1760 0.0000 10.2000 0.0840 ;
    END
  END o_y[97]
  PIN o_y[98]
    DIRECTION OUTPUT ;
    USE SIGNAL ;
    PORT
      LAYER M3 ;
        RECT 10.0080 0.0000 10.0260 0.0380 ;
    END
  END o_y[98]
  PIN o_y[99]
    DIRECTION OUTPUT ;
    USE SIGNAL ;
    PORT
      LAYER M5 ;
        RECT 9.7920 0.0000 9.8160 0.0840 ;
    END
  END o_y[99]
  PIN o_y[9]
    DIRECTION OUTPUT ;
    USE SIGNAL ;
    PORT
      LAYER M5 ;
        RECT 26.6880 0.0000 26.7120 0.0840 ;
    END
  END o_y[9]
  PIN r_c[0]
    DIRECTION INPUT ;
    USE SIGNAL ;
    PORT
      LAYER M3 ;
        RECT 168.1920 0.0000 168.2100 0.0380 ;
    END
  END r_c[0]
  PIN r_c[1]
    DIRECTION INPUT ;
    USE SIGNAL ;
    PORT
      LAYER M5 ;
        RECT 168.0000 0.0000 168.0240 0.0840 ;
    END
  END r_c[1]
  PIN r_h[0]
    DIRECTION INPUT ;
    USE SIGNAL ;
    PORT
      LAYER M3 ;
        RECT 167.8320 0.0000 167.8500 0.0380 ;
    END
  END r_h[0]
  PIN r_h[10]
    DIRECTION INPUT ;
    USE SIGNAL ;
    PORT
      LAYER M3 ;
        RECT 165.9600 0.0000 165.9780 0.0380 ;
    END
  END r_h[10]
  PIN r_h[11]
    DIRECTION INPUT ;
    USE SIGNAL ;
    PORT
      LAYER M5 ;
        RECT 165.7920 0.0000 165.8160 0.0840 ;
    END
  END r_h[11]
  PIN r_h[12]
    DIRECTION INPUT ;
    USE SIGNAL ;
    PORT
      LAYER M3 ;
        RECT 165.6000 0.0000 165.6180 0.0380 ;
    END
  END r_h[12]
  PIN r_h[13]
    DIRECTION INPUT ;
    USE SIGNAL ;
    PORT
      LAYER M5 ;
        RECT 165.4080 0.0000 165.4320 0.0840 ;
    END
  END r_h[13]
  PIN r_h[14]
    DIRECTION INPUT ;
    USE SIGNAL ;
    PORT
      LAYER M3 ;
        RECT 165.1680 0.0000 165.1860 0.0380 ;
    END
  END r_h[14]
  PIN r_h[15]
    DIRECTION INPUT ;
    USE SIGNAL ;
    PORT
      LAYER M5 ;
        RECT 165.0240 0.0000 165.0480 0.0840 ;
    END
  END r_h[15]
  PIN r_h[16]
    DIRECTION INPUT ;
    USE SIGNAL ;
    PORT
      LAYER M3 ;
        RECT 164.8080 0.0000 164.8260 0.0380 ;
    END
  END r_h[16]
  PIN r_h[17]
    DIRECTION INPUT ;
    USE SIGNAL ;
    PORT
      LAYER M5 ;
        RECT 164.6400 0.0000 164.6640 0.0840 ;
    END
  END r_h[17]
  PIN r_h[18]
    DIRECTION INPUT ;
    USE SIGNAL ;
    PORT
      LAYER M3 ;
        RECT 164.4480 0.0000 164.4660 0.0380 ;
    END
  END r_h[18]
  PIN r_h[19]
    DIRECTION INPUT ;
    USE SIGNAL ;
    PORT
      LAYER M5 ;
        RECT 164.2560 0.0000 164.2800 0.0840 ;
    END
  END r_h[19]
  PIN r_h[1]
    DIRECTION INPUT ;
    USE SIGNAL ;
    PORT
      LAYER M5 ;
        RECT 167.6160 0.0000 167.6400 0.0840 ;
    END
  END r_h[1]
  PIN r_h[20]
    DIRECTION INPUT ;
    USE SIGNAL ;
    PORT
      LAYER M3 ;
        RECT 164.0880 0.0000 164.1060 0.0380 ;
    END
  END r_h[20]
  PIN r_h[21]
    DIRECTION INPUT ;
    USE SIGNAL ;
    PORT
      LAYER M5 ;
        RECT 163.8720 0.0000 163.8960 0.0840 ;
    END
  END r_h[21]
  PIN r_h[22]
    DIRECTION INPUT ;
    USE SIGNAL ;
    PORT
      LAYER M3 ;
        RECT 163.7280 0.0000 163.7460 0.0380 ;
    END
  END r_h[22]
  PIN r_h[23]
    DIRECTION INPUT ;
    USE SIGNAL ;
    PORT
      LAYER M5 ;
        RECT 163.4880 0.0000 163.5120 0.0840 ;
    END
  END r_h[23]
  PIN r_h[24]
    DIRECTION INPUT ;
    USE SIGNAL ;
    PORT
      LAYER M3 ;
        RECT 163.2960 0.0000 163.3140 0.0380 ;
    END
  END r_h[24]
  PIN r_h[25]
    DIRECTION INPUT ;
    USE SIGNAL ;
    PORT
      LAYER M5 ;
        RECT 163.1040 0.0000 163.1280 0.0840 ;
    END
  END r_h[25]
  PIN r_h[26]
    DIRECTION INPUT ;
    USE SIGNAL ;
    PORT
      LAYER M3 ;
        RECT 162.9360 0.0000 162.9540 0.0380 ;
    END
  END r_h[26]
  PIN r_h[27]
    DIRECTION INPUT ;
    USE SIGNAL ;
    PORT
      LAYER M5 ;
        RECT 162.7200 0.0000 162.7440 0.0840 ;
    END
  END r_h[27]
  PIN r_h[28]
    DIRECTION INPUT ;
    USE SIGNAL ;
    PORT
      LAYER M3 ;
        RECT 162.5760 0.0000 162.5940 0.0380 ;
    END
  END r_h[28]
  PIN r_h[29]
    DIRECTION INPUT ;
    USE SIGNAL ;
    PORT
      LAYER M5 ;
        RECT 162.3360 0.0000 162.3600 0.0840 ;
    END
  END r_h[29]
  PIN r_h[2]
    DIRECTION INPUT ;
    USE SIGNAL ;
    PORT
      LAYER M3 ;
        RECT 167.4720 0.0000 167.4900 0.0380 ;
    END
  END r_h[2]
  PIN r_h[30]
    DIRECTION INPUT ;
    USE SIGNAL ;
    PORT
      LAYER M3 ;
        RECT 162.2160 0.0000 162.2340 0.0380 ;
    END
  END r_h[30]
  PIN r_h[31]
    DIRECTION INPUT ;
    USE SIGNAL ;
    PORT
      LAYER M5 ;
        RECT 162.0480 0.0000 162.0720 0.0840 ;
    END
  END r_h[31]
  PIN r_h[32]
    DIRECTION INPUT ;
    USE SIGNAL ;
    PORT
      LAYER M3 ;
        RECT 161.7840 0.0000 161.8020 0.0380 ;
    END
  END r_h[32]
  PIN r_h[33]
    DIRECTION INPUT ;
    USE SIGNAL ;
    PORT
      LAYER M5 ;
        RECT 161.6640 0.0000 161.6880 0.0840 ;
    END
  END r_h[33]
  PIN r_h[34]
    DIRECTION INPUT ;
    USE SIGNAL ;
    PORT
      LAYER M3 ;
        RECT 161.4240 0.0000 161.4420 0.0380 ;
    END
  END r_h[34]
  PIN r_h[35]
    DIRECTION INPUT ;
    USE SIGNAL ;
    PORT
      LAYER M5 ;
        RECT 161.2800 0.0000 161.3040 0.0840 ;
    END
  END r_h[35]
  PIN r_h[36]
    DIRECTION INPUT ;
    USE SIGNAL ;
    PORT
      LAYER M3 ;
        RECT 161.0640 0.0000 161.0820 0.0380 ;
    END
  END r_h[36]
  PIN r_h[37]
    DIRECTION INPUT ;
    USE SIGNAL ;
    PORT
      LAYER M5 ;
        RECT 160.8960 0.0000 160.9200 0.0840 ;
    END
  END r_h[37]
  PIN r_h[38]
    DIRECTION INPUT ;
    USE SIGNAL ;
    PORT
      LAYER M3 ;
        RECT 160.7040 0.0000 160.7220 0.0380 ;
    END
  END r_h[38]
  PIN r_h[39]
    DIRECTION INPUT ;
    USE SIGNAL ;
    PORT
      LAYER M5 ;
        RECT 160.5120 0.0000 160.5360 0.0840 ;
    END
  END r_h[39]
  PIN r_h[3]
    DIRECTION INPUT ;
    USE SIGNAL ;
    PORT
      LAYER M5 ;
        RECT 167.2320 0.0000 167.2560 0.0840 ;
    END
  END r_h[3]
  PIN r_h[40]
    DIRECTION INPUT ;
    USE SIGNAL ;
    PORT
      LAYER M3 ;
        RECT 160.3440 0.0000 160.3620 0.0380 ;
    END
  END r_h[40]
  PIN r_h[41]
    DIRECTION INPUT ;
    USE SIGNAL ;
    PORT
      LAYER M5 ;
        RECT 160.1280 0.0000 160.1520 0.0840 ;
    END
  END r_h[41]
  PIN r_h[42]
    DIRECTION INPUT ;
    USE SIGNAL ;
    PORT
      LAYER M3 ;
        RECT 159.9120 0.0000 159.9300 0.0380 ;
    END
  END r_h[42]
  PIN r_h[43]
    DIRECTION INPUT ;
    USE SIGNAL ;
    PORT
      LAYER M5 ;
        RECT 159.7440 0.0000 159.7680 0.0840 ;
    END
  END r_h[43]
  PIN r_h[44]
    DIRECTION INPUT ;
    USE SIGNAL ;
    PORT
      LAYER M3 ;
        RECT 159.5520 0.0000 159.5700 0.0380 ;
    END
  END r_h[44]
  PIN r_h[45]
    DIRECTION INPUT ;
    USE SIGNAL ;
    PORT
      LAYER M5 ;
        RECT 159.3600 0.0000 159.3840 0.0840 ;
    END
  END r_h[45]
  PIN r_h[46]
    DIRECTION INPUT ;
    USE SIGNAL ;
    PORT
      LAYER M3 ;
        RECT 159.1920 0.0000 159.2100 0.0380 ;
    END
  END r_h[46]
  PIN r_h[47]
    DIRECTION INPUT ;
    USE SIGNAL ;
    PORT
      LAYER M5 ;
        RECT 158.9760 0.0000 159.0000 0.0840 ;
    END
  END r_h[47]
  PIN r_h[48]
    DIRECTION INPUT ;
    USE SIGNAL ;
    PORT
      LAYER M3 ;
        RECT 158.8320 0.0000 158.8500 0.0380 ;
    END
  END r_h[48]
  PIN r_h[49]
    DIRECTION INPUT ;
    USE SIGNAL ;
    PORT
      LAYER M5 ;
        RECT 158.5920 0.0000 158.6160 0.0840 ;
    END
  END r_h[49]
  PIN r_h[4]
    DIRECTION INPUT ;
    USE SIGNAL ;
    PORT
      LAYER M3 ;
        RECT 167.0400 0.0000 167.0580 0.0380 ;
    END
  END r_h[4]
  PIN r_h[50]
    DIRECTION INPUT ;
    USE SIGNAL ;
    PORT
      LAYER M3 ;
        RECT 158.4720 0.0000 158.4900 0.0380 ;
    END
  END r_h[50]
  PIN r_h[51]
    DIRECTION INPUT ;
    USE SIGNAL ;
    PORT
      LAYER M5 ;
        RECT 158.2080 0.0000 158.2320 0.0840 ;
    END
  END r_h[51]
  PIN r_h[52]
    DIRECTION INPUT ;
    USE SIGNAL ;
    PORT
      LAYER M3 ;
        RECT 158.0400 0.0000 158.0580 0.0380 ;
    END
  END r_h[52]
  PIN r_h[53]
    DIRECTION INPUT ;
    USE SIGNAL ;
    PORT
      LAYER M5 ;
        RECT 157.9200 0.0000 157.9440 0.0840 ;
    END
  END r_h[53]
  PIN r_h[54]
    DIRECTION INPUT ;
    USE SIGNAL ;
    PORT
      LAYER M3 ;
        RECT 157.6800 0.0000 157.6980 0.0380 ;
    END
  END r_h[54]
  PIN r_h[55]
    DIRECTION INPUT ;
    USE SIGNAL ;
    PORT
      LAYER M5 ;
        RECT 157.5360 0.0000 157.5600 0.0840 ;
    END
  END r_h[55]
  PIN r_h[56]
    DIRECTION INPUT ;
    USE SIGNAL ;
    PORT
      LAYER M3 ;
        RECT 157.3200 0.0000 157.3380 0.0380 ;
    END
  END r_h[56]
  PIN r_h[57]
    DIRECTION INPUT ;
    USE SIGNAL ;
    PORT
      LAYER M5 ;
        RECT 157.1520 0.0000 157.1760 0.0840 ;
    END
  END r_h[57]
  PIN r_h[58]
    DIRECTION INPUT ;
    USE SIGNAL ;
    PORT
      LAYER M3 ;
        RECT 156.9600 0.0000 156.9780 0.0380 ;
    END
  END r_h[58]
  PIN r_h[59]
    DIRECTION INPUT ;
    USE SIGNAL ;
    PORT
      LAYER M5 ;
        RECT 156.7680 0.0000 156.7920 0.0840 ;
    END
  END r_h[59]
  PIN r_h[5]
    DIRECTION INPUT ;
    USE SIGNAL ;
    PORT
      LAYER M5 ;
        RECT 166.8480 0.0000 166.8720 0.0840 ;
    END
  END r_h[5]
  PIN r_h[60]
    DIRECTION INPUT ;
    USE SIGNAL ;
    PORT
      LAYER M3 ;
        RECT 156.6000 0.0000 156.6180 0.0380 ;
    END
  END r_h[60]
  PIN r_h[61]
    DIRECTION INPUT ;
    USE SIGNAL ;
    PORT
      LAYER M5 ;
        RECT 156.3840 0.0000 156.4080 0.0840 ;
    END
  END r_h[61]
  PIN r_h[62]
    DIRECTION INPUT ;
    USE SIGNAL ;
    PORT
      LAYER M3 ;
        RECT 156.1680 0.0000 156.1860 0.0380 ;
    END
  END r_h[62]
  PIN r_h[63]
    DIRECTION INPUT ;
    USE SIGNAL ;
    PORT
      LAYER M5 ;
        RECT 156.0000 0.0000 156.0240 0.0840 ;
    END
  END r_h[63]
  PIN r_h[6]
    DIRECTION INPUT ;
    USE SIGNAL ;
    PORT
      LAYER M3 ;
        RECT 166.6800 0.0000 166.6980 0.0380 ;
    END
  END r_h[6]
  PIN r_h[7]
    DIRECTION INPUT ;
    USE SIGNAL ;
    PORT
      LAYER M5 ;
        RECT 166.4640 0.0000 166.4880 0.0840 ;
    END
  END r_h[7]
  PIN r_h[8]
    DIRECTION INPUT ;
    USE SIGNAL ;
    PORT
      LAYER M3 ;
        RECT 166.3200 0.0000 166.3380 0.0380 ;
    END
  END r_h[8]
  PIN r_h[9]
    DIRECTION INPUT ;
    USE SIGNAL ;
    PORT
      LAYER M5 ;
        RECT 166.0800 0.0000 166.1040 0.0840 ;
    END
  END r_h[9]
  PIN r_k[0]
    DIRECTION INPUT ;
    USE SIGNAL ;
    PORT
      LAYER M3 ;
        RECT 155.8080 0.0000 155.8260 0.0380 ;
    END
  END r_k[0]
  PIN r_k[100]
    DIRECTION INPUT ;
    USE SIGNAL ;
    PORT
      LAYER M3 ;
        RECT 137.0880 0.0000 137.1060 0.0380 ;
    END
  END r_k[100]
  PIN r_k[101]
    DIRECTION INPUT ;
    USE SIGNAL ;
    PORT
      LAYER M5 ;
        RECT 136.8960 0.0000 136.9200 0.0840 ;
    END
  END r_k[101]
  PIN r_k[102]
    DIRECTION INPUT ;
    USE SIGNAL ;
    PORT
      LAYER M3 ;
        RECT 136.7280 0.0000 136.7460 0.0380 ;
    END
  END r_k[102]
  PIN r_k[103]
    DIRECTION INPUT ;
    USE SIGNAL ;
    PORT
      LAYER M5 ;
        RECT 136.5120 0.0000 136.5360 0.0840 ;
    END
  END r_k[103]
  PIN r_k[104]
    DIRECTION INPUT ;
    USE SIGNAL ;
    PORT
      LAYER M3 ;
        RECT 136.3680 0.0000 136.3860 0.0380 ;
    END
  END r_k[104]
  PIN r_k[105]
    DIRECTION INPUT ;
    USE SIGNAL ;
    PORT
      LAYER M5 ;
        RECT 136.1280 0.0000 136.1520 0.0840 ;
    END
  END r_k[105]
  PIN r_k[106]
    DIRECTION INPUT ;
    USE SIGNAL ;
    PORT
      LAYER M3 ;
        RECT 135.9360 0.0000 135.9540 0.0380 ;
    END
  END r_k[106]
  PIN r_k[107]
    DIRECTION INPUT ;
    USE SIGNAL ;
    PORT
      LAYER M5 ;
        RECT 135.7440 0.0000 135.7680 0.0840 ;
    END
  END r_k[107]
  PIN r_k[108]
    DIRECTION INPUT ;
    USE SIGNAL ;
    PORT
      LAYER M3 ;
        RECT 135.5760 0.0000 135.5940 0.0380 ;
    END
  END r_k[108]
  PIN r_k[109]
    DIRECTION INPUT ;
    USE SIGNAL ;
    PORT
      LAYER M5 ;
        RECT 135.3600 0.0000 135.3840 0.0840 ;
    END
  END r_k[109]
  PIN r_k[10]
    DIRECTION INPUT ;
    USE SIGNAL ;
    PORT
      LAYER M3 ;
        RECT 153.9360 0.0000 153.9540 0.0380 ;
    END
  END r_k[10]
  PIN r_k[110]
    DIRECTION INPUT ;
    USE SIGNAL ;
    PORT
      LAYER M3 ;
        RECT 135.2160 0.0000 135.2340 0.0380 ;
    END
  END r_k[110]
  PIN r_k[111]
    DIRECTION INPUT ;
    USE SIGNAL ;
    PORT
      LAYER M5 ;
        RECT 134.9760 0.0000 135.0000 0.0840 ;
    END
  END r_k[111]
  PIN r_k[112]
    DIRECTION INPUT ;
    USE SIGNAL ;
    PORT
      LAYER M3 ;
        RECT 134.8560 0.0000 134.8740 0.0380 ;
    END
  END r_k[112]
  PIN r_k[113]
    DIRECTION INPUT ;
    USE SIGNAL ;
    PORT
      LAYER M5 ;
        RECT 134.6880 0.0000 134.7120 0.0840 ;
    END
  END r_k[113]
  PIN r_k[114]
    DIRECTION INPUT ;
    USE SIGNAL ;
    PORT
      LAYER M3 ;
        RECT 134.4240 0.0000 134.4420 0.0380 ;
    END
  END r_k[114]
  PIN r_k[115]
    DIRECTION INPUT ;
    USE SIGNAL ;
    PORT
      LAYER M5 ;
        RECT 134.3040 0.0000 134.3280 0.0840 ;
    END
  END r_k[115]
  PIN r_k[116]
    DIRECTION INPUT ;
    USE SIGNAL ;
    PORT
      LAYER M3 ;
        RECT 134.0640 0.0000 134.0820 0.0380 ;
    END
  END r_k[116]
  PIN r_k[117]
    DIRECTION INPUT ;
    USE SIGNAL ;
    PORT
      LAYER M5 ;
        RECT 133.9200 0.0000 133.9440 0.0840 ;
    END
  END r_k[117]
  PIN r_k[118]
    DIRECTION INPUT ;
    USE SIGNAL ;
    PORT
      LAYER M3 ;
        RECT 133.7040 0.0000 133.7220 0.0380 ;
    END
  END r_k[118]
  PIN r_k[119]
    DIRECTION INPUT ;
    USE SIGNAL ;
    PORT
      LAYER M5 ;
        RECT 133.5360 0.0000 133.5600 0.0840 ;
    END
  END r_k[119]
  PIN r_k[11]
    DIRECTION INPUT ;
    USE SIGNAL ;
    PORT
      LAYER M5 ;
        RECT 153.7920 0.0000 153.8160 0.0840 ;
    END
  END r_k[11]
  PIN r_k[120]
    DIRECTION INPUT ;
    USE SIGNAL ;
    PORT
      LAYER M3 ;
        RECT 133.3440 0.0000 133.3620 0.0380 ;
    END
  END r_k[120]
  PIN r_k[121]
    DIRECTION INPUT ;
    USE SIGNAL ;
    PORT
      LAYER M5 ;
        RECT 133.1520 0.0000 133.1760 0.0840 ;
    END
  END r_k[121]
  PIN r_k[122]
    DIRECTION INPUT ;
    USE SIGNAL ;
    PORT
      LAYER M3 ;
        RECT 132.9840 0.0000 133.0020 0.0380 ;
    END
  END r_k[122]
  PIN r_k[123]
    DIRECTION INPUT ;
    USE SIGNAL ;
    PORT
      LAYER M5 ;
        RECT 132.7680 0.0000 132.7920 0.0840 ;
    END
  END r_k[123]
  PIN r_k[124]
    DIRECTION INPUT ;
    USE SIGNAL ;
    PORT
      LAYER M3 ;
        RECT 132.5520 0.0000 132.5700 0.0380 ;
    END
  END r_k[124]
  PIN r_k[125]
    DIRECTION INPUT ;
    USE SIGNAL ;
    PORT
      LAYER M5 ;
        RECT 132.3840 0.0000 132.4080 0.0840 ;
    END
  END r_k[125]
  PIN r_k[126]
    DIRECTION INPUT ;
    USE SIGNAL ;
    PORT
      LAYER M3 ;
        RECT 132.1920 0.0000 132.2100 0.0380 ;
    END
  END r_k[126]
  PIN r_k[127]
    DIRECTION INPUT ;
    USE SIGNAL ;
    PORT
      LAYER M5 ;
        RECT 132.0000 0.0000 132.0240 0.0840 ;
    END
  END r_k[127]
  PIN r_k[12]
    DIRECTION INPUT ;
    USE SIGNAL ;
    PORT
      LAYER M3 ;
        RECT 153.5760 0.0000 153.5940 0.0380 ;
    END
  END r_k[12]
  PIN r_k[13]
    DIRECTION INPUT ;
    USE SIGNAL ;
    PORT
      LAYER M5 ;
        RECT 153.4080 0.0000 153.4320 0.0840 ;
    END
  END r_k[13]
  PIN r_k[14]
    DIRECTION INPUT ;
    USE SIGNAL ;
    PORT
      LAYER M3 ;
        RECT 153.2160 0.0000 153.2340 0.0380 ;
    END
  END r_k[14]
  PIN r_k[15]
    DIRECTION INPUT ;
    USE SIGNAL ;
    PORT
      LAYER M5 ;
        RECT 153.0240 0.0000 153.0480 0.0840 ;
    END
  END r_k[15]
  PIN r_k[16]
    DIRECTION INPUT ;
    USE SIGNAL ;
    PORT
      LAYER M3 ;
        RECT 152.8560 0.0000 152.8740 0.0380 ;
    END
  END r_k[16]
  PIN r_k[17]
    DIRECTION INPUT ;
    USE SIGNAL ;
    PORT
      LAYER M5 ;
        RECT 152.6400 0.0000 152.6640 0.0840 ;
    END
  END r_k[17]
  PIN r_k[18]
    DIRECTION INPUT ;
    USE SIGNAL ;
    PORT
      LAYER M3 ;
        RECT 152.4240 0.0000 152.4420 0.0380 ;
    END
  END r_k[18]
  PIN r_k[19]
    DIRECTION INPUT ;
    USE SIGNAL ;
    PORT
      LAYER M5 ;
        RECT 152.2560 0.0000 152.2800 0.0840 ;
    END
  END r_k[19]
  PIN r_k[1]
    DIRECTION INPUT ;
    USE SIGNAL ;
    PORT
      LAYER M5 ;
        RECT 155.6160 0.0000 155.6400 0.0840 ;
    END
  END r_k[1]
  PIN r_k[20]
    DIRECTION INPUT ;
    USE SIGNAL ;
    PORT
      LAYER M3 ;
        RECT 152.0640 0.0000 152.0820 0.0380 ;
    END
  END r_k[20]
  PIN r_k[21]
    DIRECTION INPUT ;
    USE SIGNAL ;
    PORT
      LAYER M5 ;
        RECT 151.8720 0.0000 151.8960 0.0840 ;
    END
  END r_k[21]
  PIN r_k[22]
    DIRECTION INPUT ;
    USE SIGNAL ;
    PORT
      LAYER M3 ;
        RECT 151.7040 0.0000 151.7220 0.0380 ;
    END
  END r_k[22]
  PIN r_k[23]
    DIRECTION INPUT ;
    USE SIGNAL ;
    PORT
      LAYER M5 ;
        RECT 151.4880 0.0000 151.5120 0.0840 ;
    END
  END r_k[23]
  PIN r_k[24]
    DIRECTION INPUT ;
    USE SIGNAL ;
    PORT
      LAYER M3 ;
        RECT 151.3440 0.0000 151.3620 0.0380 ;
    END
  END r_k[24]
  PIN r_k[25]
    DIRECTION INPUT ;
    USE SIGNAL ;
    PORT
      LAYER M5 ;
        RECT 151.1040 0.0000 151.1280 0.0840 ;
    END
  END r_k[25]
  PIN r_k[26]
    DIRECTION INPUT ;
    USE SIGNAL ;
    PORT
      LAYER M3 ;
        RECT 150.9840 0.0000 151.0020 0.0380 ;
    END
  END r_k[26]
  PIN r_k[27]
    DIRECTION INPUT ;
    USE SIGNAL ;
    PORT
      LAYER M5 ;
        RECT 150.7200 0.0000 150.7440 0.0840 ;
    END
  END r_k[27]
  PIN r_k[28]
    DIRECTION INPUT ;
    USE SIGNAL ;
    PORT
      LAYER M3 ;
        RECT 150.5520 0.0000 150.5700 0.0380 ;
    END
  END r_k[28]
  PIN r_k[29]
    DIRECTION INPUT ;
    USE SIGNAL ;
    PORT
      LAYER M5 ;
        RECT 150.4320 0.0000 150.4560 0.0840 ;
    END
  END r_k[29]
  PIN r_k[2]
    DIRECTION INPUT ;
    USE SIGNAL ;
    PORT
      LAYER M3 ;
        RECT 155.4480 0.0000 155.4660 0.0380 ;
    END
  END r_k[2]
  PIN r_k[30]
    DIRECTION INPUT ;
    USE SIGNAL ;
    PORT
      LAYER M3 ;
        RECT 150.1920 0.0000 150.2100 0.0380 ;
    END
  END r_k[30]
  PIN r_k[31]
    DIRECTION INPUT ;
    USE SIGNAL ;
    PORT
      LAYER M5 ;
        RECT 150.0480 0.0000 150.0720 0.0840 ;
    END
  END r_k[31]
  PIN r_k[32]
    DIRECTION INPUT ;
    USE SIGNAL ;
    PORT
      LAYER M3 ;
        RECT 149.8320 0.0000 149.8500 0.0380 ;
    END
  END r_k[32]
  PIN r_k[33]
    DIRECTION INPUT ;
    USE SIGNAL ;
    PORT
      LAYER M5 ;
        RECT 149.6640 0.0000 149.6880 0.0840 ;
    END
  END r_k[33]
  PIN r_k[34]
    DIRECTION INPUT ;
    USE SIGNAL ;
    PORT
      LAYER M3 ;
        RECT 149.4720 0.0000 149.4900 0.0380 ;
    END
  END r_k[34]
  PIN r_k[35]
    DIRECTION INPUT ;
    USE SIGNAL ;
    PORT
      LAYER M5 ;
        RECT 149.2800 0.0000 149.3040 0.0840 ;
    END
  END r_k[35]
  PIN r_k[36]
    DIRECTION INPUT ;
    USE SIGNAL ;
    PORT
      LAYER M3 ;
        RECT 149.0400 0.0000 149.0580 0.0380 ;
    END
  END r_k[36]
  PIN r_k[37]
    DIRECTION INPUT ;
    USE SIGNAL ;
    PORT
      LAYER M5 ;
        RECT 148.8960 0.0000 148.9200 0.0840 ;
    END
  END r_k[37]
  PIN r_k[38]
    DIRECTION INPUT ;
    USE SIGNAL ;
    PORT
      LAYER M3 ;
        RECT 148.6800 0.0000 148.6980 0.0380 ;
    END
  END r_k[38]
  PIN r_k[39]
    DIRECTION INPUT ;
    USE SIGNAL ;
    PORT
      LAYER M5 ;
        RECT 148.5120 0.0000 148.5360 0.0840 ;
    END
  END r_k[39]
  PIN r_k[3]
    DIRECTION INPUT ;
    USE SIGNAL ;
    PORT
      LAYER M5 ;
        RECT 155.2320 0.0000 155.2560 0.0840 ;
    END
  END r_k[3]
  PIN r_k[40]
    DIRECTION INPUT ;
    USE SIGNAL ;
    PORT
      LAYER M3 ;
        RECT 148.3200 0.0000 148.3380 0.0380 ;
    END
  END r_k[40]
  PIN r_k[41]
    DIRECTION INPUT ;
    USE SIGNAL ;
    PORT
      LAYER M5 ;
        RECT 148.1280 0.0000 148.1520 0.0840 ;
    END
  END r_k[41]
  PIN r_k[42]
    DIRECTION INPUT ;
    USE SIGNAL ;
    PORT
      LAYER M3 ;
        RECT 147.9600 0.0000 147.9780 0.0380 ;
    END
  END r_k[42]
  PIN r_k[43]
    DIRECTION INPUT ;
    USE SIGNAL ;
    PORT
      LAYER M5 ;
        RECT 147.7440 0.0000 147.7680 0.0840 ;
    END
  END r_k[43]
  PIN r_k[44]
    DIRECTION INPUT ;
    USE SIGNAL ;
    PORT
      LAYER M3 ;
        RECT 147.6000 0.0000 147.6180 0.0380 ;
    END
  END r_k[44]
  PIN r_k[45]
    DIRECTION INPUT ;
    USE SIGNAL ;
    PORT
      LAYER M5 ;
        RECT 147.3600 0.0000 147.3840 0.0840 ;
    END
  END r_k[45]
  PIN r_k[46]
    DIRECTION INPUT ;
    USE SIGNAL ;
    PORT
      LAYER M3 ;
        RECT 147.1680 0.0000 147.1860 0.0380 ;
    END
  END r_k[46]
  PIN r_k[47]
    DIRECTION INPUT ;
    USE SIGNAL ;
    PORT
      LAYER M5 ;
        RECT 146.9760 0.0000 147.0000 0.0840 ;
    END
  END r_k[47]
  PIN r_k[48]
    DIRECTION INPUT ;
    USE SIGNAL ;
    PORT
      LAYER M3 ;
        RECT 146.8080 0.0000 146.8260 0.0380 ;
    END
  END r_k[48]
  PIN r_k[49]
    DIRECTION INPUT ;
    USE SIGNAL ;
    PORT
      LAYER M5 ;
        RECT 146.5920 0.0000 146.6160 0.0840 ;
    END
  END r_k[49]
  PIN r_k[4]
    DIRECTION INPUT ;
    USE SIGNAL ;
    PORT
      LAYER M3 ;
        RECT 155.0880 0.0000 155.1060 0.0380 ;
    END
  END r_k[4]
  PIN r_k[50]
    DIRECTION INPUT ;
    USE SIGNAL ;
    PORT
      LAYER M3 ;
        RECT 146.4480 0.0000 146.4660 0.0380 ;
    END
  END r_k[50]
  PIN r_k[51]
    DIRECTION INPUT ;
    USE SIGNAL ;
    PORT
      LAYER M5 ;
        RECT 146.3040 0.0000 146.3280 0.0840 ;
    END
  END r_k[51]
  PIN r_k[52]
    DIRECTION INPUT ;
    USE SIGNAL ;
    PORT
      LAYER M3 ;
        RECT 146.0880 0.0000 146.1060 0.0380 ;
    END
  END r_k[52]
  PIN r_k[53]
    DIRECTION INPUT ;
    USE SIGNAL ;
    PORT
      LAYER M5 ;
        RECT 145.9200 0.0000 145.9440 0.0840 ;
    END
  END r_k[53]
  PIN r_k[54]
    DIRECTION INPUT ;
    USE SIGNAL ;
    PORT
      LAYER M3 ;
        RECT 145.7280 0.0000 145.7460 0.0380 ;
    END
  END r_k[54]
  PIN r_k[55]
    DIRECTION INPUT ;
    USE SIGNAL ;
    PORT
      LAYER M5 ;
        RECT 145.5360 0.0000 145.5600 0.0840 ;
    END
  END r_k[55]
  PIN r_k[56]
    DIRECTION INPUT ;
    USE SIGNAL ;
    PORT
      LAYER M3 ;
        RECT 145.2960 0.0000 145.3140 0.0380 ;
    END
  END r_k[56]
  PIN r_k[57]
    DIRECTION INPUT ;
    USE SIGNAL ;
    PORT
      LAYER M5 ;
        RECT 145.1520 0.0000 145.1760 0.0840 ;
    END
  END r_k[57]
  PIN r_k[58]
    DIRECTION INPUT ;
    USE SIGNAL ;
    PORT
      LAYER M3 ;
        RECT 144.9360 0.0000 144.9540 0.0380 ;
    END
  END r_k[58]
  PIN r_k[59]
    DIRECTION INPUT ;
    USE SIGNAL ;
    PORT
      LAYER M5 ;
        RECT 144.7680 0.0000 144.7920 0.0840 ;
    END
  END r_k[59]
  PIN r_k[5]
    DIRECTION INPUT ;
    USE SIGNAL ;
    PORT
      LAYER M5 ;
        RECT 154.8480 0.0000 154.8720 0.0840 ;
    END
  END r_k[5]
  PIN r_k[60]
    DIRECTION INPUT ;
    USE SIGNAL ;
    PORT
      LAYER M3 ;
        RECT 144.5760 0.0000 144.5940 0.0380 ;
    END
  END r_k[60]
  PIN r_k[61]
    DIRECTION INPUT ;
    USE SIGNAL ;
    PORT
      LAYER M5 ;
        RECT 144.3840 0.0000 144.4080 0.0840 ;
    END
  END r_k[61]
  PIN r_k[62]
    DIRECTION INPUT ;
    USE SIGNAL ;
    PORT
      LAYER M3 ;
        RECT 144.2160 0.0000 144.2340 0.0380 ;
    END
  END r_k[62]
  PIN r_k[63]
    DIRECTION INPUT ;
    USE SIGNAL ;
    PORT
      LAYER M5 ;
        RECT 144.0000 0.0000 144.0240 0.0840 ;
    END
  END r_k[63]
  PIN r_k[64]
    DIRECTION INPUT ;
    USE SIGNAL ;
    PORT
      LAYER M3 ;
        RECT 143.8560 0.0000 143.8740 0.0380 ;
    END
  END r_k[64]
  PIN r_k[65]
    DIRECTION INPUT ;
    USE SIGNAL ;
    PORT
      LAYER M5 ;
        RECT 143.6160 0.0000 143.6400 0.0840 ;
    END
  END r_k[65]
  PIN r_k[66]
    DIRECTION INPUT ;
    USE SIGNAL ;
    PORT
      LAYER M3 ;
        RECT 143.4240 0.0000 143.4420 0.0380 ;
    END
  END r_k[66]
  PIN r_k[67]
    DIRECTION INPUT ;
    USE SIGNAL ;
    PORT
      LAYER M5 ;
        RECT 143.2320 0.0000 143.2560 0.0840 ;
    END
  END r_k[67]
  PIN r_k[68]
    DIRECTION INPUT ;
    USE SIGNAL ;
    PORT
      LAYER M3 ;
        RECT 143.0640 0.0000 143.0820 0.0380 ;
    END
  END r_k[68]
  PIN r_k[69]
    DIRECTION INPUT ;
    USE SIGNAL ;
    PORT
      LAYER M5 ;
        RECT 142.8480 0.0000 142.8720 0.0840 ;
    END
  END r_k[69]
  PIN r_k[6]
    DIRECTION INPUT ;
    USE SIGNAL ;
    PORT
      LAYER M3 ;
        RECT 154.7280 0.0000 154.7460 0.0380 ;
    END
  END r_k[6]
  PIN r_k[70]
    DIRECTION INPUT ;
    USE SIGNAL ;
    PORT
      LAYER M3 ;
        RECT 142.7040 0.0000 142.7220 0.0380 ;
    END
  END r_k[70]
  PIN r_k[71]
    DIRECTION INPUT ;
    USE SIGNAL ;
    PORT
      LAYER M5 ;
        RECT 142.5600 0.0000 142.5840 0.0840 ;
    END
  END r_k[71]
  PIN r_k[72]
    DIRECTION INPUT ;
    USE SIGNAL ;
    PORT
      LAYER M3 ;
        RECT 142.3440 0.0000 142.3620 0.0380 ;
    END
  END r_k[72]
  PIN r_k[73]
    DIRECTION INPUT ;
    USE SIGNAL ;
    PORT
      LAYER M5 ;
        RECT 142.1760 0.0000 142.2000 0.0840 ;
    END
  END r_k[73]
  PIN r_k[74]
    DIRECTION INPUT ;
    USE SIGNAL ;
    PORT
      LAYER M3 ;
        RECT 141.9840 0.0000 142.0020 0.0380 ;
    END
  END r_k[74]
  PIN r_k[75]
    DIRECTION INPUT ;
    USE SIGNAL ;
    PORT
      LAYER M5 ;
        RECT 141.7920 0.0000 141.8160 0.0840 ;
    END
  END r_k[75]
  PIN r_k[76]
    DIRECTION INPUT ;
    USE SIGNAL ;
    PORT
      LAYER M3 ;
        RECT 141.5520 0.0000 141.5700 0.0380 ;
    END
  END r_k[76]
  PIN r_k[77]
    DIRECTION INPUT ;
    USE SIGNAL ;
    PORT
      LAYER M5 ;
        RECT 141.4080 0.0000 141.4320 0.0840 ;
    END
  END r_k[77]
  PIN r_k[78]
    DIRECTION INPUT ;
    USE SIGNAL ;
    PORT
      LAYER M3 ;
        RECT 141.1920 0.0000 141.2100 0.0380 ;
    END
  END r_k[78]
  PIN r_k[79]
    DIRECTION INPUT ;
    USE SIGNAL ;
    PORT
      LAYER M5 ;
        RECT 141.0240 0.0000 141.0480 0.0840 ;
    END
  END r_k[79]
  PIN r_k[7]
    DIRECTION INPUT ;
    USE SIGNAL ;
    PORT
      LAYER M5 ;
        RECT 154.4640 0.0000 154.4880 0.0840 ;
    END
  END r_k[7]
  PIN r_k[80]
    DIRECTION INPUT ;
    USE SIGNAL ;
    PORT
      LAYER M3 ;
        RECT 140.8320 0.0000 140.8500 0.0380 ;
    END
  END r_k[80]
  PIN r_k[81]
    DIRECTION INPUT ;
    USE SIGNAL ;
    PORT
      LAYER M5 ;
        RECT 140.6400 0.0000 140.6640 0.0840 ;
    END
  END r_k[81]
  PIN r_k[82]
    DIRECTION INPUT ;
    USE SIGNAL ;
    PORT
      LAYER M3 ;
        RECT 140.4720 0.0000 140.4900 0.0380 ;
    END
  END r_k[82]
  PIN r_k[83]
    DIRECTION INPUT ;
    USE SIGNAL ;
    PORT
      LAYER M5 ;
        RECT 140.2560 0.0000 140.2800 0.0840 ;
    END
  END r_k[83]
  PIN r_k[84]
    DIRECTION INPUT ;
    USE SIGNAL ;
    PORT
      LAYER M3 ;
        RECT 140.1120 0.0000 140.1300 0.0380 ;
    END
  END r_k[84]
  PIN r_k[85]
    DIRECTION INPUT ;
    USE SIGNAL ;
    PORT
      LAYER M5 ;
        RECT 139.8720 0.0000 139.8960 0.0840 ;
    END
  END r_k[85]
  PIN r_k[86]
    DIRECTION INPUT ;
    USE SIGNAL ;
    PORT
      LAYER M3 ;
        RECT 139.6800 0.0000 139.6980 0.0380 ;
    END
  END r_k[86]
  PIN r_k[87]
    DIRECTION INPUT ;
    USE SIGNAL ;
    PORT
      LAYER M5 ;
        RECT 139.4880 0.0000 139.5120 0.0840 ;
    END
  END r_k[87]
  PIN r_k[88]
    DIRECTION INPUT ;
    USE SIGNAL ;
    PORT
      LAYER M3 ;
        RECT 139.3200 0.0000 139.3380 0.0380 ;
    END
  END r_k[88]
  PIN r_k[89]
    DIRECTION INPUT ;
    USE SIGNAL ;
    PORT
      LAYER M5 ;
        RECT 139.1040 0.0000 139.1280 0.0840 ;
    END
  END r_k[89]
  PIN r_k[8]
    DIRECTION INPUT ;
    USE SIGNAL ;
    PORT
      LAYER M3 ;
        RECT 154.2960 0.0000 154.3140 0.0380 ;
    END
  END r_k[8]
  PIN r_k[90]
    DIRECTION INPUT ;
    USE SIGNAL ;
    PORT
      LAYER M3 ;
        RECT 138.9600 0.0000 138.9780 0.0380 ;
    END
  END r_k[90]
  PIN r_k[91]
    DIRECTION INPUT ;
    USE SIGNAL ;
    PORT
      LAYER M5 ;
        RECT 138.7200 0.0000 138.7440 0.0840 ;
    END
  END r_k[91]
  PIN r_k[92]
    DIRECTION INPUT ;
    USE SIGNAL ;
    PORT
      LAYER M3 ;
        RECT 138.6000 0.0000 138.6180 0.0380 ;
    END
  END r_k[92]
  PIN r_k[93]
    DIRECTION INPUT ;
    USE SIGNAL ;
    PORT
      LAYER M5 ;
        RECT 138.4320 0.0000 138.4560 0.0840 ;
    END
  END r_k[93]
  PIN r_k[94]
    DIRECTION INPUT ;
    USE SIGNAL ;
    PORT
      LAYER M3 ;
        RECT 138.2400 0.0000 138.2580 0.0380 ;
    END
  END r_k[94]
  PIN r_k[95]
    DIRECTION INPUT ;
    USE SIGNAL ;
    PORT
      LAYER M5 ;
        RECT 138.0480 0.0000 138.0720 0.0840 ;
    END
  END r_k[95]
  PIN r_k[96]
    DIRECTION INPUT ;
    USE SIGNAL ;
    PORT
      LAYER M3 ;
        RECT 137.8080 0.0000 137.8260 0.0380 ;
    END
  END r_k[96]
  PIN r_k[97]
    DIRECTION INPUT ;
    USE SIGNAL ;
    PORT
      LAYER M5 ;
        RECT 137.6640 0.0000 137.6880 0.0840 ;
    END
  END r_k[97]
  PIN r_k[98]
    DIRECTION INPUT ;
    USE SIGNAL ;
    PORT
      LAYER M3 ;
        RECT 137.4480 0.0000 137.4660 0.0380 ;
    END
  END r_k[98]
  PIN r_k[99]
    DIRECTION INPUT ;
    USE SIGNAL ;
    PORT
      LAYER M5 ;
        RECT 137.2800 0.0000 137.3040 0.0840 ;
    END
  END r_k[99]
  PIN r_k[9]
    DIRECTION INPUT ;
    USE SIGNAL ;
    PORT
      LAYER M5 ;
        RECT 154.1760 0.0000 154.2000 0.0840 ;
    END
  END r_k[9]
  PIN r_v
    DIRECTION INPUT ;
    USE SIGNAL ;
    PORT
      LAYER M5 ;
        RECT 168.3840 0.0000 168.4080 0.0840 ;
    END
  END r_v
  PIN r_w[0]
    DIRECTION INPUT ;
    USE SIGNAL ;
    PORT
      LAYER M3 ;
        RECT 131.8320 0.0000 131.8500 0.0380 ;
    END
  END r_w[0]
  PIN r_w[100]
    DIRECTION INPUT ;
    USE SIGNAL ;
    PORT
      LAYER M3 ;
        RECT 113.1120 0.0000 113.1300 0.0380 ;
    END
  END r_w[100]
  PIN r_w[101]
    DIRECTION INPUT ;
    USE SIGNAL ;
    PORT
      LAYER M5 ;
        RECT 112.8960 0.0000 112.9200 0.0840 ;
    END
  END r_w[101]
  PIN r_w[102]
    DIRECTION INPUT ;
    USE SIGNAL ;
    PORT
      LAYER M3 ;
        RECT 112.7520 0.0000 112.7700 0.0380 ;
    END
  END r_w[102]
  PIN r_w[103]
    DIRECTION INPUT ;
    USE SIGNAL ;
    PORT
      LAYER M5 ;
        RECT 112.5120 0.0000 112.5360 0.0840 ;
    END
  END r_w[103]
  PIN r_w[104]
    DIRECTION INPUT ;
    USE SIGNAL ;
    PORT
      LAYER M3 ;
        RECT 112.3200 0.0000 112.3380 0.0380 ;
    END
  END r_w[104]
  PIN r_w[105]
    DIRECTION INPUT ;
    USE SIGNAL ;
    PORT
      LAYER M5 ;
        RECT 112.1280 0.0000 112.1520 0.0840 ;
    END
  END r_w[105]
  PIN r_w[106]
    DIRECTION INPUT ;
    USE SIGNAL ;
    PORT
      LAYER M3 ;
        RECT 111.9600 0.0000 111.9780 0.0380 ;
    END
  END r_w[106]
  PIN r_w[107]
    DIRECTION INPUT ;
    USE SIGNAL ;
    PORT
      LAYER M5 ;
        RECT 111.7440 0.0000 111.7680 0.0840 ;
    END
  END r_w[107]
  PIN r_w[108]
    DIRECTION INPUT ;
    USE SIGNAL ;
    PORT
      LAYER M3 ;
        RECT 111.6000 0.0000 111.6180 0.0380 ;
    END
  END r_w[108]
  PIN r_w[109]
    DIRECTION INPUT ;
    USE SIGNAL ;
    PORT
      LAYER M5 ;
        RECT 111.3600 0.0000 111.3840 0.0840 ;
    END
  END r_w[109]
  PIN r_w[10]
    DIRECTION INPUT ;
    USE SIGNAL ;
    PORT
      LAYER M3 ;
        RECT 129.9600 0.0000 129.9780 0.0380 ;
    END
  END r_w[10]
  PIN r_w[110]
    DIRECTION INPUT ;
    USE SIGNAL ;
    PORT
      LAYER M3 ;
        RECT 111.2400 0.0000 111.2580 0.0380 ;
    END
  END r_w[110]
  PIN r_w[111]
    DIRECTION INPUT ;
    USE SIGNAL ;
    PORT
      LAYER M5 ;
        RECT 111.0720 0.0000 111.0960 0.0840 ;
    END
  END r_w[111]
  PIN r_w[112]
    DIRECTION INPUT ;
    USE SIGNAL ;
    PORT
      LAYER M3 ;
        RECT 110.8800 0.0000 110.8980 0.0380 ;
    END
  END r_w[112]
  PIN r_w[113]
    DIRECTION INPUT ;
    USE SIGNAL ;
    PORT
      LAYER M5 ;
        RECT 110.6880 0.0000 110.7120 0.0840 ;
    END
  END r_w[113]
  PIN r_w[114]
    DIRECTION INPUT ;
    USE SIGNAL ;
    PORT
      LAYER M3 ;
        RECT 110.4480 0.0000 110.4660 0.0380 ;
    END
  END r_w[114]
  PIN r_w[115]
    DIRECTION INPUT ;
    USE SIGNAL ;
    PORT
      LAYER M5 ;
        RECT 110.3040 0.0000 110.3280 0.0840 ;
    END
  END r_w[115]
  PIN r_w[116]
    DIRECTION INPUT ;
    USE SIGNAL ;
    PORT
      LAYER M3 ;
        RECT 110.0880 0.0000 110.1060 0.0380 ;
    END
  END r_w[116]
  PIN r_w[117]
    DIRECTION INPUT ;
    USE SIGNAL ;
    PORT
      LAYER M5 ;
        RECT 109.9200 0.0000 109.9440 0.0840 ;
    END
  END r_w[117]
  PIN r_w[118]
    DIRECTION INPUT ;
    USE SIGNAL ;
    PORT
      LAYER M3 ;
        RECT 109.7280 0.0000 109.7460 0.0380 ;
    END
  END r_w[118]
  PIN r_w[119]
    DIRECTION INPUT ;
    USE SIGNAL ;
    PORT
      LAYER M5 ;
        RECT 109.5360 0.0000 109.5600 0.0840 ;
    END
  END r_w[119]
  PIN r_w[11]
    DIRECTION INPUT ;
    USE SIGNAL ;
    PORT
      LAYER M5 ;
        RECT 129.7920 0.0000 129.8160 0.0840 ;
    END
  END r_w[11]
  PIN r_w[120]
    DIRECTION INPUT ;
    USE SIGNAL ;
    PORT
      LAYER M3 ;
        RECT 109.3680 0.0000 109.3860 0.0380 ;
    END
  END r_w[120]
  PIN r_w[121]
    DIRECTION INPUT ;
    USE SIGNAL ;
    PORT
      LAYER M5 ;
        RECT 109.1520 0.0000 109.1760 0.0840 ;
    END
  END r_w[121]
  PIN r_w[122]
    DIRECTION INPUT ;
    USE SIGNAL ;
    PORT
      LAYER M3 ;
        RECT 109.0080 0.0000 109.0260 0.0380 ;
    END
  END r_w[122]
  PIN r_w[123]
    DIRECTION INPUT ;
    USE SIGNAL ;
    PORT
      LAYER M5 ;
        RECT 108.7680 0.0000 108.7920 0.0840 ;
    END
  END r_w[123]
  PIN r_w[124]
    DIRECTION INPUT ;
    USE SIGNAL ;
    PORT
      LAYER M3 ;
        RECT 108.5760 0.0000 108.5940 0.0380 ;
    END
  END r_w[124]
  PIN r_w[125]
    DIRECTION INPUT ;
    USE SIGNAL ;
    PORT
      LAYER M5 ;
        RECT 108.3840 0.0000 108.4080 0.0840 ;
    END
  END r_w[125]
  PIN r_w[126]
    DIRECTION INPUT ;
    USE SIGNAL ;
    PORT
      LAYER M3 ;
        RECT 108.2160 0.0000 108.2340 0.0380 ;
    END
  END r_w[126]
  PIN r_w[127]
    DIRECTION INPUT ;
    USE SIGNAL ;
    PORT
      LAYER M5 ;
        RECT 108.0000 0.0000 108.0240 0.0840 ;
    END
  END r_w[127]
  PIN r_w[12]
    DIRECTION INPUT ;
    USE SIGNAL ;
    PORT
      LAYER M3 ;
        RECT 129.6000 0.0000 129.6180 0.0380 ;
    END
  END r_w[12]
  PIN r_w[13]
    DIRECTION INPUT ;
    USE SIGNAL ;
    PORT
      LAYER M5 ;
        RECT 129.4080 0.0000 129.4320 0.0840 ;
    END
  END r_w[13]
  PIN r_w[14]
    DIRECTION INPUT ;
    USE SIGNAL ;
    PORT
      LAYER M3 ;
        RECT 129.2400 0.0000 129.2580 0.0380 ;
    END
  END r_w[14]
  PIN r_w[15]
    DIRECTION INPUT ;
    USE SIGNAL ;
    PORT
      LAYER M5 ;
        RECT 129.0240 0.0000 129.0480 0.0840 ;
    END
  END r_w[15]
  PIN r_w[16]
    DIRECTION INPUT ;
    USE SIGNAL ;
    PORT
      LAYER M3 ;
        RECT 128.8080 0.0000 128.8260 0.0380 ;
    END
  END r_w[16]
  PIN r_w[17]
    DIRECTION INPUT ;
    USE SIGNAL ;
    PORT
      LAYER M5 ;
        RECT 128.6400 0.0000 128.6640 0.0840 ;
    END
  END r_w[17]
  PIN r_w[18]
    DIRECTION INPUT ;
    USE SIGNAL ;
    PORT
      LAYER M3 ;
        RECT 128.4480 0.0000 128.4660 0.0380 ;
    END
  END r_w[18]
  PIN r_w[19]
    DIRECTION INPUT ;
    USE SIGNAL ;
    PORT
      LAYER M5 ;
        RECT 128.2560 0.0000 128.2800 0.0840 ;
    END
  END r_w[19]
  PIN r_w[1]
    DIRECTION INPUT ;
    USE SIGNAL ;
    PORT
      LAYER M5 ;
        RECT 131.6160 0.0000 131.6400 0.0840 ;
    END
  END r_w[1]
  PIN r_w[20]
    DIRECTION INPUT ;
    USE SIGNAL ;
    PORT
      LAYER M3 ;
        RECT 128.0880 0.0000 128.1060 0.0380 ;
    END
  END r_w[20]
  PIN r_w[21]
    DIRECTION INPUT ;
    USE SIGNAL ;
    PORT
      LAYER M5 ;
        RECT 127.8720 0.0000 127.8960 0.0840 ;
    END
  END r_w[21]
  PIN r_w[22]
    DIRECTION INPUT ;
    USE SIGNAL ;
    PORT
      LAYER M3 ;
        RECT 127.7280 0.0000 127.7460 0.0380 ;
    END
  END r_w[22]
  PIN r_w[23]
    DIRECTION INPUT ;
    USE SIGNAL ;
    PORT
      LAYER M5 ;
        RECT 127.4880 0.0000 127.5120 0.0840 ;
    END
  END r_w[23]
  PIN r_w[24]
    DIRECTION INPUT ;
    USE SIGNAL ;
    PORT
      LAYER M3 ;
        RECT 127.3680 0.0000 127.3860 0.0380 ;
    END
  END r_w[24]
  PIN r_w[25]
    DIRECTION INPUT ;
    USE SIGNAL ;
    PORT
      LAYER M5 ;
        RECT 127.1040 0.0000 127.1280 0.0840 ;
    END
  END r_w[25]
  PIN r_w[26]
    DIRECTION INPUT ;
    USE SIGNAL ;
    PORT
      LAYER M3 ;
        RECT 126.9360 0.0000 126.9540 0.0380 ;
    END
  END r_w[26]
  PIN r_w[27]
    DIRECTION INPUT ;
    USE SIGNAL ;
    PORT
      LAYER M5 ;
        RECT 126.8160 0.0000 126.8400 0.0840 ;
    END
  END r_w[27]
  PIN r_w[28]
    DIRECTION INPUT ;
    USE SIGNAL ;
    PORT
      LAYER M3 ;
        RECT 126.5760 0.0000 126.5940 0.0380 ;
    END
  END r_w[28]
  PIN r_w[29]
    DIRECTION INPUT ;
    USE SIGNAL ;
    PORT
      LAYER M5 ;
        RECT 126.4320 0.0000 126.4560 0.0840 ;
    END
  END r_w[29]
  PIN r_w[2]
    DIRECTION INPUT ;
    USE SIGNAL ;
    PORT
      LAYER M3 ;
        RECT 131.4720 0.0000 131.4900 0.0380 ;
    END
  END r_w[2]
  PIN r_w[30]
    DIRECTION INPUT ;
    USE SIGNAL ;
    PORT
      LAYER M3 ;
        RECT 126.2160 0.0000 126.2340 0.0380 ;
    END
  END r_w[30]
  PIN r_w[31]
    DIRECTION INPUT ;
    USE SIGNAL ;
    PORT
      LAYER M5 ;
        RECT 126.0480 0.0000 126.0720 0.0840 ;
    END
  END r_w[31]
  PIN r_w[32]
    DIRECTION INPUT ;
    USE SIGNAL ;
    PORT
      LAYER M3 ;
        RECT 125.8560 0.0000 125.8740 0.0380 ;
    END
  END r_w[32]
  PIN r_w[33]
    DIRECTION INPUT ;
    USE SIGNAL ;
    PORT
      LAYER M5 ;
        RECT 125.6640 0.0000 125.6880 0.0840 ;
    END
  END r_w[33]
  PIN r_w[34]
    DIRECTION INPUT ;
    USE SIGNAL ;
    PORT
      LAYER M3 ;
        RECT 125.4960 0.0000 125.5140 0.0380 ;
    END
  END r_w[34]
  PIN r_w[35]
    DIRECTION INPUT ;
    USE SIGNAL ;
    PORT
      LAYER M5 ;
        RECT 125.2800 0.0000 125.3040 0.0840 ;
    END
  END r_w[35]
  PIN r_w[36]
    DIRECTION INPUT ;
    USE SIGNAL ;
    PORT
      LAYER M3 ;
        RECT 125.0640 0.0000 125.0820 0.0380 ;
    END
  END r_w[36]
  PIN r_w[37]
    DIRECTION INPUT ;
    USE SIGNAL ;
    PORT
      LAYER M5 ;
        RECT 124.8960 0.0000 124.9200 0.0840 ;
    END
  END r_w[37]
  PIN r_w[38]
    DIRECTION INPUT ;
    USE SIGNAL ;
    PORT
      LAYER M3 ;
        RECT 124.7040 0.0000 124.7220 0.0380 ;
    END
  END r_w[38]
  PIN r_w[39]
    DIRECTION INPUT ;
    USE SIGNAL ;
    PORT
      LAYER M5 ;
        RECT 124.5120 0.0000 124.5360 0.0840 ;
    END
  END r_w[39]
  PIN r_w[3]
    DIRECTION INPUT ;
    USE SIGNAL ;
    PORT
      LAYER M5 ;
        RECT 131.2320 0.0000 131.2560 0.0840 ;
    END
  END r_w[3]
  PIN r_w[40]
    DIRECTION INPUT ;
    USE SIGNAL ;
    PORT
      LAYER M3 ;
        RECT 124.3440 0.0000 124.3620 0.0380 ;
    END
  END r_w[40]
  PIN r_w[41]
    DIRECTION INPUT ;
    USE SIGNAL ;
    PORT
      LAYER M5 ;
        RECT 124.1280 0.0000 124.1520 0.0840 ;
    END
  END r_w[41]
  PIN r_w[42]
    DIRECTION INPUT ;
    USE SIGNAL ;
    PORT
      LAYER M3 ;
        RECT 123.9840 0.0000 124.0020 0.0380 ;
    END
  END r_w[42]
  PIN r_w[43]
    DIRECTION INPUT ;
    USE SIGNAL ;
    PORT
      LAYER M5 ;
        RECT 123.7440 0.0000 123.7680 0.0840 ;
    END
  END r_w[43]
  PIN r_w[44]
    DIRECTION INPUT ;
    USE SIGNAL ;
    PORT
      LAYER M3 ;
        RECT 123.6240 0.0000 123.6420 0.0380 ;
    END
  END r_w[44]
  PIN r_w[45]
    DIRECTION INPUT ;
    USE SIGNAL ;
    PORT
      LAYER M5 ;
        RECT 123.3600 0.0000 123.3840 0.0840 ;
    END
  END r_w[45]
  PIN r_w[46]
    DIRECTION INPUT ;
    USE SIGNAL ;
    PORT
      LAYER M3 ;
        RECT 123.1920 0.0000 123.2100 0.0380 ;
    END
  END r_w[46]
  PIN r_w[47]
    DIRECTION INPUT ;
    USE SIGNAL ;
    PORT
      LAYER M5 ;
        RECT 123.0720 0.0000 123.0960 0.0840 ;
    END
  END r_w[47]
  PIN r_w[48]
    DIRECTION INPUT ;
    USE SIGNAL ;
    PORT
      LAYER M3 ;
        RECT 122.8320 0.0000 122.8500 0.0380 ;
    END
  END r_w[48]
  PIN r_w[49]
    DIRECTION INPUT ;
    USE SIGNAL ;
    PORT
      LAYER M5 ;
        RECT 122.6880 0.0000 122.7120 0.0840 ;
    END
  END r_w[49]
  PIN r_w[4]
    DIRECTION INPUT ;
    USE SIGNAL ;
    PORT
      LAYER M3 ;
        RECT 131.1120 0.0000 131.1300 0.0380 ;
    END
  END r_w[4]
  PIN r_w[50]
    DIRECTION INPUT ;
    USE SIGNAL ;
    PORT
      LAYER M3 ;
        RECT 122.4720 0.0000 122.4900 0.0380 ;
    END
  END r_w[50]
  PIN r_w[51]
    DIRECTION INPUT ;
    USE SIGNAL ;
    PORT
      LAYER M5 ;
        RECT 122.3040 0.0000 122.3280 0.0840 ;
    END
  END r_w[51]
  PIN r_w[52]
    DIRECTION INPUT ;
    USE SIGNAL ;
    PORT
      LAYER M3 ;
        RECT 122.1120 0.0000 122.1300 0.0380 ;
    END
  END r_w[52]
  PIN r_w[53]
    DIRECTION INPUT ;
    USE SIGNAL ;
    PORT
      LAYER M5 ;
        RECT 121.9200 0.0000 121.9440 0.0840 ;
    END
  END r_w[53]
  PIN r_w[54]
    DIRECTION INPUT ;
    USE SIGNAL ;
    PORT
      LAYER M3 ;
        RECT 121.6800 0.0000 121.6980 0.0380 ;
    END
  END r_w[54]
  PIN r_w[55]
    DIRECTION INPUT ;
    USE SIGNAL ;
    PORT
      LAYER M5 ;
        RECT 121.5360 0.0000 121.5600 0.0840 ;
    END
  END r_w[55]
  PIN r_w[56]
    DIRECTION INPUT ;
    USE SIGNAL ;
    PORT
      LAYER M3 ;
        RECT 121.3200 0.0000 121.3380 0.0380 ;
    END
  END r_w[56]
  PIN r_w[57]
    DIRECTION INPUT ;
    USE SIGNAL ;
    PORT
      LAYER M5 ;
        RECT 121.1520 0.0000 121.1760 0.0840 ;
    END
  END r_w[57]
  PIN r_w[58]
    DIRECTION INPUT ;
    USE SIGNAL ;
    PORT
      LAYER M3 ;
        RECT 120.9600 0.0000 120.9780 0.0380 ;
    END
  END r_w[58]
  PIN r_w[59]
    DIRECTION INPUT ;
    USE SIGNAL ;
    PORT
      LAYER M5 ;
        RECT 120.7680 0.0000 120.7920 0.0840 ;
    END
  END r_w[59]
  PIN r_w[5]
    DIRECTION INPUT ;
    USE SIGNAL ;
    PORT
      LAYER M5 ;
        RECT 130.8480 0.0000 130.8720 0.0840 ;
    END
  END r_w[5]
  PIN r_w[60]
    DIRECTION INPUT ;
    USE SIGNAL ;
    PORT
      LAYER M3 ;
        RECT 120.6000 0.0000 120.6180 0.0380 ;
    END
  END r_w[60]
  PIN r_w[61]
    DIRECTION INPUT ;
    USE SIGNAL ;
    PORT
      LAYER M5 ;
        RECT 120.3840 0.0000 120.4080 0.0840 ;
    END
  END r_w[61]
  PIN r_w[62]
    DIRECTION INPUT ;
    USE SIGNAL ;
    PORT
      LAYER M3 ;
        RECT 120.2400 0.0000 120.2580 0.0380 ;
    END
  END r_w[62]
  PIN r_w[63]
    DIRECTION INPUT ;
    USE SIGNAL ;
    PORT
      LAYER M5 ;
        RECT 120.0000 0.0000 120.0240 0.0840 ;
    END
  END r_w[63]
  PIN r_w[64]
    DIRECTION INPUT ;
    USE SIGNAL ;
    PORT
      LAYER M3 ;
        RECT 119.8080 0.0000 119.8260 0.0380 ;
    END
  END r_w[64]
  PIN r_w[65]
    DIRECTION INPUT ;
    USE SIGNAL ;
    PORT
      LAYER M5 ;
        RECT 119.6160 0.0000 119.6400 0.0840 ;
    END
  END r_w[65]
  PIN r_w[66]
    DIRECTION INPUT ;
    USE SIGNAL ;
    PORT
      LAYER M3 ;
        RECT 119.4480 0.0000 119.4660 0.0380 ;
    END
  END r_w[66]
  PIN r_w[67]
    DIRECTION INPUT ;
    USE SIGNAL ;
    PORT
      LAYER M5 ;
        RECT 119.2320 0.0000 119.2560 0.0840 ;
    END
  END r_w[67]
  PIN r_w[68]
    DIRECTION INPUT ;
    USE SIGNAL ;
    PORT
      LAYER M3 ;
        RECT 119.0880 0.0000 119.1060 0.0380 ;
    END
  END r_w[68]
  PIN r_w[69]
    DIRECTION INPUT ;
    USE SIGNAL ;
    PORT
      LAYER M5 ;
        RECT 118.9440 0.0000 118.9680 0.0840 ;
    END
  END r_w[69]
  PIN r_w[6]
    DIRECTION INPUT ;
    USE SIGNAL ;
    PORT
      LAYER M3 ;
        RECT 130.6800 0.0000 130.6980 0.0380 ;
    END
  END r_w[6]
  PIN r_w[70]
    DIRECTION INPUT ;
    USE SIGNAL ;
    PORT
      LAYER M3 ;
        RECT 118.7280 0.0000 118.7460 0.0380 ;
    END
  END r_w[70]
  PIN r_w[71]
    DIRECTION INPUT ;
    USE SIGNAL ;
    PORT
      LAYER M5 ;
        RECT 118.5600 0.0000 118.5840 0.0840 ;
    END
  END r_w[71]
  PIN r_w[72]
    DIRECTION INPUT ;
    USE SIGNAL ;
    PORT
      LAYER M3 ;
        RECT 118.3680 0.0000 118.3860 0.0380 ;
    END
  END r_w[72]
  PIN r_w[73]
    DIRECTION INPUT ;
    USE SIGNAL ;
    PORT
      LAYER M5 ;
        RECT 118.1760 0.0000 118.2000 0.0840 ;
    END
  END r_w[73]
  PIN r_w[74]
    DIRECTION INPUT ;
    USE SIGNAL ;
    PORT
      LAYER M3 ;
        RECT 117.9360 0.0000 117.9540 0.0380 ;
    END
  END r_w[74]
  PIN r_w[75]
    DIRECTION INPUT ;
    USE SIGNAL ;
    PORT
      LAYER M5 ;
        RECT 117.7920 0.0000 117.8160 0.0840 ;
    END
  END r_w[75]
  PIN r_w[76]
    DIRECTION INPUT ;
    USE SIGNAL ;
    PORT
      LAYER M3 ;
        RECT 117.5760 0.0000 117.5940 0.0380 ;
    END
  END r_w[76]
  PIN r_w[77]
    DIRECTION INPUT ;
    USE SIGNAL ;
    PORT
      LAYER M5 ;
        RECT 117.4080 0.0000 117.4320 0.0840 ;
    END
  END r_w[77]
  PIN r_w[78]
    DIRECTION INPUT ;
    USE SIGNAL ;
    PORT
      LAYER M3 ;
        RECT 117.2160 0.0000 117.2340 0.0380 ;
    END
  END r_w[78]
  PIN r_w[79]
    DIRECTION INPUT ;
    USE SIGNAL ;
    PORT
      LAYER M5 ;
        RECT 117.0240 0.0000 117.0480 0.0840 ;
    END
  END r_w[79]
  PIN r_w[7]
    DIRECTION INPUT ;
    USE SIGNAL ;
    PORT
      LAYER M5 ;
        RECT 130.5600 0.0000 130.5840 0.0840 ;
    END
  END r_w[7]
  PIN r_w[80]
    DIRECTION INPUT ;
    USE SIGNAL ;
    PORT
      LAYER M3 ;
        RECT 116.8560 0.0000 116.8740 0.0380 ;
    END
  END r_w[80]
  PIN r_w[81]
    DIRECTION INPUT ;
    USE SIGNAL ;
    PORT
      LAYER M5 ;
        RECT 116.6400 0.0000 116.6640 0.0840 ;
    END
  END r_w[81]
  PIN r_w[82]
    DIRECTION INPUT ;
    USE SIGNAL ;
    PORT
      LAYER M3 ;
        RECT 116.4960 0.0000 116.5140 0.0380 ;
    END
  END r_w[82]
  PIN r_w[83]
    DIRECTION INPUT ;
    USE SIGNAL ;
    PORT
      LAYER M5 ;
        RECT 116.2560 0.0000 116.2800 0.0840 ;
    END
  END r_w[83]
  PIN r_w[84]
    DIRECTION INPUT ;
    USE SIGNAL ;
    PORT
      LAYER M3 ;
        RECT 116.0640 0.0000 116.0820 0.0380 ;
    END
  END r_w[84]
  PIN r_w[85]
    DIRECTION INPUT ;
    USE SIGNAL ;
    PORT
      LAYER M5 ;
        RECT 115.8720 0.0000 115.8960 0.0840 ;
    END
  END r_w[85]
  PIN r_w[86]
    DIRECTION INPUT ;
    USE SIGNAL ;
    PORT
      LAYER M3 ;
        RECT 115.7040 0.0000 115.7220 0.0380 ;
    END
  END r_w[86]
  PIN r_w[87]
    DIRECTION INPUT ;
    USE SIGNAL ;
    PORT
      LAYER M5 ;
        RECT 115.4880 0.0000 115.5120 0.0840 ;
    END
  END r_w[87]
  PIN r_w[88]
    DIRECTION INPUT ;
    USE SIGNAL ;
    PORT
      LAYER M3 ;
        RECT 115.3440 0.0000 115.3620 0.0380 ;
    END
  END r_w[88]
  PIN r_w[89]
    DIRECTION INPUT ;
    USE SIGNAL ;
    PORT
      LAYER M5 ;
        RECT 115.2000 0.0000 115.2240 0.0840 ;
    END
  END r_w[89]
  PIN r_w[8]
    DIRECTION INPUT ;
    USE SIGNAL ;
    PORT
      LAYER M3 ;
        RECT 130.3200 0.0000 130.3380 0.0380 ;
    END
  END r_w[8]
  PIN r_w[90]
    DIRECTION INPUT ;
    USE SIGNAL ;
    PORT
      LAYER M3 ;
        RECT 114.9840 0.0000 115.0020 0.0380 ;
    END
  END r_w[90]
  PIN r_w[91]
    DIRECTION INPUT ;
    USE SIGNAL ;
    PORT
      LAYER M5 ;
        RECT 114.8160 0.0000 114.8400 0.0840 ;
    END
  END r_w[91]
  PIN r_w[92]
    DIRECTION INPUT ;
    USE SIGNAL ;
    PORT
      LAYER M3 ;
        RECT 114.6240 0.0000 114.6420 0.0380 ;
    END
  END r_w[92]
  PIN r_w[93]
    DIRECTION INPUT ;
    USE SIGNAL ;
    PORT
      LAYER M5 ;
        RECT 114.4320 0.0000 114.4560 0.0840 ;
    END
  END r_w[93]
  PIN r_w[94]
    DIRECTION INPUT ;
    USE SIGNAL ;
    PORT
      LAYER M3 ;
        RECT 114.1920 0.0000 114.2100 0.0380 ;
    END
  END r_w[94]
  PIN r_w[95]
    DIRECTION INPUT ;
    USE SIGNAL ;
    PORT
      LAYER M5 ;
        RECT 114.0480 0.0000 114.0720 0.0840 ;
    END
  END r_w[95]
  PIN r_w[96]
    DIRECTION INPUT ;
    USE SIGNAL ;
    PORT
      LAYER M3 ;
        RECT 113.8320 0.0000 113.8500 0.0380 ;
    END
  END r_w[96]
  PIN r_w[97]
    DIRECTION INPUT ;
    USE SIGNAL ;
    PORT
      LAYER M5 ;
        RECT 113.6640 0.0000 113.6880 0.0840 ;
    END
  END r_w[97]
  PIN r_w[98]
    DIRECTION INPUT ;
    USE SIGNAL ;
    PORT
      LAYER M3 ;
        RECT 113.4720 0.0000 113.4900 0.0380 ;
    END
  END r_w[98]
  PIN r_w[99]
    DIRECTION INPUT ;
    USE SIGNAL ;
    PORT
      LAYER M5 ;
        RECT 113.2800 0.0000 113.3040 0.0840 ;
    END
  END r_w[99]
  PIN r_w[9]
    DIRECTION INPUT ;
    USE SIGNAL ;
    PORT
      LAYER M5 ;
        RECT 130.1760 0.0000 130.2000 0.0840 ;
    END
  END r_w[9]
  PIN rst_n
    DIRECTION INPUT ;
    USE SIGNAL ;
    PORT
      LAYER M3 ;
        RECT 86.4720 0.0000 86.4900 0.0380 ;
    END
  END rst_n
  OBS
    LAYER M1 ;
      RECT 0.5 0.5 172.300 345.100 ;
    LAYER M2 ;
      RECT 0.5 0.5 172.300 345.100 ;
    LAYER M3 ;
      RECT 0.5 0.5 172.300 345.100 ;
    LAYER M4 ;
      RECT 0.5 0.5 172.300 345.100 ;
    LAYER M5 ;
      RECT 0.5 0.5 172.300 345.100 ;
    LAYER M6 ;
      RECT 0.5 0.5 172.300 345.100 ;
    LAYER M7 ;
      RECT 0.5 0.5 172.300 345.100 ;
  END
END ot_s81sl_ve_m
END LIBRARY
